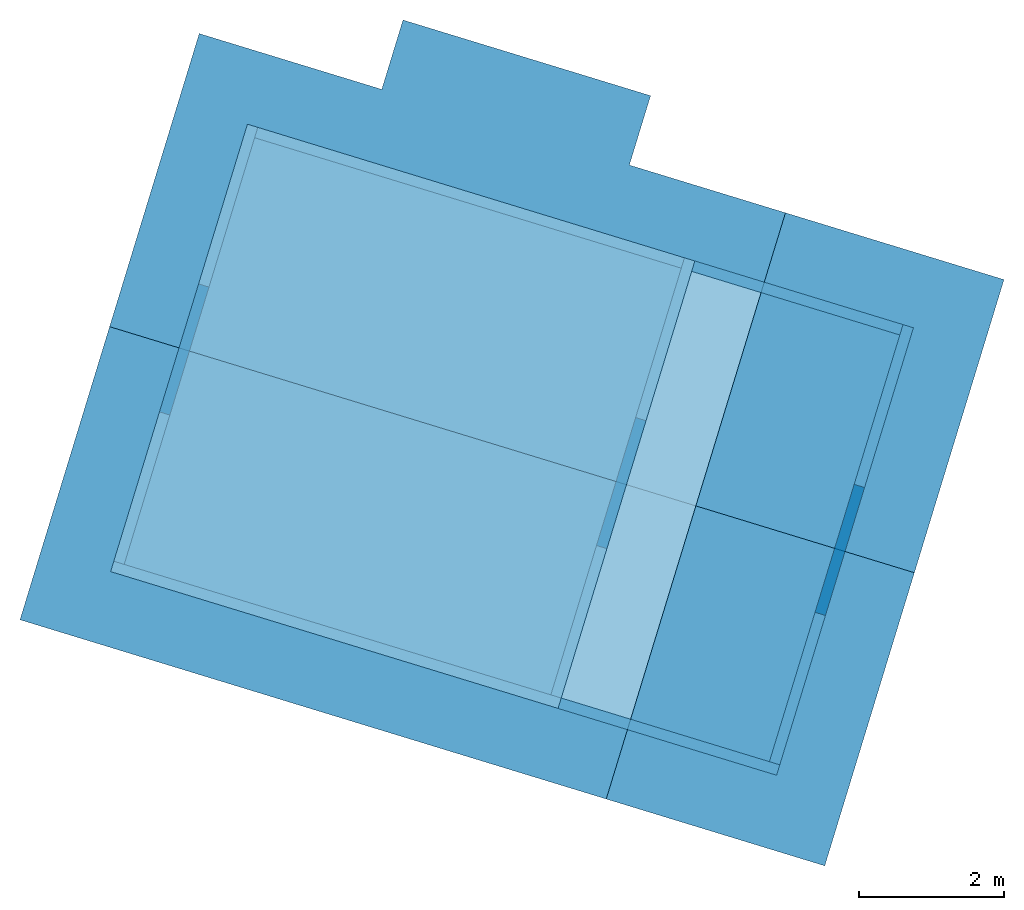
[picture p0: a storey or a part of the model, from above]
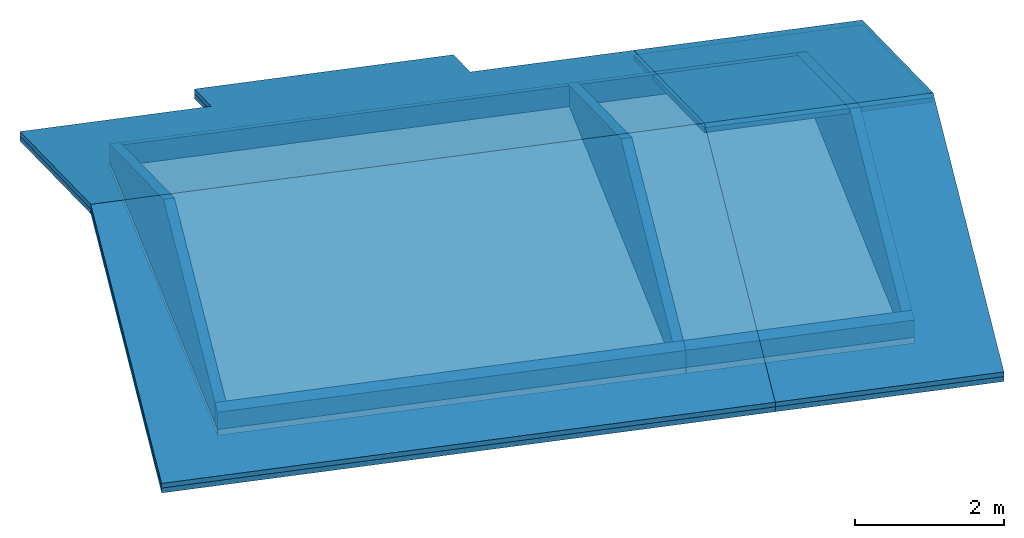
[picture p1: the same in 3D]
Properties of the parts of a building model (IFC2X3), part 1 of 7

# File
Description: ViewDefinition [, SurfaceGeometryAddOnView, QuantityTakeOffAddOnView, SpaceBoundary2ndLevelAddOnView], Option [Elements to export: Visible elements (on all stories)], Option [Partial Structure Display: Entire Model], Option [IFC Domain: All], Option [Structural Function: All Elements], Option [Convert Grid elements: On], Option [Convert IFC Annotations and Archicad 2D elements: On], Option [Convert 2D symbols of Doors and Windows: On], Option [Export geometries that Participates in Collision Detection only: Off], Option [Split complex elements: Off], Option [Material Preservation: Explode where necessary], Option [IFC Model position: Survey Point and Project Origin], Option [Curtain Wall export mode: Single Element], Option [Railing export mode: Single Element], Option [Stair export mode: Single Element], Option [Properties To Export: Current Scheme properties only], Option [Space containment: On], Option [IFC Domain For Space Containment: All], Option [Geometry to type objects: Off], Option [Element Properties: All], Option [Building Material Properties: On], Option [Element Parameters: All], Option [Component Parameters: All], Option [IFC Base Quantities: On], Option [Door Window Parameters: On], Option [IFC Space boundaries: On], Option [Archicad Zone Categories as IFC Space classification data: On], Option [Element Classifications: On]
File name: /Users/gustavo/Desktop/Academico/PHD/PAP - AUT0518/2024/Casa térrea CDHU - TI13A-V2_v01.ifc
Time: 2024-06-12T14:25:20
Author: Oliveira Gustavo
Organization: Faculdade de Arquitetura e Urbanismo da Universidade de Sao Paulo
Written by: DDS_IFC v3.0
Made in: IFC file generated by Graphisoft Archicad 27.0.0 INT FULL Macintosh version (IFC add-on version: 5001 INT FULL).
Authorization: Oliveira Gustavo

# IfcSite, Site
RefLatitude: -23, -36, -48, -600000; RefLongitude: -46, -41, -38, -500000; RefElevation: 728220 mm
BaseQuantities - GrossPerimeter: 0 mm; GrossArea: 0 m2

# IfcBuilding, Casa Térrea Isolada
Description: Jardim-Edite-Pavimento-Tipo
BaseQuantities - GrossFloorArea: 62.094 m2

# IfcBuildingStorey (2)
In: Casa Térrea Isolada
BaseQuantities - NetHeight: 2500 mm; GrossHeight: 2500 mm; Height: 2500 mm
Name | Elevation (mm) | GrossFloorArea (m2)
Cobertura | 2500 | 0
Terreo | 0 | 62.094

# IfcSpace: Area Privativa (8)
In: Terreo
InteriorOrExteriorSpace: INTERNAL
ArchiCADProperties - Surface: Vidro - Azul; Uniform Surface: yes; Zone Category: 0; Zone Category Code: APT; Library Part Name: Selo de Zona BRA 26; Locked: no; Home Story Name: Terreo; Home Story Number: 0; Element Type: Zone; Absolute Top Link Story: Cobertura; Relative Top Link Story: Home + 1; Top Link Story: Home + 1 (Cobertura); Surfaces (All): Vidro - Azul; Cover Fill: 25 %; Show On Renovation Filter: All Relevant Filters
INFORMAÇÕES DO PRODUTO - Data de Aquisição: DD/MM/YYYY
AC_Pset_Selo_de_Zona_BRA_26 - Tamanho Texto Marcador 1(Padrão): 1.5; Fonte do Texto: Arial; Estilo Texto Marcador 1(Padrão): 0; Alinhamento Texto Marcador 1 (padrão): 2; Espaço entre Linhas Texto Marcador 1 (padrão): 1; Fator de Largura do Caractere Texto Marcador 1 (padrão): 1; Espaçamento do Caractere Texto Marcador 1 (padrão): 1; Caneta Texto Marcador 1(Padrão): Texto - Cotas; Área da Superfície das Paredes do Perímetro: 8.118; Área da Superfície das Portas: 0; Área da Superfície das Janelas: 0; Área da Parede Extraída: 0; Área de Parede Cortina Extraída: 0; Área da Coluna Extraída: 0; Área Trama Extraída: 0; Áreas Baixas Extraídas: 0; Área Total Extraída: 0; Factor Área Zona: 1; Área de Superfície do Topo do Telhado: 0; Área de Superfície da Base do Telhado: 0; Área de Superfície no Topo da Laje: 0; Área de Superfície no Fundo da Laje: 0; Área da Superfície da Viga no Topo: 0; Superfície da Viga na Base: 0; Área da Superfície do Topo das Inserções da Parede: 0; Superfície de Trás das Inserções da Parede: 0; Área de Superfície do Lado das Inserções da Parede: 0; Nome de Zona (bShowZoneName): yes; Usar Categoria como Nome: no; ID do Element: no; Mostrar ID como...: 2; Área: yes; Tipo de Área: 1; Nível: no; Tipo de Nível: 1; Nível Pavimento Acabado Automático: no; Nível Pavimento Acabado Personal.: ±0.00; Prefixo Acabamento Nível Pavimento: 1; Título Acabamento Nível Pavimento: ANP; Nível Zona Automático: no; Nível Zona Personal.: -0.10; Prefixo Nível Zona: 1; Título Nível Zona: NZ; Acabamento do Piso: no; Código de Acabamento Piso: 0; Acabamento Parede: no; Código de Acabamento Parede: 0; Acabamento do Teto: no; Código de Acabamento do Teto: 0; Acabamento Rodapé: no; Código de Acabamento Rodapé: 0; Acabamento Peitoril / Soleira: no; Código de Acabamento Peitoril / Soleira: 0; Sobrepor Formato do Texto Nome da Zona: no; Nome da Zona Tipo de Fonte: Arial; Nome da Zona Tamanho da Fonte: 2.5; Estilo de Texto Nome da Zona: 1; Caneta Nome de Zona (penZoneName): Aberturas - Geral; Caneta Nome de Zona (penZoneName_int): 3; Sobrepor Formato do Texto Códigos de Acabamento: no; Fonte do Acabamento: Arial; Tamanho do Texto do Acabamento: 2; Estilo de Texto Códigos de Acabamento: 0; Caneta Códigos de Acabamento (penFinish): Zonas - Geral; Caneta Códigos de Acabamento (penFinish_int): 14; Tamanho da forma automático: yes; Diâmetro da cota de nível: 3; Altura da forma: 4.5; Preço por m2: 0; Preço por m3: 0; Preço Calculado a partir de Área Medida: 0; Preço Calculado a partir de Área Útil Medida: 0; Preço Calculado a partir de Área Reduzida: 0; Preço Calculado a partir de Área Calculada: 0; Preço Calculado a partir de Volume Útil: 0; Preço Calculado a partir de Volume Bruto: 0; Ângulo de Rotação: 0 deg
Pset_SpaceCommon - Category: Area Privativa
ZONAS - Iluminação Mínima: 0; Ventilação Mínima: 0
GARANTIA - Ínicio da Garantia: DD/MM/YYYY; Fim da Garantia: DD/MM/YYYY
FABRICAÇÃO - Data de Fabricação: DD/MM/YYYY; Site do Produto: www.graphisoft.com
ILUMINAÇÃO E VENTILAÇÃO (Expressão) - Atende: Atende; Não Atende: Não Atende
RODAPÉ (Expressão) - Comprimento da Barra (m): 2.4; Custo da Barra: 0; Estimativa de Custo: 0
PISOS (Expressão) - Índice de Perda (%): 10
REVESTIMENTO DE PAREDE POR ZONA (Expressão) - Número de Linhas: 10; DImensão 1: 0 mm; Dimensão 2: 0 mm; Largura do Rejunte: 10 mm; Altura do Revestimento: 100 mm
COBERTURA (Expressão) - Rendimento de Telha Genérica (m2): 0; Índice de Perda Telhas (%): 0; Rendimento Cumeeira (ml): 0
ESTRUTURA (Expressão) - Custo por Volume (m3): 0
DESCRIÇÃO DA ESCADA (Expressão) - Abreviação da Largura da Escada: L; Abreviação da Altura do Espelho: E; Abreviação da Profundidade do Piso: P
BaseQuantities - Height: 2500 mm; FinishCeilingHeight: 2500 mm; FinishFloorHeight: 0 mm; ClearHeight: 2500 mm
ArchiCADQuantities - Number of Beams: 0; Number of Columns: 0; Number of Lamps: 0; Walls Perimeter: 3690 mm; Floor Thickness: 0 mm; Area Reducement: 1 m2; Extracted Column Area: 0 m2; Extracted Fill Area: 0 m2; Extracted Low Area: 0 m2; Extracted Wall Area: 0 m2; Total Extracted Area: 0 m2; Wall Inset Back Side Surface Area: 0 m2; Wall Inset Side Surface Area: 0 m2; Wall Inset Top Surface Area: 0 m2; Extracted Curtain Wall Area: 0 m2; Height: 2500 mm; Elevation to Project Zero: 0 mm; Elevation to 1º Nível de Referência: 0 mm; Elevation to 2º Nível de Referência: 0 mm; Elevation to Sea Level: 728220 mm; Elevation to Linked/Home Story: 0 mm; Home Offset: 0 mm; Top Offset: 0 mm; Floor Plan Holes Perimeter: 0 mm; Top Elevation To First Reference Level: 2500 mm; Top Elevation To Home Story: 2500 mm; Top Elevation To Project Zero: 2500 mm; Top Elevation To Sea Level: 730720 mm; Top Elevation To Second Reference Level: 2500 mm; Bottom Elevation To First Reference Level: 0 mm; Bottom Elevation To Home Story: 0 mm; Bottom Elevation To Project Zero: 0 mm; Bottom Elevation To Sea Level: 728220 mm; Bottom Elevation To Second Reference Level: 0 mm
ALVENARIAS (Expressão) - Espessura da Argamassa: 10 mm
AC_Equantity_Selo_de_Zona_BRA_26 - Perímetro dos Vãos: 0 mm; Comprimento das Paredes Perímetro: 3690 mm; Largura Combinada das Portas: 0 mm; Largura Combinada das Janelas: 0 mm; Nível do Piso: 0 mm; Espessura do Subpiso: 0 mm; Altura: 2500 mm; Afastamento X: -1142.57 mm; Afastamento Y: -1593.03 mm
Name | LongName = Zone Name = Related Zone Name = Nome de Zona (ROOM_NAME) | Classification | Zone Number = Related Zone Number = Número da Zona | Element ID = Hotlink and Element ID = Parent ID | Layer | Design Option Name | Design Option Set Name = Design Option Set | Renovation Status | Design Option Status | Área Medida = Área Útil Medida = Área Reduzida = Área Calculada = Área da Superfície do Topo = Área da Superfície do Fundo = GrossFloorArea (m2) = NetFloorArea (m2) = SpaceNetFloorAreaBOMA (m2) = SpaceUsableFloorAreaBOMA (m2) = GrossCeilingArea (m2) = NetCeilingArea (m2) = Calculated Area (m2) = Measured Area (m2) = Measured Net Area (m2) = Reduced Area (m2) = Area (m2) = Top Surface Area (Net) (m2) = Bottom Surface Area (Net) (m2) = Área da Superfície da Base (Geral) (m2) | Nº do Todos os Cantos = Number of the Corners | Nº dos Cantos Côncavos = Number of the Concave Corners | Volume | Área da Superfície das Bordas = Edge Surface Area (Net) (m2) | Área das Aberturas Projetada = Windows Surface Area (m2) | Quantidade de Barras | Zona - Número de Azulejos Necessários | Localização do Produto no Projeto | ID de Aberturas com Master ID | ID Dinâmico por Classificação | GrossWallArea (m2) | NetWallArea (m2) = Walls Surface Area (m2) | GrossPerimeter (mm) = NetPerimeter (mm) = Zone Net Perimeter (mm) = Zone Gross Perimeter (mm) = Perímetro (mm) = Perímetro Útil (mm) | GrossVolume (m3) = NetVolume (m3) = Volume (Net) (m3) | Number of Doors | Number of Objects | Number of Windows | Number of Wall Parts | Doors Surface Area (m2) | Doors Width (mm) | Windows Width (mm) | Estimativa de Rodapé (ml) (mm)
02 | Dormitorio 01 | Área Residencial (Classificação ARCHICAD); 4A 19 01 01 Dormitório (NBR 15965-6 4A); APT Area Privativa | 02 | Zona 02 | CDHU-Ambiente | Main Model | Main Model | Existing | Main Model | 9 | 4 | 0 | 24.3 | 32.4 | 1 | 1 | 11150 | Projeto: Casa Térrea IsoladaLocal: Piso: Terreo Cômodo: Dormitorio 01 | 02Zona 02 | Área Residencial -Zona 02 | 30 | 27.13 | 12000 | 22.5 | 1 | 2 | 1 | 4 | 1.87 | 850 | 1000 | 2840 | ArchiCADProperties - Related Element(s) 3D: MB08; MB11
05 | Hall | Área Residencial (Classificação ARCHICAD); APT Area Privativa; 4A 19 04 10 Circulação (NBR 15965-6 4A) | 05 | Zona 05 | CDHU-Ambiente | Main Model | Main Model | Existing | Main Model | 1.0625 | 4 | 0 | 2.86876 | 11.34 | 0 | 1 | 2500 | Projeto: Casa Térrea IsoladaLocal: Piso: Terreo Cômodo: Hall | 05Zona 05 | Área Residencial -Zona 05 | 8.375 | 4.635 | 4200 | 2.65626 | 2 | 0 | 0 | 3 | 3.74 | 1700 | 0 | 1990
04 | Banho | Área Residencial (Classificação ARCHICAD); APT Area Privativa; 4A 19 04 07 Banheiro residencial (NBR 15965-6 4A) | 04 | Zona 04 | CDHU-Ambiente | Main Model | Main Model | Existing | Main Model | 2.2 | 4 | 0 | 5.94001 | 16.74 | 0.672 | 1 | 5350 | Projeto: Casa Térrea IsoladaLocal: Piso: Terreo Cômodo: Banho | 04Zona 04 | Área Residencial -Zona 04 | 15.5 | 12.958 | 6200.01 | 5.50001 | 1 | 3 | 1 | 4 | 1.87 | 850 | 840 | 2840 | ArchiCADProperties - Related Element(s) 3D: FX02; FX03; FX04
03 | Dormitorio 02 | Área Residencial (Classificação ARCHICAD); 4A 19 01 01 Dormitório (NBR 15965-6 4A); APT Area Privativa | 03 | Zona 03 | CDHU-Ambiente | Main Model | Main Model | Existing | Main Model | 9 | 4 | 0 | 24.3 | 32.4 | 1 | 1 | 11150 | Projeto: Casa Térrea IsoladaLocal: Piso: Terreo Cômodo: Dormitorio 02 | 03Zona 03 | Área Residencial -Zona 03 | 30 | 27.13 | 12000 | 22.5 | 1 | 3 | 1 | 4 | 1.87 | 850 | 1000 | 2840 | ArchiCADProperties - Related Element(s) 3D: MB09; MB10; MB12
01 | Sala / Cozinha | Área Residencial (Classificação ARCHICAD); APT Area Privativa; 4A 19 01 07 Sala de Estar (NBR 15965-6 4A) | 01 | Zona 01 | CDHU-Ambiente | Main Model | Main Model | Existing | Main Model | 14.7 | 4 | 0 | 39.69 | 42.66 | 2.008 | 1 | 14100 | Projeto: Casa Térrea IsoladaLocal: Piso: Terreo Cômodo: Sala / Cozinha | 01Zona 01 | Área Residencial -Zona 01 | 37.375 | 31.627 | 15800 | 36.75 | 2 | 8 | 2 | 4 | 3.74 | 1700 | 1840 | 1990 | ArchiCADProperties - Related Element(s) 3D: FX01; MB01; MB02; MB03; MB04; MB05; MB06; MB07
06 | Futura Ampliacao | Área Residencial (Classificação ARCHICAD); 4A 19 01 01 Dormitório (NBR 15965-6 4A); APT Area Privativa | 06 | Zona 06 | CDHU-Ampliacao | Ampliacao | New Option Set | New | New Option Set - Ampliacao | 7.6 | 6 | 1 | 19 | 30 | 1 | 2 | 12000 | Projeto: Casa Térrea IsoladaLocal: Piso: Terreo Cômodo: Futura Ampliacao | 06Zona 06 | Área Residencial -Zona 06 | 27.8125 | 26.8125 | 12000 | 19 | 0 | 0 | 1 | 6 | 0 | 0 | 1000 | 3690
08 | Futura Ampliacao | Área Residencial (Classificação ARCHICAD); 4A 19 01 01 Dormitório (NBR 15965-6 4A); APT Area Privativa | 08 | Zona 08 | CDHU-Ampliacao | Ampliacao | New Option Set | New | New Option Set - Ampliacao | 9 | 4 | 0 | 24.3 | 32.4 | 1 | 2 | 12000 | Projeto: Casa Térrea IsoladaLocal: Piso: Terreo Cômodo: Futura Ampliacao | 08Zona 08 | Área Residencial -Zona 08 | 27.8125 | 26.8125 | 12000 | 22.5 | 0 | 0 | 1 | 4 | 0 | 0 | 1000 | 3690
07 | Futura Ampliacao | Área Residencial (Classificação ARCHICAD); APT Area Privativa; 4A 16 16 04 Hall (NBR 15965-6 4A) | 07 | Zona 07 | CDHU-Ampliacao | Ampliacao | New Option Set | New | New Option Set - Ampliacao | 1.0625 | 4 | 0 | 2.86876 | 11.34 | 0 | 2 | 4200 | Projeto: Casa Térrea IsoladaLocal: Piso: Terreo Cômodo: Futura Ampliacao | 07Zona 07 | Área Residencial -Zona 07 | 6.12502 | 6.12502 | 4200 | 2.65626 | 0 | 0 | 0 | 4 | 0 | 0 | 0 | 3690

# IfcBuildingElementPart (8)
In: Cobertura
Pset_ManufacturerTypeInformation - ProductionYear: DD/MM/YYYY
Name | Material | Embodied Carbon | Embodied Energy (MJ) | Component Type | Mass (kg) | Projected Component Area (Net) (m2) | Projected Component Area (Gross) (m2) | Component Thickness (mm) | Component Volume (Net) (m3) | Component Volume (Gross) (m3)
Madeiramento - Estrutural | Madeiramento - Estrutural | 742.306 (kgCO₂) | 23030.5 | Core | 1903.35 | 36.7223 | 38.7049 | 75 | 2.71907 | 2.88386 | Material Properties - Madeiramento - Estrutural, ThermalConductivity: 0.18; Madeiramento - Estrutural, SpecificHeatCapacity: 1600 J/kg/K; Madeiramento - Estrutural, MassDensity: 700 kg/m3; Madeiramento - Estrutural, Embodied Energy: 12.1 (MJ/kg); Madeiramento - Estrutural, Embodied Carbon: 0.39 (kgCO₂/kg); Madeiramento - Estrutural, Name: Madeiramento - Estrutural; Madeiramento - Estrutural, ID: MAD; Madeiramento - Estrutural, Participates in Collision Detection: yes; Madeiramento - Estrutural, Data de Aquisição: DD/MM/YYYY; Madeiramento - Estrutural, Data de Fabricação: DD/MM/YYYY; Madeiramento - Estrutural, Site do Produto: www.graphisoft.com; Madeiramento - Estrutural, Ínicio da Garantia: DD/MM/YYYY; Madeiramento - Estrutural, Fim da Garantia: DD/MM/YYYY; Madeiramento - Estrutural, Iluminação Mínima: 0; Madeiramento - Estrutural, Ventilação Mínima: 0; Madeiramento - Estrutural, Atende: Atende; Madeiramento - Estrutural, Não Atende: Não Atende; Madeiramento - Estrutural, Índice de Perda (%): 10; Madeiramento - Estrutural, DImensão 1: 0 mm; Madeiramento - Estrutural, Dimensão 2: 0 mm; Madeiramento - Estrutural, Largura do Rejunte: 10 mm; Madeiramento - Estrutural, Número de Linhas: 10; Madeiramento - Estrutural, Comprimento da Barra (m): 2.4; Madeiramento - Estrutural, Custo da Barra: 0; Madeiramento - Estrutural, Espessura da Argamassa: 10 mm; Madeiramento - Estrutural, Rendimento de Telha Genérica (m2): 0; Madeiramento - Estrutural, Índice de Perda Telhas (%): 0; Madeiramento - Estrutural, Rendimento Cumeeira (ml): 0; Madeiramento - Estrutural, Custo por Volume (m3): 0; Madeiramento - Estrutural, Abreviação da Largura da Escada: L; Madeiramento - Estrutural, Abreviação da Altura do Espelho: E; Madeiramento - Estrutural, Abreviação da Profundidade do Piso: P
Telha - Cobertura | Telha - Cobertura | 1291.97 (kgCO₂) | 16149.6 | Finish | 5383.2 | 38.688 | 38.688 | 70 | 2.6916 | 2.6916 | Component Quantities - Projected Component Area (Conditional): 38.688 m2; Component Volume (Conditional): 2.6916 m3; Material Properties - Telha - Cobertura, ThermalConductivity: 1; Telha - Cobertura, SpecificHeatCapacity: 800 J/kg/K; Telha - Cobertura, MassDensity: 2000 kg/m3; Telha - Cobertura, Embodied Energy: 3 (MJ/kg); Telha - Cobertura, Embodied Carbon: 0.24 (kgCO₂/kg); Telha - Cobertura, Name: Telha - Cobertura; Telha - Cobertura, ID: VED; Telha - Cobertura, Participates in Collision Detection: yes; Telha - Cobertura, Data de Aquisição: DD/MM/YYYY; Telha - Cobertura, Data de Fabricação: DD/MM/YYYY; Telha - Cobertura, Site do Produto: www.graphisoft.com; Telha - Cobertura, Ínicio da Garantia: DD/MM/YYYY; Telha - Cobertura, Fim da Garantia: DD/MM/YYYY; Telha - Cobertura, Iluminação Mínima: 0; Telha - Cobertura, Ventilação Mínima: 0; Telha - Cobertura, Atende: Atende; Telha - Cobertura, Não Atende: Não Atende; Telha - Cobertura, Índice de Perda (%): 10; Telha - Cobertura, DImensão 1: 0 mm; Telha - Cobertura, Dimensão 2: 0 mm; Telha - Cobertura, Largura do Rejunte: 10 mm; Telha - Cobertura, Número de Linhas: 10; Telha - Cobertura, Comprimento da Barra (m): 2.4; Telha - Cobertura, Custo da Barra: 0; Telha - Cobertura, Espessura da Argamassa: 10 mm; Telha - Cobertura, Rendimento de Telha Genérica (m2): 0; Telha - Cobertura, Índice de Perda Telhas (%): 0; Telha - Cobertura, Rendimento Cumeeira (ml): 0; Telha - Cobertura, Custo por Volume (m3): 0; Telha - Cobertura, Abreviação da Largura da Escada: L; Telha - Cobertura, Abreviação da Altura do Espelho: E; Telha - Cobertura, Abreviação da Profundidade do Piso: P
Telha - Cobertura | Telha - Cobertura | 1421.11 (kgCO₂) | 17763.9 | Finish | 5921.29 | 42.5315 | 42.5315 | 70 | 2.96064 | 2.96064 | Component Quantities - Projected Component Area (Conditional): 42.5315 m2; Component Volume (Conditional): 2.96064 m3; Material Properties - Telha - Cobertura, ThermalConductivity: 1; Telha - Cobertura, SpecificHeatCapacity: 800 J/kg/K; Telha - Cobertura, MassDensity: 2000 kg/m3; Telha - Cobertura, Embodied Energy: 3 (MJ/kg); Telha - Cobertura, Embodied Carbon: 0.24 (kgCO₂/kg); Telha - Cobertura, Name: Telha - Cobertura; Telha - Cobertura, ID: VED; Telha - Cobertura, Participates in Collision Detection: yes; Telha - Cobertura, Data de Aquisição: DD/MM/YYYY; Telha - Cobertura, Data de Fabricação: DD/MM/YYYY; Telha - Cobertura, Site do Produto: www.graphisoft.com; Telha - Cobertura, Ínicio da Garantia: DD/MM/YYYY; Telha - Cobertura, Fim da Garantia: DD/MM/YYYY; Telha - Cobertura, Iluminação Mínima: 0; Telha - Cobertura, Ventilação Mínima: 0; Telha - Cobertura, Atende: Atende; Telha - Cobertura, Não Atende: Não Atende; Telha - Cobertura, Índice de Perda (%): 10; Telha - Cobertura, DImensão 1: 0 mm; Telha - Cobertura, Dimensão 2: 0 mm; Telha - Cobertura, Largura do Rejunte: 10 mm; Telha - Cobertura, Número de Linhas: 10; Telha - Cobertura, Comprimento da Barra (m): 2.4; Telha - Cobertura, Custo da Barra: 0; Telha - Cobertura, Espessura da Argamassa: 10 mm; Telha - Cobertura, Rendimento de Telha Genérica (m2): 0; Telha - Cobertura, Índice de Perda Telhas (%): 0; Telha - Cobertura, Rendimento Cumeeira (ml): 0; Telha - Cobertura, Custo por Volume (m3): 0; Telha - Cobertura, Abreviação da Largura da Escada: L; Telha - Cobertura, Abreviação da Altura do Espelho: E; Telha - Cobertura, Abreviação da Profundidade do Piso: P
Madeiramento - Estrutural | Madeiramento - Estrutural | 821.002 (kgCO₂) | 25472.1 | Core | 2105.13 | 40.5658 | 42.5484 | 75 | 3.00733 | 3.17212 | Material Properties - Madeiramento - Estrutural, ThermalConductivity: 0.18; Madeiramento - Estrutural, SpecificHeatCapacity: 1600 J/kg/K; Madeiramento - Estrutural, MassDensity: 700 kg/m3; Madeiramento - Estrutural, Embodied Energy: 12.1 (MJ/kg); Madeiramento - Estrutural, Embodied Carbon: 0.39 (kgCO₂/kg); Madeiramento - Estrutural, Name: Madeiramento - Estrutural; Madeiramento - Estrutural, ID: MAD; Madeiramento - Estrutural, Participates in Collision Detection: yes; Madeiramento - Estrutural, Data de Aquisição: DD/MM/YYYY; Madeiramento - Estrutural, Data de Fabricação: DD/MM/YYYY; Madeiramento - Estrutural, Site do Produto: www.graphisoft.com; Madeiramento - Estrutural, Ínicio da Garantia: DD/MM/YYYY; Madeiramento - Estrutural, Fim da Garantia: DD/MM/YYYY; Madeiramento - Estrutural, Iluminação Mínima: 0; Madeiramento - Estrutural, Ventilação Mínima: 0; Madeiramento - Estrutural, Atende: Atende; Madeiramento - Estrutural, Não Atende: Não Atende; Madeiramento - Estrutural, Índice de Perda (%): 10; Madeiramento - Estrutural, DImensão 1: 0 mm; Madeiramento - Estrutural, Dimensão 2: 0 mm; Madeiramento - Estrutural, Largura do Rejunte: 10 mm; Madeiramento - Estrutural, Número de Linhas: 10; Madeiramento - Estrutural, Comprimento da Barra (m): 2.4; Madeiramento - Estrutural, Custo da Barra: 0; Madeiramento - Estrutural, Espessura da Argamassa: 10 mm; Madeiramento - Estrutural, Rendimento de Telha Genérica (m2): 0; Madeiramento - Estrutural, Índice de Perda Telhas (%): 0; Madeiramento - Estrutural, Rendimento Cumeeira (ml): 0; Madeiramento - Estrutural, Custo por Volume (m3): 0; Madeiramento - Estrutural, Abreviação da Largura da Escada: L; Madeiramento - Estrutural, Abreviação da Altura do Espelho: E; Madeiramento - Estrutural, Abreviação da Profundidade do Piso: P
2 x Madeiramento - Estrutural | Madeiramento - Estrutural | 276.204 (kgCO₂) | 8569.41 | Core | 708.216 | 13.6443 | 14.4284 | 75 | 1.01174 | 1.07505 | Material Properties - Madeiramento - Estrutural, ThermalConductivity: 0.18; Madeiramento - Estrutural, SpecificHeatCapacity: 1600 J/kg/K; Madeiramento - Estrutural, MassDensity: 700 kg/m3; Madeiramento - Estrutural, Embodied Energy: 12.1 (MJ/kg); Madeiramento - Estrutural, Embodied Carbon: 0.39 (kgCO₂/kg); Madeiramento - Estrutural, Name: Madeiramento - Estrutural; Madeiramento - Estrutural, ID: MAD; Madeiramento - Estrutural, Participates in Collision Detection: yes; Madeiramento - Estrutural, Data de Aquisição: DD/MM/YYYY; Madeiramento - Estrutural, Data de Fabricação: DD/MM/YYYY; Madeiramento - Estrutural, Site do Produto: www.graphisoft.com; Madeiramento - Estrutural, Ínicio da Garantia: DD/MM/YYYY; Madeiramento - Estrutural, Fim da Garantia: DD/MM/YYYY; Madeiramento - Estrutural, Iluminação Mínima: 0; Madeiramento - Estrutural, Ventilação Mínima: 0; Madeiramento - Estrutural, Atende: Atende; Madeiramento - Estrutural, Não Atende: Não Atende; Madeiramento - Estrutural, Índice de Perda (%): 10; Madeiramento - Estrutural, DImensão 1: 0 mm; Madeiramento - Estrutural, Dimensão 2: 0 mm; Madeiramento - Estrutural, Largura do Rejunte: 10 mm; Madeiramento - Estrutural, Número de Linhas: 10; Madeiramento - Estrutural, Comprimento da Barra (m): 2.4; Madeiramento - Estrutural, Custo da Barra: 0; Madeiramento - Estrutural, Espessura da Argamassa: 10 mm; Madeiramento - Estrutural, Rendimento de Telha Genérica (m2): 0; Madeiramento - Estrutural, Índice de Perda Telhas (%): 0; Madeiramento - Estrutural, Rendimento Cumeeira (ml): 0; Madeiramento - Estrutural, Custo por Volume (m3): 0; Madeiramento - Estrutural, Abreviação da Largura da Escada: L; Madeiramento - Estrutural, Abreviação da Altura do Espelho: E; Madeiramento - Estrutural, Abreviação da Profundidade do Piso: P
2 x Telha - Cobertura | Telha - Cobertura | 481.621 (kgCO₂) | 6020.26 | Finish | 2006.75 | 14.4221 | 14.4221 | 70 | 1.00338 | 1.00338 | Component Quantities - Projected Component Area (Conditional): 14.4221 m2; Component Volume (Conditional): 1.00338 m3; Material Properties - Telha - Cobertura, ThermalConductivity: 1; Telha - Cobertura, SpecificHeatCapacity: 800 J/kg/K; Telha - Cobertura, MassDensity: 2000 kg/m3; Telha - Cobertura, Embodied Energy: 3 (MJ/kg); Telha - Cobertura, Embodied Carbon: 0.24 (kgCO₂/kg); Telha - Cobertura, Name: Telha - Cobertura; Telha - Cobertura, ID: VED; Telha - Cobertura, Participates in Collision Detection: yes; Telha - Cobertura, Data de Aquisição: DD/MM/YYYY; Telha - Cobertura, Data de Fabricação: DD/MM/YYYY; Telha - Cobertura, Site do Produto: www.graphisoft.com; Telha - Cobertura, Ínicio da Garantia: DD/MM/YYYY; Telha - Cobertura, Fim da Garantia: DD/MM/YYYY; Telha - Cobertura, Iluminação Mínima: 0; Telha - Cobertura, Ventilação Mínima: 0; Telha - Cobertura, Atende: Atende; Telha - Cobertura, Não Atende: Não Atende; Telha - Cobertura, Índice de Perda (%): 10; Telha - Cobertura, DImensão 1: 0 mm; Telha - Cobertura, Dimensão 2: 0 mm; Telha - Cobertura, Largura do Rejunte: 10 mm; Telha - Cobertura, Número de Linhas: 10; Telha - Cobertura, Comprimento da Barra (m): 2.4; Telha - Cobertura, Custo da Barra: 0; Telha - Cobertura, Espessura da Argamassa: 10 mm; Telha - Cobertura, Rendimento de Telha Genérica (m2): 0; Telha - Cobertura, Índice de Perda Telhas (%): 0; Telha - Cobertura, Rendimento Cumeeira (ml): 0; Telha - Cobertura, Custo por Volume (m3): 0; Telha - Cobertura, Abreviação da Largura da Escada: L; Telha - Cobertura, Abreviação da Altura do Espelho: E; Telha - Cobertura, Abreviação da Profundidade do Piso: P

# IfcDoor: Porta 26 (2)
In: Terreo
Type - OperationType: SINGLE_SWING_LEFT; ParameterTakesPrecedence: no; Sizeable: no
Type - Door Lining Properties - LiningThickness: 50 mm; CasingThickness: 70 mm; CasingDepth: 19 mm
Type - Door Panel Properties - Panel 1 - PanelDepth: 30 mm; PanelOperation: SWINGING; PanelWidth: 1; PanelPosition: MIDDLE
Description: Porta 1 folha de abrir de madeira; OverallHeight: 2200 mm; OverallWidth: 850 mm; Classification: Porta (Classificação ARCHICAD); 3E 20 02 02 Portas (NBR 15965-5 3E)
ArchiCADProperties - Reveal Dimensions: 0,85×2,20; Wallhole Dimensions: 0,85×2,20; Unit Dimensions: 0,85×2,20; Egress Dimensions: 0,75×2,15; Leaf Dimensions: 0,77×2,16; Nominal W x H Size: 0,85×2,20; Nominal W x H x T Size: 0,85×2,20×0,15; Wall Structure: Bloco de Concreto - Estrutural; Marker Text: <Texto Personal.>; Orientation: D; Opening Library Part Name: Porta 26; Opening Side Fill Index: Trama Vazia; Layer: CDHU-Parede; Library Part Name: Porta 26; Building Material / Composite / Profile / Fill: Trama Vazia; Fill Type: Trama Vazia; Locked: no; Home Story Name: Terreo; Home Story Number: 0; Element Type: Door; Parent ID: Parede 03; Surfaces (All): Metal - Aço Inoxidável; Madeira - Pinho Granulado Horizontal; Metal - Ferro; Design Option Name: Main Model; Design Option Set Name: Main Model; Position: Interior; Show On Renovation Filter: All Relevant Filters; Structural Function: Non-Load-Bearing Element; Renovation Status: Existing; Design Option Status: Main Model; Design Option Set: Main Model
Pset_DoorCommon - ThermalTransmittance: 0; IsExternal: no
AC_Pset_Porta_26 - Contornos Parede (0-Nenhum,1-Completo,2-Lado,3-Comprimento): 0; Pontos-Quentes 0-Nenhum,1-2D,2-3D,3-Todos: 3; Mostrar Pontos-Quentes 2D em 3D: yes; Opção de Visualização em Planta: 3; Ângulo de Posição da Abertura: 0 deg; Furo tem Superfície Lateral Parede: yes; Furos em Divisão de Superfícies são Curvos em Paredes Curvas: no; Tipo de Parede: 1; Tipo de Direção de Parede: 2; Posição de Ancoragem da Abertura: 1; Direção da Abertura: 1; Corda: no; Inserir o Valor do Parapeito da Parede: 2; Demolição / Nova Construção: 1; Novo Tipo de Trama de Parede: Bloco; Nova Caneta de Trama de Parede: Geral - Geral; Nova Caneta de Fundo de Trama de Parede: Fundos - Cor 1; Mostrar nova construção na Parede: no; Tipo de linha de demolição: 1; Mostrar parâmetro Demolição / Novo: no; Visualizar como Travessa: no; Luz Lateral (gs_SidelightTransomRelation): Abaixo da Bandeira; Luz Lateral (gs_SidelightTransomRelation_m): 1; Luz Lateral 1: no; Luz Lateral 2: no; Bandeira: no; Tolerâncias Uniformes: yes; Tamanho Nominal: 1; Definir Tamanho de Vão como Tamanho Nominal: yes; Definir Tamanho de Reentrância como Tamanho Nominal: no; Definir Tamanho de Unidade como Tamanho Nominal: no; Definir Tamanho de Saída como Tamanho Nominal: no; Definir Tamanho de Folha como Tamanho Nominal: no; Transferir Tamanho Nominal Atual para Seleção: no; Mostrar Pontos-Quentes Editáveis: yes; 2D: 1; Mostrar Face de Vão em Símbolo: 2; Indicação Simbólica da Abertura: no; 3D: 8; Direção Abertura Luz Lateral (gs_opening_dir_sl): Oposta à Folha; Direção Abertura Luz Lateral (gs_opening_dir_sl_m): 2; Batente Porta (gs_pocket_door_frame): yes; Estilo Batente (gs_frame_style): Rebaixo Samblado; Estilo Batente (gs_frame_style_m): 3; Espessura Batente=Espessura Parede: yes; Espessura Uniforme do Batente: yes; Folha Centrada: yes; Largura Uniforme Batente: yes; Estilo Batente Alterado Automaticamente: no; Número de Folhas da Porta: 4; Número de Folhas da Porta - Lado 2: 3; Estilo Painel Portas: 1; Configuração Folhas (gs_LeavesConfig): Folhas Uniformes; Configuração Folhas (gs_iLeavesConfig): 1; Posição Grelha (gs_grill_pos): Por tudo; Posição Grelha (gs_grill_pos_m): 3; Número de Paineis Verticais: 4; Número de Paineis Horizontais: 3; Nº Paineis Verticais Lado 1: 4; Nº Paineis Horizontais Lado 1: 3; Mostrar como Painel de Vidro em Símbolo: no; Mostrar Símbolo Porta Primav. Chinesa: no; Mostrar Símbolo como Painel Hermético: no; Maçaneta Abertura (gs_handle_type): Maçaneta 5; Maçaneta Abertura (gs_handle_type_m): 15; Mostrar Maçaneta em Símbolo: no; Proteção Borda Externa (bKickBoardOut): no; Proteção Borda Interna (bKickBoardIn): no; Caixilhos Uniformes: no; Tipo Abertura (gs_optype_m_05): 3; Tipo Abertura (gs_optype_m_09): 3; Tipo Abertura (gs_optype_m_02): 1; Tipo Abertura (gs_optype_m_06): 1; Tipo Abertura (gs_optype_m_10): 1; Tipo Caixilho (MullionStyle_00): Sem Grelha; Tipo Caixilho (iMullionStyle_00): 1; Tipo Caixilho (iMullionStyle_05): 1; Tipo Caixilho (iMullionStyle_09): 1; Tipo Caixilho (iMullionStyle_02): 1; Tipo Caixilho (iMullionStyle_06): 1; Tipo Caixilho (iMullionStyle_10): 1; Editar Ponto-quente Grelha: yes; Posição Grelha (MullionPosition): Por tudo; Posição Grelha (iMullionPosition): 3; Nº Paineis Verticais Caixilho Principal Lado 1: 4; Nº Paineis Horizontais Caixilho Principal Lado 1: 2; Nº Paineis Verticais 2 Caixilho Principal Lado 1: 4; Nº Paineis Horizontais 2 Caixilho Principal Lado 1: 2; Nº Paineis Verticais Caixilho Principal Lado 2: 4; Nº Paineis Horizontais Caixilho Principal Lado 2: 2; Nº Paineis Verticais 2 Caixilho Principal Lado 2: 4; Nº Paineis Horizontais 2 Caixilho Principal Lado 2: 2; Nº Paineis Verticais Bandeira Meio: 2; Nº Paineis Horizontais Bandeira Meio: 2; Nº Paineis Verticais 2 Bandeira Meio: 2; Nº Paineis Horizontais 2 Bandeira Meio: 2; Nº Paineis Verticais Bandeira Lado 1: 2; Nº Paineis Horizontais Bandeira Lado 1: 2; Nº Paineis Verticais 2 Bandeira Lado 1: 2; Nº Paineis Horizontais 2 Bandeira Lado 1: 2; Nº Paineis Verticais Bandeira Lado 2: 2; Nº Paineis Horizontais Bandeira Lado 2: 2; Nº Paineis Verticais 2 Bandeira Lado 2: 2; Nº Paineis Horizontais 2 Bandeira Lado 2: 2; Guarnição Externa: yes; Tipo Guarnição Externa (gs_trimtype_out): Simples; Tipo Guarnição Externa (gs_trimtype_out_int): 1; Tipo de Travessa Guarnição Externa: 1; Arquitrave Principal: yes; Tipo Arquitrave Principal: 1; Guarnição/Alizar na Superfície Externa da Parede: yes; Larguras Uniformes da Guarnição (gs_trim_outside_uniform): yes; Guarnição Interna: yes; Tipo Guarnição Interna (gs_trimtype_in): Simples; Tipo Guarnição Interna (gs_trimtype_in_int): 1; Guarnição/Alizar na Superfície Interna da Parede: yes; Larguras Uniformes da Guarnição (gs_trim_inside_uniform): yes; Soleira (bThreshold): no; Tipo de Soleira: 4; Ângulo Soleira: 3.1996 deg; Soleira Alterou Automaticamente: no; Soleira Externa - Porta: no; Peitoril - Luz Lateral Lado 1: no; Peitoril - Luz Lateral Lado 2: no; Sobredim. Peitoril: no; Tipo de Parapeito Exterior: 3; Ângulo Peitoril: 10 deg; Parapeito Curvo em Paredes Curvas: yes; Isolamento abaixo do Peitoril: yes; Usar Camada Isolamento de Parede: no; Nível Detalhe 3D Peitoril Tijolo: 1; Estilo de Peitoril Alterou Automaticamente: no; Peitoril Interno - Luz Lateral Lado 1: no; Peitoril Interno - Luz Lateral Lado 2: no; Peitoril Interno - Porta: no; Ângulo Peitoril Int.: 0 deg; Peitoril Int. Curvado em Paredes Curvas: yes; Peitoril Int. em Paredes Poligonais: 1; Ventilação Natural: no; Tipo Ventilação Natural: 2; Quebra-Sol: no; Tipo Quebra-Sol: 1; Tipos de Quebra-Sol Ativados: 126; Número de Paineis: 2; Número de Paineis 2: 1; Posição Painel (gs_shutter_panelPos): Simétrico; Posição Painel (gs_shutter_iPanelPos): 1; Altura Automática Veneziana: yes; Batente Extra: no; Tipo Cobertura (gs_slidingShutter_cover): Perfil-Z; Tipo Cobertura (gs_slidingShutter_iCover): 1; Direção de Empilham. (gs_foldingShutter_stacking): Dentro; Direção de Empilham. (gs_foldingShutter_iStacking): 1; Abrir em 3D: yes; Ângulo de abertura 3D: 180 deg; Mostrar Símbolo 2D: yes; Mostrar Linhas de Abertura no Símbolo: no; Tipo Painel (gs_shutPanel_type): Estilo 1; Tipo Painel (gs_shutPanel_iType): 1; Largura Base Batente Diferente: no; Largura Automática Veneziana: yes; Ângulo Grelha Ventilação: 30 deg; Nº Vãos Horiz.: 5; Nº Vãos Vert.: 8; Posição Rolamento Veneziana (gs_shutRoll_placement): Na Fachada; Posição Rolamento Veneziana (gs_shutRoll_iPlacement): 1; Tipo Caixa (gs_shutRoll_boxType): Rectangular; Tipo Caixa (gs_shutRoll_iBoxType): 1; Posição Grade (gs_shutRoll_railPos): Em Guarnição; Posição Grade (gs_shutRoll_iRailPos): 1; Mostrar Guarnição Atrás do Quebra-Sol (gs_shutRoll_showCasingBehind): no; Isolamento Atrás da Caixa (gs_shutRoll_cutWallBehind): no; Incluir Altura na Altura do Vão da Parede: no; Ângulo de Topo da Caixa: 10 deg; Largura Caixa Original (gs_shutRoll_boxDefaultSize): Largura Face de Vão; Largura Caixa Original (gs_shutRoll_iBoxDefaultSize): 1; Colocação Persianas (gs_shutLam_placement): Fixada na Fachada; Colocação Persianas (gs_shutLam_iPlacement): 1; Isolamento Atrás da Caixa (gs_shutLam_cutWallBehind): no; Caixa Aberta: yes; Trilho (gs_shutLam_bRail): yes; Posição Grade (gs_shutLam_railPos): Em Guarnição; Posição Grade (gs_shutLam_iRailPos): 1; Mostrar Guarnição Atrás do Quebra-Sol (gs_shutLam_showCasingBehind): no; Ângulo Rotação das Lamelas (gs_shutLam_rotation): 45 deg; Ângulo Rotação das Lamelas (gs_shutLam2_rotation): 45 deg; Arco de Alvenaria (bMasonryArch): no; Arco de Alvenaria (gs_masonry_arch_int): 2; Tipo de Arco de Alvenaria (gs_masonry_arch_structure): Arco de Reboco; Tipo de Arco de Alvenaria (gs_masonry_arch_structure_int): 1; Arco no Topo: yes; Nicho abaixo do Arco: yes; Ângulo de Plano do Arco: 75 deg; Superfícies dos Nichos Personalizados: no; Tipo de Requadro (gs_reveal_type_new): Requadro Reto - Borda; Tipo de Requadro (gs_reveal_type_int): 1; Tipo de Requadro Base (gs_reveal_type_bottom): Requadro Reto; Tipo de Requadro Base (gs_reveal_type_bottom_int): 2; Definir Profund. Montante no Lado: 1; Profundidade Uniforme: yes; Tipo de Requadro Exterior: Requadro Reto; Tipo de Requadro (gs_reveal_doubleOuterTypeInt): 0; Tipo de Requadro Interior: Requadro Reto; Tipo de Requadro (gs_reveal_doubleInnerTypeInt): 0; Ângulo Lado 2: 20 deg; Ângulo Lado: 20 deg; Ângulo do Topo: 20 deg; Ângulo da Base: 20 deg; Ângulo Exterior Lado 2: 20 deg; Ângulo Exterior Lado: 20 deg; Ângulo Ext. Lado Superior: 20 deg; Ângulo Ext. Lado Inferior: 20 deg; Grade abaixo Folhas: no; Trilho (gs_door_rail_ext): Off; Trilho (gs_door_rail_ext_m): 1; Usar Componente de Acabamento: no; Auto Ligagem da Face Interna da Argamassa: yes; Ligar Face Interna da Argamassa: 0; Auto Ligagem da face Externa da Argamassa: yes; Ligar Face Externa da Argamassa: 0; Dimensionável em 2D: no; Mostrar em 3D: no; Tipo de Fechamento (gs_closure_type): Sem Fechamento; Tipo de Fechamento (gs_closure_type_int): 1; Dobrar Camada no Lado (gs_cavity_side): Ambas; Dobrar Camada no Lado (iCavityClosureSide): 1; No. de Camadas: 1; Numerar a partir de (gs_nTurnDir): Face externa; Numerar a partir de (iCavityClosureTurnDir): 1; Colocar Fechamento no Lado 1: yes; Colocar Fechamento no Lado 2: yes; Colocar Fechamento no Topo: no; Colocar Fechamento na Base: no; Colocar Fechamento para Camada: 1; Colocar Fechamento do Lado (gs_cc_dutch_ClosureToSide): 1; Fenda na Camada Externa: yes; Dobrar Camada para Encerram.: no; Inserir Camada de Isolamento: yes; Mostrar Camada de Isolamento: yes; Caneta de Contorno (gs_penJoint): Aberturas - Corte Não Estrutural; Tipo Linha Contorno (gs_ltJoint): 1; Tipo de Trama (gs_fillJoint): Isolamento 2; Caneta da Trama (gs_penJointFg): Geral - Geral; Caneta do Fundo da Trama (gs_penJointBg): Elementos 2D - Desenhos; Superfície Personalizada: no; Superfície: Madeira - Pinho Granulado Horizontal; Caneta de Contorno (gs_penPlug): Aberturas - Corte Não Estrutural; Tipo Linha Contorno (gs_ltPlug): 1; Tipo de Trama (gs_fillPlug): Isolamento 2; Caneta da Trama (gs_penPlugFg): Geral - Geral; Caneta do Fundo da Trama (gs_penPlugBg): Elementos 2D - Desenhos; Lado Ombreira Editado: 1; Lado Parede Editado: 1; Número de Camada Editado: 1; Camada que Dobra: no; Considerar Camada como Reboco: no; Espessura da Camada que Dobra: 1; Orientação Trama: 1; Linha Separa Camada que Dobra: no; Caneta Linha Separação: Geral - Geral; Último Lado Selecionado: no; Método de Fechamento Alterado Automaticamente: no; Conexão no Lado 1: no; Conexão no Lado 2: no; Conexão em Cima: no; Tipo Abertura (gs_leaf_optype): Preso Lateral; Tipo Abertura (gs_leaf_optype_m): 1; Abertura Painel Final Lado 1: no; Abertura Painel Final Lado 2: no; Ângulo Abertura 2D: 90 deg; Ângulo Abertura em 2D no Lado 2: 90 deg; Ângulo Abertura em 3D: 0 deg; Ângulo Abertura Terminação Painel em 3D Lado 2: 0 deg; Ângulo de Abertura Caixilho Principal Lado 1 (openingAngle_05): 0 deg; Ângulo de Abertura Caixilho Principal Lado 1 (openingAngle2_05): 0 deg; Ângulo de Abertura Caixilho Principal Lado 2 (openingAngle_09): 0 deg; Ângulo de Abertura Caixilho Principal Lado 2 (openingAngle2_09): 0 deg; Ângulo de Abertura Bandeira Meio (openingAngle_02): 0 deg; Ângulo de Abertura Bandeira Meio (openingAngle2_02): 0 deg; Ângulo de Abertura Bandeira Lado 1 (openingAngle_06): 0 deg; Ângulo de Abertura Bandeira Lado 1 (openingAngle2_06): 0 deg; Ângulo Abertura Bandeira Lado 2 (openingAngle_10): 0 deg; Ângulo Abertura Bandeira Lado 2 (openingAngle2_10): 0 deg; Tipo de Linha Duplo Sentido: 4; Substituir OVM para Visual. Simbólica 2D: no; Tipo Linha Abertura: 1; Forma da Linha de Abertura (or_SwingType): Curva; Forma da Linha de Abertura (or_iSwingType): 1; Forma da Linha de Abertura (or_SlidingType): Nenhum; Forma da Linha de Abertura (or_iSlidingType): 0; Mostrar Linha da Vidraça em 2D: yes; Caneta da Linha da Vidraça em 2D (or_iGlazingLinePen): 3; Caneta da Linha da Vidraça em 2D (or_glazingLinePen): Aberturas - Geral; Substituir OVM para Projeções 3D da Porta: no; Mostrar Linha de Abertura (or_bOplines3d): yes; Tipo Linha Lado da Abertura (or_opLineType3dIn): Linha Sólida; Tipo Linha Lado da Abertura (or_iOpLineType3dIn): 0; Tipo Linha Lado Oposto (or_opLineType3dOut): Linha Sólida; Tipo Linha Lado Oposto (or_iOpLineType3dOut): 0; Orientação da Linha (or_oplineStyle): Maçaneta; Orientação da Linha (or_iOplineStyle): 1; Caneta de Linha de Abertura em 2D/3D (or_opLinePen): Aberturas - Geral; Caneta de Linha de Abertura em 2D/3D (or_iOpLinePen): 3; Substituir OVM para Projeções 3D Luz Lateral/Bandeira: no; Mostrar Linha de Abertura (or_bWinOplines3d): yes; Tipo Linha Lado da Abertura (or_winOpLineType3dIn): Linha Sólida; Tipo Linha Lado da Abertura (or_iWinOpLineType3dIn): 0; Tipo Linha Lado Oposto (or_winOpLineType3dOut): Linha Sólida; Tipo Linha Lado Oposto (or_iWinOpLineType3dOut): 0; Orientação da Linha (or_winOplineStyle): Maçaneta; Orientação da Linha (or_iWinOplineStyle): 1; Caneta de Linha de Abertura em 2D/3D (or_winOpLinePen): Aberturas - Geral; Caneta de Linha de Abertura em 2D/3D (or_iWinOpLinePen): 3; Caneta Símbolo: Aberturas - Geral; Caneta Contorno Batente: Aberturas - Moldura; Caneta de Linha em Corte em Ambos os Lados da Guarnição: Aberturas - Geral; Caneta de Contorno Folha: Aberturas - Geral; Linha Contorno Parede (gs_wcont_line): Desligado; Linha Contorno Parede (iWallContourLine): 1; Tipo de Linha Interior Contorno Parede: 4; Tipo de Linha Exterior Contorno Parede: 4; Linha Interna Tracejada de Projeção Parede: 4; Linha Externa Tracejada de Projeção Parede: 4; Linha Contorno Luz Lateral Parede (gs_wcont_line_sl): Ambos Lados; Linha Contorno Luz Lateral Parede (iWallContourLineSl): 4; Tipo Linha Interior Contorno Luz Lateral Parede: 1; Tipo Linha Exterior Contorno Luz Lateral Parede: 1; Linha Interna Tracejada Projeção Parede Sobre Luz Lateral: 4; Linha Externa Tracejada Projeção Parede Sobre Luz Lateral: 4; Caneta Linha Contorno Parede: Aberturas - Geral; Tramas Usadas: yes; Tipo Trama Batente: Trama Vazia; Caneta Trama Batente: Aberturas - Fundo de Trama; Caneta Fundo Trama Batente: Fundos - Cor 1; Tipo Trama Folha: Ar (Vazio); Caneta Trama Folha: Aberturas - Fundo de Trama; Caneta Trama Fundo Folha: Fundos - Cor 1; Tipo de Trama do Símbolo Hermético: Trama Sólida; Caneta da Trama do Símbolo Hermético: Geral - Geral; Caneta de Fundo da Trama do Símbolo Hermético: Geral - Geral; Tipo Trama do Símbolo da Porta em Planta: Trama Vazia; Caneta da Trama do Símbolo da Porta em Planta: Fundos - Cor 1; Caneta de Fundo da Trama do Símbolo da Porta em Planta: Transparent; Tipo Trama Símbolo em Planta da Luz Lateral: Trama Vazia; Caneta Trama Símbolo em Planta da Luz Lateral: Fundos - Cor 1; Caneta Fundo Trama Símbolo em Planta da Luz Lateral: Fundos - Cor 1; Tipo de Linha de Degrau e Peitoril: 1; Pena de Contorno da Seção da Soleira: Aberturas - Geral; Tipo de Trama da Soleira em Corte: Trama Vazia; Caneta da Trama da Soleira em Corte: Fundos - Cor 1; Caneta da Trama de Fundo Seção Soleira: Fundos - Cor 1; Caneta de Vista e 3D da Peitoril: Geral - Geral; Caneta de Contorno de Corte Peitoril: Geral - Geral; Tipo de Trama Corte Peitoril: Trama Vazia; Caneta Trama do Parapeito em Corte: Fundos - Cor 1; Caneta de Fundo de Trama de Seção do Peitoril: Fundos - Cor 1; Caneta de Contorno Isolamento Seção: Geral - Geral; Tipo de Trama do Isolamento da Seção: Isolamento 2; Caneta Trama Isolamento Seção: Geral - Geral; Caneta da Trama de Fundo Isolamento Seção: Fundos - Cor 1; Caneta de Vista e 3D do Peitoril Interno: Geral - Geral; Caneta de Contorno Seção Peitoril Interno: Geral - Geral; Tipo de Trama do Peitoril Interno em Corte: Trama Vazia; Caneta Trama do Peitoril Interno em Corte: Fundos - Cor 1; Caneta Trama de Fundo do Peitoril Interno em Corte: Fundos - Cor 1; Tipo de Trama de Guarnição Int.: Trama Vazia; Caneta de Trama de Guarnição Int: Aberturas - Fundo de Trama; Caneta de Fundo de Trama de Guarnição Int: Fundos - Cor 1; Tipo de Trama de Guarnição Ext: Trama Vazia; Caneta de Trama de Guarnição Ext: Aberturas - Fundo de Trama; Caneta de Fundo de Trama de Guarnição Ext: Fundos - Cor 1; Tipo de Trama de Seção do Arco: Trama Vazia; Caneta da Trama da Seção do Arco: Fundos - Cor 1; Caneta de Fundo de Trama de Seção do Arco: Fundos - Cor 1; Tipo de Trama do Corte do Perfil da Ventilação: Ar (Vazio); Caneta da Trama do Corte do Perfil da Ventilação: Fundos - Cor 1; Caneta do Fundo da Trama do Corte do Perfil da Ventilação: Fundos - Cor 1; Tipo de Linha de Símbolo Quebra-Sol: 1; Caneta da Linha em Corte do Quebra-Sol: Geral - Geral; 3D/Caneta das Linhas não Cortadas no Corte: Aberturas - Geral; Tipo da Trama de Corte Quebra-Sol (gs_sunShade_cutFillType): Trama Vazia; Tipo da Trama de Corte Quebra-Sol (gs_sunShade_cutFillPen): Geral - Geral; Caneta da Trama do Fundo Corte Quebra-Sol: Window Background; Tipo Trama Isolamento Quebra-Sol: Trama Vazia; Caneta da Trama Isolamento Quebra-Sol: Geral - Geral; Caneta do Fundo Isolamento Quebra-Sol: Window Background; Tipo de Trama de Não-Cortado: Trama Vazia; Caneta da Trama de Não-Cortado: Elementos 2D - Geral; Caneta de Fundo da Trama Não-Cortado: Fundos - Cor 1; Valores Lado de Abertura (gs_opside_list): Pessoal; Valores Lado de Abertura (gs_opside_list_m): 0; Junção Elementos Batente (gs_SashText_typ): Travessa Sobrepõe Montante; Junção Elementos Batente (gs_SashText_typ_num): 2; Caneta Moldura: Aberturas - Geral; Caneta Folha: Aberturas - Geral; Caneta Caixilho de Vidro: Aberturas - Corte Não Estrutural; Caneta Vidro da Folha: Aberturas - Corte Não Estrutural; Caneta de Arco de Alvenaria: Paredes - Geral; Resolução Curva: 32; Sombra: yes; Superfície da Porta Uniforme: no; Batente Externo: Madeira - Pinho Granulado Horizontal; Batente Interno: Madeira - Pinho Granulado Horizontal; Folha Externa: Madeira - Pinho Granulado Horizontal; Folha Interna: Madeira - Pinho Granulado Horizontal; Folha 2: Madeira - Pinho Granulado Horizontal; Folha 3: Madeira - Pinho Granulado Horizontal; Trava: Pintura - Anthracite; Grelha Externa (gs_grill_mat): Madeira - Pinho Granulado Horizontal; Grelha Interna (gs_grill_mat2): Madeira - Pinho Granulado Horizontal; Grelha Externa (gs_leaf_grill_mat): Madeira - Pinho Granulado Horizontal; Grelha Interna (gs_leaf_grill_mat2): Madeira - Pinho Granulado Horizontal; Painel Sólido Exterior: Madeira - Pinho Granulado Horizontal; Painel Sólido Interior: Madeira - Pinho Granulado Horizontal; Caixilho de Vidro: Vidro - Simples; Folha de Vidro: Vidro - Simples; Trilho (gs_rail_mat): Metal - Ferro; Grelha Ventilação Externa: Madeira - Pinho Granulado Horizontal; Grelha Ventilação Interna: Madeira - Pinho Granulado Horizontal; Placa de Proteção: Metal - Alumínio; Superfícies Guarnição Uniformes: no; Interior Guarnição: Madeira - Pinho Granulado Horizontal; Exterior Guarnição: Madeira - Pinho Granulado Horizontal; Perfil de Ventilação: Metal - Alumínio; Painel Veneziana: Madeira - Pinho Granulado Horizontal; Moldura Painel Veneziana: Madeira - Pinho Granulado Horizontal; Caixa do Rolamento Veneziana: Metal - Aço Inoxidável; Lâminas Rolamento Veneziana: Pintura - Branco Titânio; Barras Rolamento Veneziana: Pintura - Branco Titânio; Caixa Persianas: Metal - Aço Inoxidável; Segmento Persianas: Pintura - Branco Titânio; Trilho Deslizante Veneziana: Metal - Aço Inoxidável; Soleira (gs_treshold_mat): Pedra - Granito Cinza; Soleira Metálica: Metal - Alumínio; Soleira/Peitoril (gs_sill_mat): Tijolo - Aparelho ao Comprido; Argamassa do Peitoril em Tijolo: Estuque - Branco Áspera; Peitoril Interno (gs_board_mat): Madeira - Pinho Granulado Horizontal; Maçaneta: Metal - Aço Inoxidável; Acessórios Maçaneta: Metal - Ferro; Proteção Borda Externa (matKickBoardOut): Metal - Aço Inoxidável; Proteção Borda Interna (matKickBoardIn): Metal - Aço Inoxidável; Arco de Alvenaria em Tijolo: Tijolo - Aparelho ao Comprido; Argamassa do Arco de Alvenaria: Estuque - Branco Áspera; Fecho Arco de Alvenaria: Pedra - Arenito 01; Nincho: Pintura - Óxido de Chumbo Amarelo; Etiquetas e Rótulos: 1; Mostrar Dimensões da Largura da Folha: yes; Mostrar ID Porta: no; Mostrar Texto Personalizado: yes; Texto Personalizado: <Texto Personalizado>; Sempre Legível: yes; Tipo Fonte: Arial; Tamanho Fonte: 2; Estilo Fonte: 0; Caneta Texto (iPenText): 1; Caneta Texto (penText): Geral - Geral; Porta pertence à Zona dentro da qual abre: yes; Custo: 0; Localização como: Nome do Compartimento; Área Total Envidraçada (gs_list_glassarea_tmp): 0; Substituir Área Envidraçada: yes; Área Total Envidraçada (gs_list_glassarea): 0; Perimetro Total Vidro: 0; Desempenho Ar Livre (mm2/l/m): 0; Tipo de Grupo (FM_Type): Outros; Tipo de Grupo (iFMType): 25; Peso Objeto: 0; Unidade Peso Objeto: kg; Definição Orientação Porta: 0; Orientação Porta: D; Fechamento de Porta: no; Tipo Painel Visor: Sem Painel Vision; Dispositivo Pega Abrir: no; Larguras de Folha da Porta: 0,77; Operação IFC (ifc_optypestr): Porta Simples Abertura Simples; Operação IFC (ifc_optype): 1
INFORMAÇÕES DO PRODUTO - Data de Aquisição: DD/MM/YYYY
CLASSIFICAÇÕES GERAIS - Transmissão Sonora: 0
ABERTURAS - Tipo de Abertura: Abrir Simples; Material: Madeira
ZONAS - Iluminação Mínima: 0; Ventilação Mínima: 0
GARANTIA - Ínicio da Garantia: DD/MM/YYYY; Fim da Garantia: DD/MM/YYYY
FABRICAÇÃO - Data de Fabricação: DD/MM/YYYY; Site do Produto: www.graphisoft.com
PISOS (Expressão) - Índice de Perda (%): 10
COBERTURA (Expressão) - Rendimento de Telha Genérica (m2): 0; Índice de Perda Telhas (%): 0; Rendimento Cumeeira (ml): 0
RODAPÉ (Expressão) - Comprimento da Barra (m): 2.4; Custo da Barra: 0
ILUMINAÇÃO E VENTILAÇÃO (Expressão) - Atende: Atende; Não Atende: Não Atende
REVESTIMENTO DE PAREDE POR ZONA (Expressão) - Número de Linhas: 10; DImensão 1: 0 mm; Dimensão 2: 0 mm; Largura do Rejunte: 10 mm; Altura do Revestimento: 100 mm
DESCRIÇÃO DA ESCADA (Expressão) - Abreviação da Largura da Escada: L; Abreviação da Altura do Espelho: E; Abreviação da Profundidade do Piso: P
ArchiCADQuantities - W/D Opening Opening Volume: 0.2805 m3; W/D Opening Nominal Volume: 0.2805 m3; W/D Opening Surface Area: 7.57474 m2; W/D Opening Nominal Surface Area: 1.87 m2; W/D Opening Width on the Reveal Side: 850 mm; W/D Opening Height on the Reveal Side: 2200 mm; W/D Opening Width on the Side Opposite to the Reveal Side: 850 mm; W/D Opening Height on the Side Opposite to the Reveal Side: 2200 mm; W/D Opening Surface Area on the Reveal Side: 1.87 m2; W/D Opening Surface Area on the Side Opposite to the Reveal Side: 1.87 m2; Nominal W/D Opening Width on the Reveal Side: 850 mm; Nominal W/D Opening Height on the Reveal Side: 2200 mm; Nominal W/D Opening Width on the Side Opposite to the Reveal Side: 850 mm; Nominal W/D Opening Height on the Side Opposite to the Reveal Side: 2200 mm; Nominal W/D Opening Surface Area on the Reveal Side: 1.87 m2; Nominal W/D Opening Surface Area on the Side Opposite to the Reveal Side: 1.87 m2; Sill/Header Value: 0 mm; W/D Nominal Sill Height: 0 mm; W/D Sill Height on the Reveal Side: 0 mm; W/D Sill Height on the Side Opposite to the Reveal Side: 0 mm; W/D Nominal Head Height: 2200 mm; W/D Head Height on the Reveal Side: 2200 mm; W/D Head Height on the Side Opposite to the Reveal Side: 2200 mm; Wall Thickness: 150 mm; Frame Thickness: 150 mm; Height: 2200 mm; Volume (Net): 0.10109 m3; Width: 850 mm; Elevation to Project Zero: 0 mm; Elevation to 1º Nível de Referência: 0 mm; Elevation to 2º Nível de Referência: 0 mm; Elevation to Sea Level: 728220 mm; Elevation to Linked/Home Story: 0 mm; Home Offset: 0 mm; Surface Area: 7.57474 m2; Top Elevation To First Reference Level: 2235 mm; Top Elevation To Home Story: 2235 mm; Top Elevation To Project Zero: 2235 mm; Top Elevation To Sea Level: 730455 mm; Top Elevation To Second Reference Level: 2235 mm; Bottom Elevation To First Reference Level: -1.95331e-14 mm; Bottom Elevation To Home Story: -1.95331e-14 mm; Bottom Elevation To Project Zero: -1.95331e-14 mm; Bottom Elevation To Sea Level: 728220 mm; Bottom Elevation To Second Reference Level: -1.95331e-14 mm; Bottom Surface Area (Net): 7.57474 m2
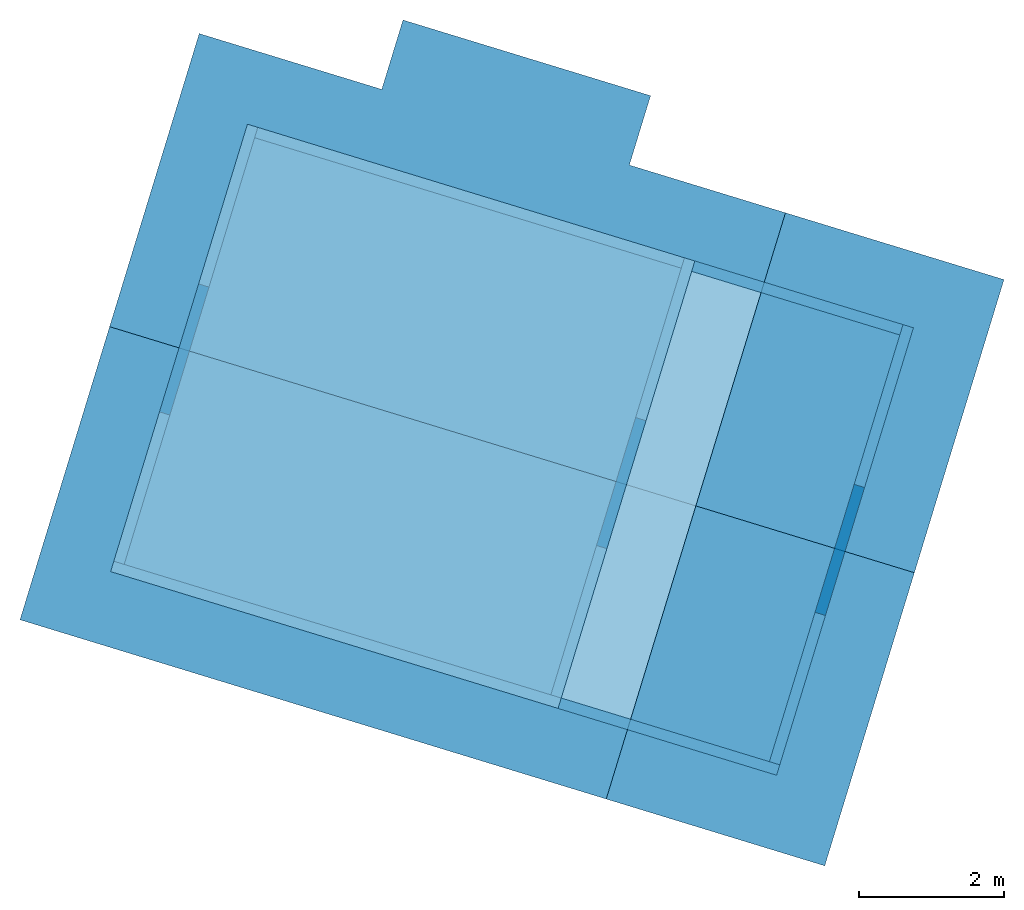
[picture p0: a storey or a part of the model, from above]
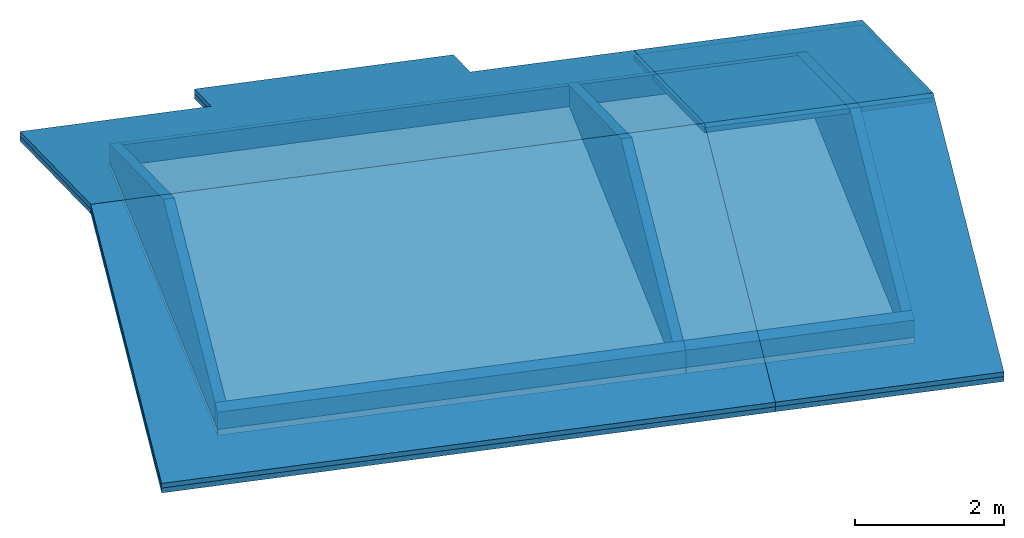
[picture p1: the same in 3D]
Properties of the parts of a building model (IFC2X3), part 3 of 7

# IfcDoor: Porta 26, Porta 04
AC_Pset_Porta_26 - Contornos Parede (0-Nenhum,1-Completo,2-Lado,3-Comprimento): 0; Pontos-Quentes 0-Nenhum,1-2D,2-3D,3-Todos: 3; Mostrar Pontos-Quentes 2D em 3D: yes; Opção de Visualização em Planta: 3; Ângulo de Posição da Abertura: 0 deg; Furo tem Superfície Lateral Parede: yes; Furos em Divisão de Superfícies são Curvos em Paredes Curvas: no; Tipo de Parede: 1; Tipo de Direção de Parede: 2; Posição de Ancoragem da Abertura: 1; Direção da Abertura: 1; Corda: no; Inserir o Valor do Parapeito da Parede: 2; Demolição / Nova Construção: 1; Novo Tipo de Trama de Parede: Bloco; Nova Caneta de Trama de Parede: Geral - Geral; Nova Caneta de Fundo de Trama de Parede: Fundos - Cor 1; Mostrar nova construção na Parede: no; Tipo de linha de demolição: 1; Mostrar parâmetro Demolição / Novo: no; Visualizar como Travessa: no; Luz Lateral (gs_SidelightTransomRelation): Abaixo da Bandeira; Luz Lateral (gs_SidelightTransomRelation_m): 1; Luz Lateral 1: no; Luz Lateral 2: no; Bandeira: no; Tolerâncias Uniformes: yes; Tamanho Nominal: 1; Definir Tamanho de Vão como Tamanho Nominal: yes; Definir Tamanho de Reentrância como Tamanho Nominal: no; Definir Tamanho de Unidade como Tamanho Nominal: no; Definir Tamanho de Saída como Tamanho Nominal: no; Definir Tamanho de Folha como Tamanho Nominal: no; Transferir Tamanho Nominal Atual para Seleção: no; Mostrar Pontos-Quentes Editáveis: yes; 2D: 1; Mostrar Face de Vão em Símbolo: 2; Indicação Simbólica da Abertura: no; 3D: 8; Direção Abertura Luz Lateral (gs_opening_dir_sl): Oposta à Folha; Direção Abertura Luz Lateral (gs_opening_dir_sl_m): 2; Batente Porta (gs_pocket_door_frame): yes; Estilo Batente (gs_frame_style): Rebaixo Samblado; Estilo Batente (gs_frame_style_m): 3; Espessura Batente=Espessura Parede: yes; Espessura Uniforme do Batente: yes; Folha Centrada: yes; Largura Uniforme Batente: yes; Estilo Batente Alterado Automaticamente: no; Número de Folhas da Porta: 4; Número de Folhas da Porta - Lado 2: 3; Estilo Painel Portas: 1; Configuração Folhas (gs_LeavesConfig): Folhas Uniformes; Configuração Folhas (gs_iLeavesConfig): 1; Posição Grelha (gs_grill_pos): Por tudo; Posição Grelha (gs_grill_pos_m): 3; Número de Paineis Verticais: 4; Número de Paineis Horizontais: 3; Nº Paineis Verticais Lado 1: 4; Nº Paineis Horizontais Lado 1: 3; Mostrar como Painel de Vidro em Símbolo: no; Mostrar Símbolo Porta Primav. Chinesa: no; Mostrar Símbolo como Painel Hermético: no; Maçaneta Abertura (gs_handle_type): Maçaneta 5; Maçaneta Abertura (gs_handle_type_m): 15; Mostrar Maçaneta em Símbolo: no; Proteção Borda Externa (bKickBoardOut): no; Proteção Borda Interna (bKickBoardIn): no; Caixilhos Uniformes: no; Tipo Abertura (gs_optype_m_05): 3; Tipo Abertura (gs_optype_m_09): 3; Tipo Abertura (gs_optype_m_02): 1; Tipo Abertura (gs_optype_m_06): 1; Tipo Abertura (gs_optype_m_10): 1; Tipo Caixilho (MullionStyle_00): Sem Grelha; Tipo Caixilho (iMullionStyle_00): 1; Tipo Caixilho (iMullionStyle_05): 1; Tipo Caixilho (iMullionStyle_09): 1; Tipo Caixilho (iMullionStyle_02): 1; Tipo Caixilho (iMullionStyle_06): 1; Tipo Caixilho (iMullionStyle_10): 1; Editar Ponto-quente Grelha: yes; Posição Grelha (MullionPosition): Por tudo; Posição Grelha (iMullionPosition): 3; Nº Paineis Verticais Caixilho Principal Lado 1: 4; Nº Paineis Horizontais Caixilho Principal Lado 1: 2; Nº Paineis Verticais 2 Caixilho Principal Lado 1: 4; Nº Paineis Horizontais 2 Caixilho Principal Lado 1: 2; Nº Paineis Verticais Caixilho Principal Lado 2: 4; Nº Paineis Horizontais Caixilho Principal Lado 2: 2; Nº Paineis Verticais 2 Caixilho Principal Lado 2: 4; Nº Paineis Horizontais 2 Caixilho Principal Lado 2: 2; Nº Paineis Verticais Bandeira Meio: 2; Nº Paineis Horizontais Bandeira Meio: 2; Nº Paineis Verticais 2 Bandeira Meio: 2; Nº Paineis Horizontais 2 Bandeira Meio: 2; Nº Paineis Verticais Bandeira Lado 1: 2; Nº Paineis Horizontais Bandeira Lado 1: 2; Nº Paineis Verticais 2 Bandeira Lado 1: 2; Nº Paineis Horizontais 2 Bandeira Lado 1: 2; Nº Paineis Verticais Bandeira Lado 2: 2; Nº Paineis Horizontais Bandeira Lado 2: 2; Nº Paineis Verticais 2 Bandeira Lado 2: 2; Nº Paineis Horizontais 2 Bandeira Lado 2: 2; Guarnição Externa: yes; Tipo Guarnição Externa (gs_trimtype_out): Simples; Tipo Guarnição Externa (gs_trimtype_out_int): 1; Tipo de Travessa Guarnição Externa: 1; Arquitrave Principal: yes; Tipo Arquitrave Principal: 1; Guarnição/Alizar na Superfície Externa da Parede: yes; Larguras Uniformes da Guarnição (gs_trim_outside_uniform): yes; Guarnição Interna: yes; Tipo Guarnição Interna (gs_trimtype_in): Simples; Tipo Guarnição Interna (gs_trimtype_in_int): 1; Guarnição/Alizar na Superfície Interna da Parede: yes; Larguras Uniformes da Guarnição (gs_trim_inside_uniform): yes; Soleira (bThreshold): no; Tipo de Soleira: 4; Ângulo Soleira: 3.1996 deg; Soleira Alterou Automaticamente: no; Soleira Externa - Porta: no; Peitoril - Luz Lateral Lado 1: no; Peitoril - Luz Lateral Lado 2: no; Sobredim. Peitoril: no; Tipo de Parapeito Exterior: 3; Ângulo Peitoril: 10 deg; Parapeito Curvo em Paredes Curvas: yes; Isolamento abaixo do Peitoril: yes; Usar Camada Isolamento de Parede: no; Nível Detalhe 3D Peitoril Tijolo: 1; Estilo de Peitoril Alterou Automaticamente: no; Peitoril Interno - Luz Lateral Lado 1: no; Peitoril Interno - Luz Lateral Lado 2: no; Peitoril Interno - Porta: no; Ângulo Peitoril Int.: 0 deg; Peitoril Int. Curvado em Paredes Curvas: yes; Peitoril Int. em Paredes Poligonais: 1; Ventilação Natural: no; Tipo Ventilação Natural: 2; Quebra-Sol: no; Tipo Quebra-Sol: 1; Tipos de Quebra-Sol Ativados: 126; Número de Paineis: 2; Número de Paineis 2: 1; Posição Painel (gs_shutter_panelPos): Simétrico; Posição Painel (gs_shutter_iPanelPos): 1; Altura Automática Veneziana: yes; Batente Extra: no; Tipo Cobertura (gs_slidingShutter_cover): Perfil-Z; Tipo Cobertura (gs_slidingShutter_iCover): 1; Direção de Empilham. (gs_foldingShutter_stacking): Dentro; Direção de Empilham. (gs_foldingShutter_iStacking): 1; Abrir em 3D: yes; Ângulo de abertura 3D: 180 deg; Mostrar Símbolo 2D: yes; Mostrar Linhas de Abertura no Símbolo: no; Tipo Painel (gs_shutPanel_type): Estilo 1; Tipo Painel (gs_shutPanel_iType): 1; Largura Base Batente Diferente: no; Largura Automática Veneziana: yes; Ângulo Grelha Ventilação: 30 deg; Nº Vãos Horiz.: 5; Nº Vãos Vert.: 8; Posição Rolamento Veneziana (gs_shutRoll_placement): Na Fachada; Posição Rolamento Veneziana (gs_shutRoll_iPlacement): 1; Tipo Caixa (gs_shutRoll_boxType): Rectangular; Tipo Caixa (gs_shutRoll_iBoxType): 1; Posição Grade (gs_shutRoll_railPos): Em Guarnição; Posição Grade (gs_shutRoll_iRailPos): 1; Mostrar Guarnição Atrás do Quebra-Sol (gs_shutRoll_showCasingBehind): no; Isolamento Atrás da Caixa (gs_shutRoll_cutWallBehind): no; Incluir Altura na Altura do Vão da Parede: no; Ângulo de Topo da Caixa: 10 deg; Largura Caixa Original (gs_shutRoll_boxDefaultSize): Largura Face de Vão; Largura Caixa Original (gs_shutRoll_iBoxDefaultSize): 1; Colocação Persianas (gs_shutLam_placement): Fixada na Fachada; Colocação Persianas (gs_shutLam_iPlacement): 1; Isolamento Atrás da Caixa (gs_shutLam_cutWallBehind): no; Caixa Aberta: yes; Trilho (gs_shutLam_bRail): yes; Posição Grade (gs_shutLam_railPos): Em Guarnição; Posição Grade (gs_shutLam_iRailPos): 1; Mostrar Guarnição Atrás do Quebra-Sol (gs_shutLam_showCasingBehind): no; Ângulo Rotação das Lamelas (gs_shutLam_rotation): 45 deg; Ângulo Rotação das Lamelas (gs_shutLam2_rotation): 45 deg; Arco de Alvenaria (bMasonryArch): no; Arco de Alvenaria (gs_masonry_arch_int): 2; Tipo de Arco de Alvenaria (gs_masonry_arch_structure): Arco de Reboco; Tipo de Arco de Alvenaria (gs_masonry_arch_structure_int): 1; Arco no Topo: yes; Nicho abaixo do Arco: yes; Ângulo de Plano do Arco: 75 deg; Superfícies dos Nichos Personalizados: no; Tipo de Requadro (gs_reveal_type_new): Requadro Reto - Borda; Tipo de Requadro (gs_reveal_type_int): 1; Tipo de Requadro Base (gs_reveal_type_bottom): Requadro Reto; Tipo de Requadro Base (gs_reveal_type_bottom_int): 2; Definir Profund. Montante no Lado: 1; Profundidade Uniforme: yes; Tipo de Requadro Exterior: Requadro Reto; Tipo de Requadro (gs_reveal_doubleOuterTypeInt): 0; Tipo de Requadro Interior: Requadro Reto; Tipo de Requadro (gs_reveal_doubleInnerTypeInt): 0; Ângulo Lado 2: 20 deg; Ângulo Lado: 20 deg; Ângulo do Topo: 20 deg; Ângulo da Base: 20 deg; Ângulo Exterior Lado 2: 20 deg; Ângulo Exterior Lado: 20 deg; Ângulo Ext. Lado Superior: 20 deg; Ângulo Ext. Lado Inferior: 20 deg; Grade abaixo Folhas: no; Trilho (gs_door_rail_ext): Off; Trilho (gs_door_rail_ext_m): 1; Usar Componente de Acabamento: no; Auto Ligagem da Face Interna da Argamassa: yes; Ligar Face Interna da Argamassa: 0; Auto Ligagem da face Externa da Argamassa: yes; Ligar Face Externa da Argamassa: 0; Dimensionável em 2D: no; Mostrar em 3D: no; Tipo de Fechamento (gs_closure_type): Sem Fechamento; Tipo de Fechamento (gs_closure_type_int): 1; Dobrar Camada no Lado (gs_cavity_side): Ambas; Dobrar Camada no Lado (iCavityClosureSide): 1; No. de Camadas: 1; Numerar a partir de (gs_nTurnDir): Face externa; Numerar a partir de (iCavityClosureTurnDir): 1; Colocar Fechamento no Lado 1: yes; Colocar Fechamento no Lado 2: yes; Colocar Fechamento no Topo: no; Colocar Fechamento na Base: no; Colocar Fechamento para Camada: 1; Colocar Fechamento do Lado (gs_cc_dutch_ClosureToSide): 1; Fenda na Camada Externa: yes; Dobrar Camada para Encerram.: no; Inserir Camada de Isolamento: yes; Mostrar Camada de Isolamento: yes; Caneta de Contorno (gs_penJoint): Aberturas - Corte Não Estrutural; Tipo Linha Contorno (gs_ltJoint): 1; Tipo de Trama (gs_fillJoint): Isolamento 2; Caneta da Trama (gs_penJointFg): Geral - Geral; Caneta do Fundo da Trama (gs_penJointBg): Elementos 2D - Desenhos; Superfície Personalizada: no; Superfície: Madeira - Pinho Granulado Horizontal; Caneta de Contorno (gs_penPlug): Aberturas - Corte Não Estrutural; Tipo Linha Contorno (gs_ltPlug): 1; Tipo de Trama (gs_fillPlug): Isolamento 2; Caneta da Trama (gs_penPlugFg): Geral - Geral; Caneta do Fundo da Trama (gs_penPlugBg): Elementos 2D - Desenhos; Lado Ombreira Editado: 1; Lado Parede Editado: 1; Número de Camada Editado: 1; Camada que Dobra: no; Considerar Camada como Reboco: no; Espessura da Camada que Dobra: 1; Orientação Trama: 1; Linha Separa Camada que Dobra: no; Caneta Linha Separação: Geral - Geral; Último Lado Selecionado: no; Método de Fechamento Alterado Automaticamente: no; Conexão no Lado 1: no; Conexão no Lado 2: no; Conexão em Cima: no; Tipo Abertura (gs_leaf_optype): Preso Lateral; Tipo Abertura (gs_leaf_optype_m): 1; Abertura Painel Final Lado 1: no; Abertura Painel Final Lado 2: no; Ângulo Abertura 2D: 90 deg; Ângulo Abertura em 2D no Lado 2: 90 deg; Ângulo Abertura em 3D: 0 deg; Ângulo Abertura Terminação Painel em 3D Lado 2: 0 deg; Ângulo de Abertura Caixilho Principal Lado 1 (openingAngle_05): 0 deg; Ângulo de Abertura Caixilho Principal Lado 1 (openingAngle2_05): 0 deg; Ângulo de Abertura Caixilho Principal Lado 2 (openingAngle_09): 0 deg; Ângulo de Abertura Caixilho Principal Lado 2 (openingAngle2_09): 0 deg; Ângulo de Abertura Bandeira Meio (openingAngle_02): 0 deg; Ângulo de Abertura Bandeira Meio (openingAngle2_02): 0 deg; Ângulo de Abertura Bandeira Lado 1 (openingAngle_06): 0 deg; Ângulo de Abertura Bandeira Lado 1 (openingAngle2_06): 0 deg; Ângulo Abertura Bandeira Lado 2 (openingAngle_10): 0 deg; Ângulo Abertura Bandeira Lado 2 (openingAngle2_10): 0 deg; Tipo de Linha Duplo Sentido: 4; Substituir OVM para Visual. Simbólica 2D: no; Tipo Linha Abertura: 1; Forma da Linha de Abertura (or_SwingType): Curva; Forma da Linha de Abertura (or_iSwingType): 1; Forma da Linha de Abertura (or_SlidingType): Nenhum; Forma da Linha de Abertura (or_iSlidingType): 0; Mostrar Linha da Vidraça em 2D: yes; Caneta da Linha da Vidraça em 2D (or_iGlazingLinePen): 3; Caneta da Linha da Vidraça em 2D (or_glazingLinePen): Aberturas - Geral; Substituir OVM para Projeções 3D da Porta: no; Mostrar Linha de Abertura (or_bOplines3d): yes; Tipo Linha Lado da Abertura (or_opLineType3dIn): Linha Sólida; Tipo Linha Lado da Abertura (or_iOpLineType3dIn): 0; Tipo Linha Lado Oposto (or_opLineType3dOut): Linha Sólida; Tipo Linha Lado Oposto (or_iOpLineType3dOut): 0; Orientação da Linha (or_oplineStyle): Maçaneta; Orientação da Linha (or_iOplineStyle): 1; Caneta de Linha de Abertura em 2D/3D (or_opLinePen): Aberturas - Geral; Caneta de Linha de Abertura em 2D/3D (or_iOpLinePen): 3; Substituir OVM para Projeções 3D Luz Lateral/Bandeira: no; Mostrar Linha de Abertura (or_bWinOplines3d): yes; Tipo Linha Lado da Abertura (or_winOpLineType3dIn): Linha Sólida; Tipo Linha Lado da Abertura (or_iWinOpLineType3dIn): 0; Tipo Linha Lado Oposto (or_winOpLineType3dOut): Linha Sólida; Tipo Linha Lado Oposto (or_iWinOpLineType3dOut): 0; Orientação da Linha (or_winOplineStyle): Maçaneta; Orientação da Linha (or_iWinOplineStyle): 1; Caneta de Linha de Abertura em 2D/3D (or_winOpLinePen): Aberturas - Geral; Caneta de Linha de Abertura em 2D/3D (or_iWinOpLinePen): 3; Caneta Símbolo: Aberturas - Geral; Caneta Contorno Batente: Aberturas - Moldura; Caneta de Linha em Corte em Ambos os Lados da Guarnição: Aberturas - Geral; Caneta de Contorno Folha: Aberturas - Geral; Linha Contorno Parede (gs_wcont_line): Desligado; Linha Contorno Parede (iWallContourLine): 1; Tipo de Linha Interior Contorno Parede: 4; Tipo de Linha Exterior Contorno Parede: 4; Linha Interna Tracejada de Projeção Parede: 4; Linha Externa Tracejada de Projeção Parede: 4; Linha Contorno Luz Lateral Parede (gs_wcont_line_sl): Ambos Lados; Linha Contorno Luz Lateral Parede (iWallContourLineSl): 4; Tipo Linha Interior Contorno Luz Lateral Parede: 1; Tipo Linha Exterior Contorno Luz Lateral Parede: 1; Linha Interna Tracejada Projeção Parede Sobre Luz Lateral: 4; Linha Externa Tracejada Projeção Parede Sobre Luz Lateral: 4; Caneta Linha Contorno Parede: Aberturas - Geral; Tramas Usadas: yes; Tipo Trama Batente: Trama Vazia; Caneta Trama Batente: Aberturas - Fundo de Trama; Caneta Fundo Trama Batente: Fundos - Cor 1; Tipo Trama Folha: Ar (Vazio); Caneta Trama Folha: Aberturas - Fundo de Trama; Caneta Trama Fundo Folha: Fundos - Cor 1; Tipo de Trama do Símbolo Hermético: Trama Sólida; Caneta da Trama do Símbolo Hermético: Geral - Geral; Caneta de Fundo da Trama do Símbolo Hermético: Geral - Geral; Tipo Trama do Símbolo da Porta em Planta: Trama Vazia; Caneta da Trama do Símbolo da Porta em Planta: Fundos - Cor 1; Caneta de Fundo da Trama do Símbolo da Porta em Planta: Transparent; Tipo Trama Símbolo em Planta da Luz Lateral: Trama Vazia; Caneta Trama Símbolo em Planta da Luz Lateral: Fundos - Cor 1; Caneta Fundo Trama Símbolo em Planta da Luz Lateral: Fundos - Cor 1; Tipo de Linha de Degrau e Peitoril: 1; Pena de Contorno da Seção da Soleira: Aberturas - Geral; Tipo de Trama da Soleira em Corte: Trama Vazia; Caneta da Trama da Soleira em Corte: Fundos - Cor 1; Caneta da Trama de Fundo Seção Soleira: Fundos - Cor 1; Caneta de Vista e 3D da Peitoril: Geral - Geral; Caneta de Contorno de Corte Peitoril: Geral - Geral; Tipo de Trama Corte Peitoril: Trama Vazia; Caneta Trama do Parapeito em Corte: Fundos - Cor 1; Caneta de Fundo de Trama de Seção do Peitoril: Fundos - Cor 1; Caneta de Contorno Isolamento Seção: Geral - Geral; Tipo de Trama do Isolamento da Seção: Isolamento 2; Caneta Trama Isolamento Seção: Geral - Geral; Caneta da Trama de Fundo Isolamento Seção: Fundos - Cor 1; Caneta de Vista e 3D do Peitoril Interno: Geral - Geral; Caneta de Contorno Seção Peitoril Interno: Geral - Geral; Tipo de Trama do Peitoril Interno em Corte: Trama Vazia; Caneta Trama do Peitoril Interno em Corte: Fundos - Cor 1; Caneta Trama de Fundo do Peitoril Interno em Corte: Fundos - Cor 1; Tipo de Trama de Guarnição Int.: Trama Vazia; Caneta de Trama de Guarnição Int: Aberturas - Fundo de Trama; Caneta de Fundo de Trama de Guarnição Int: Fundos - Cor 1; Tipo de Trama de Guarnição Ext: Trama Vazia; Caneta de Trama de Guarnição Ext: Aberturas - Fundo de Trama; Caneta de Fundo de Trama de Guarnição Ext: Fundos - Cor 1; Tipo de Trama de Seção do Arco: Trama Vazia; Caneta da Trama da Seção do Arco: Fundos - Cor 1; Caneta de Fundo de Trama de Seção do Arco: Fundos - Cor 1; Tipo de Trama do Corte do Perfil da Ventilação: Ar (Vazio); Caneta da Trama do Corte do Perfil da Ventilação: Fundos - Cor 1; Caneta do Fundo da Trama do Corte do Perfil da Ventilação: Fundos - Cor 1; Tipo de Linha de Símbolo Quebra-Sol: 1; Caneta da Linha em Corte do Quebra-Sol: Geral - Geral; 3D/Caneta das Linhas não Cortadas no Corte: Aberturas - Geral; Tipo da Trama de Corte Quebra-Sol (gs_sunShade_cutFillType): Trama Vazia; Tipo da Trama de Corte Quebra-Sol (gs_sunShade_cutFillPen): Geral - Geral; Caneta da Trama do Fundo Corte Quebra-Sol: Window Background; Tipo Trama Isolamento Quebra-Sol: Trama Vazia; Caneta da Trama Isolamento Quebra-Sol: Geral - Geral; Caneta do Fundo Isolamento Quebra-Sol: Window Background; Tipo de Trama de Não-Cortado: Trama Vazia; Caneta da Trama de Não-Cortado: Elementos 2D - Geral; Caneta de Fundo da Trama Não-Cortado: Fundos - Cor 1; Valores Lado de Abertura (gs_opside_list): Pessoal; Valores Lado de Abertura (gs_opside_list_m): 0; Junção Elementos Batente (gs_SashText_typ): Travessa Sobrepõe Montante; Junção Elementos Batente (gs_SashText_typ_num): 2; Caneta Moldura: Aberturas - Geral; Caneta Folha: Aberturas - Geral; Caneta Caixilho de Vidro: Aberturas - Corte Não Estrutural; Caneta Vidro da Folha: Aberturas - Corte Não Estrutural; Caneta de Arco de Alvenaria: Paredes - Geral; Resolução Curva: 32; Sombra: yes; Superfície da Porta Uniforme: no; Batente Externo: Madeira - Pinho Granulado Horizontal; Batente Interno: Madeira - Pinho Granulado Horizontal; Folha Externa: Madeira - Pinho Granulado Horizontal; Folha Interna: Madeira - Pinho Granulado Horizontal; Folha 2: Madeira - Pinho Granulado Horizontal; Folha 3: Madeira - Pinho Granulado Horizontal; Trava: Pintura - Anthracite; Grelha Externa (gs_grill_mat): Madeira - Pinho Granulado Horizontal; Grelha Interna (gs_grill_mat2): Madeira - Pinho Granulado Horizontal; Grelha Externa (gs_leaf_grill_mat): Madeira - Pinho Granulado Horizontal; Grelha Interna (gs_leaf_grill_mat2): Madeira - Pinho Granulado Horizontal; Painel Sólido Exterior: Madeira - Pinho Granulado Horizontal; Painel Sólido Interior: Madeira - Pinho Granulado Horizontal; Caixilho de Vidro: Vidro - Simples; Folha de Vidro: Vidro - Simples; Trilho (gs_rail_mat): Metal - Ferro; Grelha Ventilação Externa: Madeira - Pinho Granulado Horizontal; Grelha Ventilação Interna: Madeira - Pinho Granulado Horizontal; Placa de Proteção: Metal - Alumínio; Superfícies Guarnição Uniformes: no; Interior Guarnição: Madeira - Pinho Granulado Horizontal; Exterior Guarnição: Madeira - Pinho Granulado Horizontal; Perfil de Ventilação: Metal - Alumínio; Painel Veneziana: Madeira - Pinho Granulado Horizontal; Moldura Painel Veneziana: Madeira - Pinho Granulado Horizontal; Caixa do Rolamento Veneziana: Metal - Aço Inoxidável; Lâminas Rolamento Veneziana: Pintura - Branco Titânio; Barras Rolamento Veneziana: Pintura - Branco Titânio; Caixa Persianas: Metal - Aço Inoxidável; Segmento Persianas: Pintura - Branco Titânio; Trilho Deslizante Veneziana: Metal - Aço Inoxidável; Soleira (gs_treshold_mat): Pedra - Granito Cinza; Soleira Metálica: Metal - Alumínio; Soleira/Peitoril (gs_sill_mat): Tijolo - Aparelho ao Comprido; Argamassa do Peitoril em Tijolo: Estuque - Branco Áspera; Peitoril Interno (gs_board_mat): Madeira - Pinho Granulado Horizontal; Maçaneta: Metal - Aço Inoxidável; Acessórios Maçaneta: Metal - Ferro; Proteção Borda Externa (matKickBoardOut): Metal - Aço Inoxidável; Proteção Borda Interna (matKickBoardIn): Metal - Aço Inoxidável; Arco de Alvenaria em Tijolo: Tijolo - Aparelho ao Comprido; Argamassa do Arco de Alvenaria: Estuque - Branco Áspera; Fecho Arco de Alvenaria: Pedra - Arenito 01; Nincho: Pintura - Óxido de Chumbo Amarelo; Etiquetas e Rótulos: 1; Mostrar Dimensões da Largura da Folha: yes; Mostrar ID Porta: no; Mostrar Texto Personalizado: yes; Texto Personalizado: <Texto Personalizado>; Sempre Legível: yes; Tipo Fonte: Arial; Tamanho Fonte: 2; Estilo Fonte: 0; Caneta Texto (iPenText): 1; Caneta Texto (penText): Geral - Geral; Porta pertence à Zona dentro da qual abre: yes; Custo: 0; Localização como: Nome do Compartimento; Localização: Banho; Área Total Envidraçada (gs_list_glassarea_tmp): 0; Substituir Área Envidraçada: yes; Área Total Envidraçada (gs_list_glassarea): 0; Perimetro Total Vidro: 0; Desempenho Ar Livre (mm2/l/m): 0; Tipo de Grupo (FM_Type): Outros; Tipo de Grupo (iFMType): 25; Peso Objeto: 0; Unidade Peso Objeto: kg; Definição Orientação Porta: 0; Orientação Porta: E; Fechamento de Porta: no; Tipo Painel Visor: Sem Painel Vision; Dispositivo Pega Abrir: no; Larguras de Folha da Porta: 0,77; Operação IFC (ifc_optypestr): Porta Simples Abertura Simples; Operação IFC (ifc_optype): 1
ArchiCADProperties - Reveal Dimensions: 0,85×2,20; Wallhole Dimensions: 0,85×2,20; Unit Dimensions: 0,85×2,20; Egress Dimensions: 0,75×2,15; Leaf Dimensions: 0,77×2,16; Nominal W x H Size: 0,85×2,20; Nominal W x H x T Size: 0,85×2,20×0,15; Wall Structure: Bloco de Concreto - Estrutural; Marker Text: <Texto Personal.>; Orientation: E; Opening Library Part Name: Porta 26; Opening Side Fill Index: Trama Vazia; Element ID: Porta 04; Hotlink and Element ID: Porta 04; Layer: CDHU-Parede; Library Part Name: Porta 26; Building Material / Composite / Profile / Fill: Trama Vazia; Fill Type: Trama Vazia; Related Zone Name: Banho; Related Zone Number: 04; Locked: no; Home Story Name: Terreo; Home Story Number: 0; Element Type: Door; Parent ID: Parede 02; Surfaces (All): Metal - Aço Inoxidável; Madeira - Pinho Granulado Horizontal; Metal - Ferro; From Zone: Hall; From Zone Number: 05; To Zone: Banho; To Zone Number: 04; Design Option Name: Main Model; Design Option Set Name: Main Model; Position: Interior; Show On Renovation Filter: All Relevant Filters; Structural Function: Non-Load-Bearing Element; Renovation Status: Existing; Design Option Status: Main Model; Design Option Set: Main Model
ZONAS - Iluminação Mínima: 0; Ventilação Mínima: 0
ABERTURAS - Tipo de Abertura: Abrir Simples; Material: Madeira
INFORMAÇÕES DO PRODUTO - Data de Aquisição: DD/MM/YYYY
ILUMINAÇÃO E VENTILAÇÃO (Expressão) - Atende: Atende; Não Atende: Não Atende
PISOS (Expressão) - Índice de Perda (%): 10
RODAPÉ (Expressão) - Comprimento da Barra (m): 2.4; Custo da Barra: 0
COBERTURA (Expressão) - Rendimento de Telha Genérica (m2): 0; Índice de Perda Telhas (%): 0; Rendimento Cumeeira (ml): 0
REVESTIMENTO DE PAREDE POR ZONA (Expressão) - Número de Linhas: 10; DImensão 1: 0 mm; Dimensão 2: 0 mm; Largura do Rejunte: 10 mm; Altura do Revestimento: 100 mm
ESTRUTURA (Expressão) - Custo por Volume (m3): 0
EXPRESSÕES DE TEXTO (Expressão) - Localização do Produto no Projeto: Projeto: Casa Térrea IsoladaLocal: Piso: Terreo Cômodo: Banho; ID de Aberturas com Master ID: 04Porta 04; ID Dinâmico por Classificação: Porta -Porta 04
DESCRIÇÃO DA ESCADA (Expressão) - Abreviação da Largura da Escada: L; Abreviação da Altura do Espelho: E; Abreviação da Profundidade do Piso: P
AC_Equantity_Porta_26 - Largura: 850 mm; Altura: 2200 mm; Dimensão Z: 1000 mm; Nível da Base: 1000 mm; Nível do Topo: 0 mm; Altura Peitoril ao Piso Atual: 0 mm; Abertura para o Núcleo da Parede: 0 mm; Nova Largura Direita da Trama de Parede: 150 mm; Nova Largura Esquerda da Trama de Parede: 150 mm; Altura Ombro: 1840 mm; Luz Lateral com 1 Largura (gs_sidelight_width_right): 0 mm; Luz Lateral com 1 Largura (gs_sidelight_width_right_half): 150 mm; Luz Lateral com 1 Largura (gs_sidelight_width_right_orig): 300 mm; Luz Lateral com 1 Altura de Soleira: 0 mm; Luz Lateral com 2 Larguras (gs_sidelight_width_left): 0 mm; Luz Lateral com 2 Larguras (gs_sidelight_width_left_half): 300 mm; Luz Lateral com 2 Larguras (gs_sidelight_width_left_orig): 600 mm; Luz Lateral com 2 Alturas de Soleira: 0 mm; Altura Bandeira: 300 mm; Distância Eixo Pivot: 275 mm; Tolerância Lateral 1: 0 mm; Tolerância Lateral 1 Inferior: 0 mm; Tolerância Base Luz Lateral Base1: 0 mm; Tolerância Lateral 2: 0 mm; Tolerância Lateral 2 Inferior: 0 mm; Tolerância Base 2 Luz Lateral: 0 mm; Tolerância Superior: 0 mm; Tolerância Inferior: 0 mm; Largura de Vão: 850 mm; Altura de Vão: 2200 mm; Largura Face de Vão: 850 mm; Altura Face de Vão: 2200 mm; Largura Unidade: 850 mm; Altura Unidade: 2200 mm; Largura Saída: 750 mm; Altura Saída: 2150 mm; Largura Nominal da Folha: 770 mm; Altura Nominal da Folha: 2160 mm; Espessura Batente: 115 mm; Espessura Interior Moldura: 115 mm; Afastam. Folha: 0 mm; Largura Batente: 50 mm; Batente Sobredimensionado: 10 mm; Espessura do Batente Externo: 10 mm; Largura Moldura Lado 1: 40 mm; Largura Moldura Meio Lado 1: 40 mm; Largura Moldura Inferior Lado 1: 40 mm; Largura Batente Lado 2: 40 mm; Largura Moldura Meio Lado 2: 40 mm; Largura Moldura Inferior Lado 2: 40 mm; Largura Moldura Bandeira (gs_frame_width_transom): 40 mm; Largura Batente Cimo: 40 mm; Espessura Porta de Paragem: 32 mm; Largura Porta de Paragem: 16 mm; Largura Rebaixo: 10 mm; Profundidade do Rebaixo da folha em 3D: 30 mm; Largura do Rebaixo da Luz Lateral e Bandeira: 10 mm; Profund. de Rebaixo da Luz Lateral e Bandeira: 18 mm; Largura Nominal da Folha no Lado 1: 360 mm; Espessura Folha: 30 mm; Largura Batente Folha Lateral: 100 mm; Largura Moldura Folha Direita: 100 mm; Largura Moldura Folha Esquerda: 100 mm; Largura Batente Folha Inferior: 200 mm; Largura Batente Folha Superior: 100 mm; Largura Folha Interna: 25 mm; Recorte inferior da folha: 0 mm; Largura Grelha (gs_grid_w): 12 mm; Espessura Grelha (gs_grid_thk): 25 mm; Espessura Vidro: 12 mm; Altura Maçaneta: 1000 mm; Posição Maçaneta: 50 mm; Altura Proteção Borda: 100 mm; Altura Divisão Horizontal Luz Lateral Lado 1: 900 mm; Altura Divisão Horizontal Luz Lateral Lado 2: 900 mm; Altura Divisão Horizontal Bandeira Meio: 900 mm; Altura Divisão Horizontal Bandeira Lado 1: 900 mm; Altura Divisão Horizontal Bandeira Lado 2: 900 mm; Espessura Batente Luz Lateral e Bandeira: 44 mm; Largura Moldura Bandeira (gs_sash_width): 67 mm; Largura batente Painel Lateral: 67 mm; Largura Grelha (gw): 20 mm; Espessura Grelha (gth): 25 mm; Largura Divisão Luz Lateral: 40 mm; Espessura Divisão Luz Lateral: 100 mm; Largura Arquitrave Principal: 20 mm; Largura Lado 1 (gs_tw_right_out): 70 mm; Largura Lado 2 (gs_tw_left_out): 50 mm; Largura Topo (gs_tw_top_out): 50 mm; Espessura de Parede (gs_trim_thk_out): 19 mm; Espessura na Abertura da Parede (gs_trim_width_out): 25 mm; Paralelas (gs_trim_offs_out): 15 mm; Bordo (gs_trim_jambext_nosing_out): 50 mm; Saliência Superior (gs_trimov_top_left_out): 0 mm; Saliência Superior (gs_trimov_top_right_out): 0 mm; Largura Lado 1 (gs_tw_right_in): 70 mm; Largura Lado 2 (gs_tw_left_in): 50 mm; Largura Topo (gs_tw_top_in): 50 mm; Espessura de Parede (gs_trim_thk_in): 19 mm; Espessura na Abertura da Parede (gs_trim_width_in): 25 mm; Paralelas (gs_trim_offs_in): 15 mm; Bordo (gs_trim_jambext_nosing_in): 50 mm; Saliência Superior (gs_trimov_top_left_in): 0 mm; Saliência Superior (gs_trimov_top_right_in): 0 mm; Espessura Soleira: 12 mm; Largura Soleira: 10 mm; Espessura Externa Soleira: 5.80738 mm; Testeira Externa Soleira: 10 mm; Avanço Soleira Interna: 10 mm; Saliência Lateral Externo: 0 mm; Saliência Lateral Interno: 0 mm; Espessura Peitoril: 100 mm; Espessura Lateral da Frente Peitoril: 15 mm; Elevação Peitoril: 5 mm; Recobrimento Goteira Peitoril: 20 mm; Largura Goteira Peitoril: 30 mm; Testeira Peitoril: 45 mm; Avanço Lateral Peitoril 1: 0 mm; Avanço Lateral Peitoril 2: 0 mm; Inclinação do Parapeito: 35 mm; Largura Topo Parapeito: 10 mm; Altura Topo Peitoril: 10 mm; Inclin. Peitoril da Parede: 0 mm; Profund. Vão Posterior (gs_sill_holeDepthBehind): 0 mm; Largura Peitoril: 80 mm; Espessura do Tijolo (gs_brick_sill_br_thk): 65 mm; Espessura de Argamassa (gs_brick_sill_mort_thk): 15 mm; Largura Peitoril Int.: 100 mm; Espessura Peitoril Int.: 25 mm; Peitoril Int. Arredondado: 30 mm; Avanço Lateral Peitoril Interno 1: 0 mm; Avanço Lateral Peitoril Interno 2: 0 mm; Inclinação do Parapeito Int.: 0 mm; Altura Perfil: 65 mm; Espessura Perfil: 110 mm; Altura Painel: 2088 mm; Afast. Interior: 20 mm; Profund. Fechamento: 0 mm; Largura Batente Extra: 40 mm; Espess. Batente Extra: 30 mm; Largura Barra:: 30 mm; Comprim. Vara Suspensa: 20 mm; Raio Vara Suspensa: 5 mm; Distância Painel: 6 mm; Saliência Exterior: 0 mm; Largura Painel Interior: 120 mm; Comprim. Abertura 3D: 1500 mm; Comprim. Fechado 3D: 0 mm; Comprimento 1 Abertura 3D: 560 mm; Comprimento 2 Abertura 3D: 140 mm; Altura Abertura 3D: 1500 mm; Altura Fechado 3D: 0 mm; Espessura Painel: 50 mm; Largura Estrutura Painel: 50 mm; Largura Moldura Inferior: 50 mm; Largura Painel: 388 mm; Espess. de Enchimento de Painel: 10 mm; Espessura da Veneziana: 10 mm; Largura Grelha Ventilação: 40 mm; Largura Divisor Moldura Horiz.: 50 mm; Largura de Divisor Moldura Vert.: 50 mm; Raio do Vão: 10 mm; Largura Bordo Vertical: 100 mm; Largura Estrutura Z: 50 mm; Espessura Estrutura Z: 25 mm; Espess. Placas Verticais: 25 mm; Espess. Placas Horizontais: 25 mm; Largura Aprox. Placas Verticais: 80 mm; Largura Aprox. Placas Horizontais: 115 mm; Altura Caixa (gs_shutRoll_boxHeight): 200 mm; Profund. Caixa (gs_shutRoll_boxWidth): 150 mm; Afast. Caixa Esq.: 0 mm; Afast. Caixa Dir.: 0 mm; Profund. Anteparos: 72.5 mm; Distância da Parede (gs_shutRoll_distFromWall): 0 mm; Distância da Padieira (gs_shutRoll_distFromHead): 0 mm; Largura da Ripa: 50 mm; Altura Caixa (gs_shutLam_boxHeight): 200 mm; Profund. Caixa (gs_shutLam_boxWidth): 150 mm; Largura Capa: 0 mm; Distância da Parede (gs_shutLam_distFromWall): 0 mm; Distância da Padieira (gs_shutLam_distFromHead): 0 mm; Largura Segmento (gs_shutLam_segmentWidth): 60 mm; Altura Caixa (gs_shutLam2_boxHeight): 60 mm; Largura Caixa: 60 mm; Distância da Janela: 60 mm; Distância da Padieira (gs_shutLam2_distFromHead): 60 mm; Altura do Eixo da Caixa da Padieira: 0 mm; Largura Segmento (gs_shutLam2_segmentWidth): 60 mm; Distância entre Arco e Porta: 0 mm; Arco Alvenaria Avanço Lado 1: 0 mm; Arco Alvenaria Avanço Lado 2: 0 mm; Espelho do Arco de Alvenaria: 30 mm; Projeção do Arco de Alvenaria: 0 mm; Altura do Arco de Alvenaria: 250 mm; Profundidade do Arco de Alvenaria: 120 mm; Profund. Vão Posterior (gs_masonry_arch_rearHoleDepth): 0 mm; Espessura do Tijolo (gs_masonry_arch_brick_thk): 65 mm; Espessura de Argamassa (gs_masonry_arch_mort_thk): 10 mm; Largura Fecho: 100 mm; Sobredimensão Fecho: 0 mm; Projeção Fecho: 10 mm; Profund. Face de Vão (gs_wido_sill): 0 mm; Profund. Face de Vão (AC_wido_sill): 0 mm; Profund. Ombreira: 60 mm; Profund. Ombreira Lado 2: 60 mm; Profund. Ombreira Inferior Lado 1: 60 mm; Profund. Ombreira Inferior Lado 2: 60 mm; Profund. Ombreira Interior Lado 2 (gs_reveal_splayed_innerLeft): 60 mm; Profund. Ombreira Interior (gs_reveal_splayed_innerRight): 60 mm; Profund. Ombreira Interior (gs_reveal_double_innerRight): 60 mm; Profund. Ombreira Interior Lado 2 (gs_reveal_double_innerLeft): 60 mm; Profund. Ombreira Interior Inferior Lado 1: 60 mm; Profund. Ombreira Interior Inferior Lado 2: 60 mm; Profund. do Topo: 60 mm; Profundidade Peitoril: 60 mm; Profund. Peitoril Lado 1: 60 mm; Profund. Peitoril Lado 2: 60 mm; Profundidade Padieira Interior (gs_reveal_splayed_innerTop): 60 mm; Profundidade Peitoril Interior (gs_reveal_splayed_innerBottom): 0 mm; Profundidade Padieira Interior (gs_reveal_double_innerTop): 60 mm; Profundidade Peitoril Interior (gs_reveal_double_innerBottom): 0 mm; Profund. Peitoril Interior Lado 1: 0 mm; Profund. Peitoril Interior Lado 2: 0 mm; Profund. Batente Exterior: 80 mm; Limite Espess. Reboco: 40 mm; Distância de Camada do Encerram.: 0 mm; Largura do Fecho: 38 mm; Espessura do Fecho: 100 mm; Espessura da Camada: 25 mm; Espessura do Perfil: 150 mm; Espessura Personal.: 15 mm; Saliência Camada para Espess. Batente: 0 mm; Sobred. Abertura Esquerda: 0 mm; Sobred. Direita Abertura: 0 mm; Sobred. Topo Abertura: 0 mm; Sobred. Base Abertura: 0 mm; Largura Abertura 3D: 0 mm; Largura Abertura em 3D no Lado 2: 0 mm; Largura Abertura 2D: 0 mm; Largura Abertura em 2D no Lado 2: 0 mm; Distância Abertura 1 Caixilho Principal Lado 1: 0 mm; Distância Abertura 2 Caixilho Principal Lado 1: 0 mm; Distância Abertura 1 Caixilho Principal Lado 2: 0 mm; Distância Abertura 2 Caixilho Principal Lado 2: 0 mm; Distância Abertura 1 Bandeira Meio: 0 mm; Distância Abertura 2 Bandeira Meio: 0 mm; Distância Abertura 1 Bandeira Lado 1: 0 mm; Distância Abertura 2 Bandeira Lado 1: 0 mm; Distância Abertura 1 Bandeira Lado 2: 0 mm; Distância Abertura 2 Bandeira Lado 2: 0 mm; Largura 2 de Lado de Abertura: 200 mm; Largura 1 de Lado de Abertura: 100 mm; Profund. Lado de Abertura: 1000 mm; Largura 2 de Lado Oposto: 100 mm; Largura 1 de Lado Oposto: 100 mm; Profund. Lado Oposto: 1000 mm; Sobred. Abertura Esq. AC: 0 mm; Sobred. Abertura Dir. AC: 0 mm; Sobred. Padieira AC: 0 mm; Sobred. Abertura Base AC: 0 mm; Espessura Moldura Real: 150 mm; ID Afastamento X: 0 mm; ID Afastamento Y: 0 mm; Afastamento X Texto Personalizado: 0 mm; Afastasmento Y Texto Personalizado: 0 mm; Afastamento X Largura da Folha: 0 mm; Afastamento Y Largura da Folha: 0 mm
BaseQuantities - Height: 2200 mm; Width: 850 mm; Perimeter: 6100 mm; Area: 1.87 m2; Volume: 0.10109 m3; Depth: 150 mm; NetVolume: 0.10109 m3
ArchiCADQuantities - W/D Opening Opening Volume: 0.2805 m3; W/D Opening Nominal Volume: 0.2805 m3; W/D Opening Surface Area: 7.57474 m2; W/D Opening Nominal Surface Area: 1.87 m2; W/D Opening Width on the Reveal Side: 850 mm; W/D Opening Height on the Reveal Side: 2200 mm; W/D Opening Width on the Side Opposite to the Reveal Side: 850 mm; W/D Opening Height on the Side Opposite to the Reveal Side: 2200 mm; W/D Opening Surface Area on the Reveal Side: 1.87 m2; W/D Opening Surface Area on the Side Opposite to the Reveal Side: 1.87 m2; Nominal W/D Opening Width on the Reveal Side: 850 mm; Nominal W/D Opening Height on the Reveal Side: 2200 mm; Nominal W/D Opening Width on the Side Opposite to the Reveal Side: 850 mm; Nominal W/D Opening Height on the Side Opposite to the Reveal Side: 2200 mm; Nominal W/D Opening Surface Area on the Reveal Side: 1.87 m2; Nominal W/D Opening Surface Area on the Side Opposite to the Reveal Side: 1.87 m2; Sill/Header Value: 0 mm; W/D Nominal Sill Height: 0 mm; W/D Sill Height on the Reveal Side: 0 mm; W/D Sill Height on the Side Opposite to the Reveal Side: 0 mm; W/D Nominal Head Height: 2200 mm; W/D Head Height on the Reveal Side: 2200 mm; W/D Head Height on the Side Opposite to the Reveal Side: 2200 mm; Wall Thickness: 150 mm; Frame Thickness: 150 mm; Height: 2200 mm; Volume (Net): 0.10109 m3; Width: 850 mm; Elevation to Project Zero: 0 mm; Elevation to 1º Nível de Referência: 0 mm; Elevation to 2º Nível de Referência: 0 mm; Elevation to Sea Level: 728220 mm; Elevation to Linked/Home Story: 0 mm; Home Offset: 0 mm; Surface Area: 7.57474 m2; Top Elevation To First Reference Level: 2235 mm; Top Elevation To Home Story: 2235 mm; Top Elevation To Project Zero: 2235 mm; Top Elevation To Sea Level: 730455 mm; Top Elevation To Second Reference Level: 2235 mm; Bottom Elevation To First Reference Level: -3.10448e-14 mm; Bottom Elevation To Home Story: -3.10448e-14 mm; Bottom Elevation To Project Zero: -3.10448e-14 mm; Bottom Elevation To Sea Level: 728220 mm; Bottom Elevation To Second Reference Level: -3.10448e-14 mm; Bottom Surface Area (Net): 7.57474 m2
ALVENARIAS (Expressão) - Espessura da Argamassa: 10 mm
Component Quantities - Component, Component Volume (Net): 0.10109 m3; Component, Component Volume (Gross): 0.10109 m3

# IfcFurnishingElement: Bancada 26, FX01
In: 01
Description: Bancada da cozinha; Classification: Mobília (Classificação ARCHICAD); 3E 56 08 Equipamentos móveis conectados às instalações hidráulicas (NBR 15965-5 3E); 2C 78 06 Pias (NBR 15965-4 2C)
AC_Pset_Bancada_26 - Mostrar Pontos-Quentes 2D em 3D: no; Definir Programa: no; Altura Armário: 4; Profundidade do Armário: 7; Canto Direito: 1; Ângulo Borda Direita: 45 deg; Canto Esquerdo: 1; Ângulo Borda Esquerda: 45 deg; Testeira Frente: yes; Testeira Posterior: no; Testeira Esquerda: yes; Testeira Direita: yes; Junções Testeira: 1; Rodabanca Esquerda: no; Rodabanca Direita: no; Frontão (bBackSplash): yes; Número de Cubas: 1; Tipo de Cuba: 2; Assentamento Cuba: 2; Símbolo Cuba: 1; Posicionamento Cuba: 1; Tipo de Torneira (tapGroup): Misturador Nível Simples; Tipo de Torneira (iTapGroup): 1; Estilo de Torneira (gs_tap_type): Estilo 3; Estilo de Torneira (gs_tap_type_m): 7; Tipo de Símbolo de Torneira (TapSymbol): Detalhado; Tipo de Símbolo de Torneira (TapSymbol_m): 2; Nível de Detalhe em 2D: 1; Linhas de contorno nas Bordas Laterais: 4; Trama Desenho da Bancada: yes; Caneta Cuba: Objetos - Geral; Caneta de Contorno: Objetos - Geral; Tipo de Trama: Trama Vazia; Caneta da Trama: Window Background; Caneta do Fundo da Trama: Transparent; Nível de Detalhe em 3D: 1; Resolução: 12; Sombra: yes; Caneta Contorno 3D: Objetos - Geral; Bancada: Pedra - Mármore Carrara Branco; Frontão (splashSurface): Pedra - Mármore Carrara Branco; Saia (skirtSurface): Pedra - Mármore Carrara Branco; Cuba: Cerâmica - Porcelana; Torneira: Metal - Aço Inoxidável; Conexão: Metal - Aço Inoxidável; Usar Superfície de Sistema: no; Sistemas de Superfície: 0; Conexão Água Quente 1: yes; Tipo de Ferramenta (ConToolType_1): 2; Sistema MEP (ConSystem_1): Não-Definido; Tipo de Forma (ConType_1): Círculo; Tipo de Conexão (ConConnectorType_1): Welded; Conexão Água Fria 1: yes; Tipo de Ferramenta (ConToolType_2): 2; Sistema MEP (ConSystem_2): Não-Definido; Tipo de Forma (ConType_2): Círculo; Tipo de Conexão (ConConnectorType_2): Welded; Conexão Esgoto 1: yes; Tipo de Ferramenta (ConToolType_3): 2; Sistema MEP (ConSystem_3): Não-Definido; Tipo de Forma (ConType_3): Círculo; Tipo de Conexão (ConConnectorType_3): Welded; Conexão Água Quente 2: yes; Tipo de Ferramenta (ConToolType_4): 2; Sistema MEP (ConSystem_4): Não-Definido; Tipo de Forma (ConType_4): Círculo; Tipo de Conexão (ConConnectorType_4): Welded; Conexão Água Fria 2: yes; Tipo de Ferramenta (ConToolType_5): 2; Sistema MEP (ConSystem_5): Não-Definido; Tipo de Forma (ConType_5): Círculo; Tipo de Conexão (ConConnectorType_5): Welded; Conexão Esgoto 2: yes; Tipo de Ferramenta (ConToolType_6): 2; Sistema MEP (ConSystem_6): Não-Definido; Tipo de Forma (ConType_6): Círculo; Tipo de Conexão (ConConnectorType_6): Welded; Número de Bancadas: 1; Número de Testeiras: 3; Número de Rodabancas: 1; Subtipo IFC: 0; Tipo Pré-definido IFC: 0; Área: 0; Volume: 0; Custo: 0; Tipo de Grupo (FM_Type): Equipamento AVAC; Tipo de Grupo (iFMType): 12; Peso Objeto: 0; Unidade Peso Objeto: kg; Número de Conexões: 6
GARANTIA - Ínicio da Garantia: DD/MM/YYYY; Fim da Garantia: DD/MM/YYYY
ZONAS - Iluminação Mínima: 0; Ventilação Mínima: 0
FABRICAÇÃO - Data de Fabricação: DD/MM/YYYY; Site do Produto: www.graphisoft.com
ArchiCADProperties - Rotation Angle: 270 deg; Surface: GENERAL; Element ID: FX01; Hotlink and Element ID: FX01; Layer: CDHU-Mobiliario Fixo; Library Part Name: Bancada 26; Building Material / Composite / Profile / Fill: Trama Vazia; Fill Type: Trama Vazia; Colliding Zones: Sala / Cozinha; Related Zone Name: Sala / Cozinha; Related Zone Number: 01; Locked: no; Home Story Name: Terreo; Home Story Number: 0; Element Type: Object; Parent ID: FX01; Surfaces (All): Pedra - Mármore Carrara Branco; Metal - Aço Inoxidável; Cerâmica - Porcelana; Design Option Name: Main Model; Design Option Set Name: Main Model; Position: Interior; Show On Renovation Filter: All Relevant Filters; Structural Function: Non-Load-Bearing Element; Renovation Status: Existing; Design Option Status: Main Model; Design Option Set: Main Model
INFORMAÇÕES DO PRODUTO - Data de Aquisição: DD/MM/YYYY
PISOS (Expressão) - Índice de Perda (%): 10
REVESTIMENTO DE PAREDE POR ZONA (Expressão) - Número de Linhas: 10; DImensão 1: 0 mm; Dimensão 2: 0 mm; Largura do Rejunte: 10 mm; Altura do Revestimento: 100 mm
ILUMINAÇÃO E VENTILAÇÃO (Expressão) - Atende: Atende; Não Atende: Não Atende
COBERTURA (Expressão) - Rendimento de Telha Genérica (m2): 0; Índice de Perda Telhas (%): 0; Rendimento Cumeeira (ml): 0
ESTRUTURA (Expressão) - Custo por Volume (m3): 0
EXPRESSÕES DE TEXTO (Expressão) - Localização do Produto no Projeto: Projeto: Casa Térrea IsoladaLocal: Piso: Terreo Cômodo: Sala / Cozinha; ID de Aberturas com Master ID: 01FX01; ID Dinâmico por Classificação: Mobília -FX01
RODAPÉ (Expressão) - Comprimento da Barra (m): 2.4; Custo da Barra: 0
DESCRIÇÃO DA ESCADA (Expressão) - Abreviação da Largura da Escada: L; Abreviação da Altura do Espelho: E; Abreviação da Profundidade do Piso: P
AC_Equantity_Bancada_26 - Dimensão 1: 1200 mm; Dimensão 2: 600 mm; Altura: 230 mm; Nível da Base: 670 mm; Nível do Topo: 900 mm; Altura Armário: 870 mm; Profund. Tampo: 600 mm; Largura Tampo: 1200 mm; Espessura Tampo: 30 mm; Afastamento no Canto Direito: 0 mm; Afastamento no Canto Esquerdo: 0 mm; Altura Testeira: 200 mm; Espessura Testeira: 20 mm; Afastamento Testeira: 10 mm; Altura Rodabanca: 100 mm; Espessura Rodabanca: 20 mm; Largura da Cuba: 550 mm; Profundidade da Cuba: 500 mm; Distância da Banca a partir do Centro: 0 mm; Distância Cuba do Canto Direito (sinkDistX_Right): 600 mm; Distância Cuba do Canto Esquerdo (sinkDistX_Left): 600 mm; Distância Cuba da Frente: 19.05 mm; Distância Cuba do Canto Direito (rightSink_XDist): 508 mm; Distância Cuba do Canto Esquerdo (leftSink_XDist): 508 mm; Altura Torneira: 508 mm; Profundidade Nominal (ConNominalDepth_1): 25 mm; Diâmetro Exterior (ConWidth_1): 27 mm; Profundidade Exterior (ConDepth_1): 27 mm; Espessura Parede (ConWallThickness_1): 1 mm; Comprimento da Conexão (ConLength_1): 20 mm; Diãmetro Conector (ConConnectorWidth_1): 40 mm; Profundidade Conector (ConConnectorDepth_1): 0 mm; Largura Conector (ConConnectorWidth2_1): 5 mm; Posição X da Conexão (ConPosX_1): 500 mm; Posição Y da Conexão (ConPosY_1): -43.5 mm; Posição Z da Conexão (ConPosZ_1): 870 mm; Profundidade Nominal (ConNominalDepth_2): 25 mm; Diâmetro Exterior (ConWidth_2): 27 mm; Profundidade Exterior (ConDepth_2): 27 mm; Espessura Parede (ConWallThickness_2): 1 mm; Comprimento da Conexão (ConLength_2): 20 mm; Diãmetro Conector (ConConnectorWidth_2): 40 mm; Profundidade Conector (ConConnectorDepth_2): 0 mm; Largura Conector (ConConnectorWidth2_2): 5 mm; Posição X da Conexão (ConPosX_2): 700 mm; Posição Y da Conexão (ConPosY_2): -43.5 mm; Posição Z da Conexão (ConPosZ_2): 870 mm; Profundidade Nominal (ConNominalDepth_3): 40 mm; Diâmetro Exterior (ConWidth_3): 42 mm; Profundidade Exterior (ConDepth_3): 42 mm; Espessura Parede (ConWallThickness_3): 1 mm; Comprimento da Conexão (ConLength_3): 20 mm; Diãmetro Conector (ConConnectorWidth_3): 42 mm; Profundidade Conector (ConConnectorDepth_3): 0 mm; Largura Conector (ConConnectorWidth2_3): 5 mm; Posição X da Conexão (ConPosX_3): 600 mm; Posição Y da Conexão (ConPosY_3): -280.95 mm; Posição Z da Conexão (ConPosZ_3): 670 mm; Profundidade Nominal (ConNominalDepth_4): 25 mm; Diâmetro Exterior (ConWidth_4): 27 mm; Profundidade Exterior (ConDepth_4): 27 mm; Espessura Parede (ConWallThickness_4): 1 mm; Comprimento da Conexão (ConLength_4): 20 mm; Diãmetro Conector (ConConnectorWidth_4): 40 mm; Profundidade Conector (ConConnectorDepth_4): 0 mm; Largura Conector (ConConnectorWidth2_4): 5 mm; Posição X da Conexão (ConPosX_4): -100 mm; Posição Y da Conexão (ConPosY_4): -13.5 mm; Posição Z da Conexão (ConPosZ_4): -25 mm; Profundidade Nominal (ConNominalDepth_5): 25 mm; Diâmetro Exterior (ConWidth_5): 27 mm; Profundidade Exterior (ConDepth_5): 27 mm; Espessura Parede (ConWallThickness_5): 1 mm; Comprimento da Conexão (ConLength_5): 20 mm; Diãmetro Conector (ConConnectorWidth_5): 40 mm; Profundidade Conector (ConConnectorDepth_5): 0 mm; Largura Conector (ConConnectorWidth2_5): 5 mm; Posição X da Conexão (ConPosX_5): 100 mm; Posição Y da Conexão (ConPosY_5): -13.5 mm; Posição Z da Conexão (ConPosZ_5): -25 mm; Profundidade Nominal (ConNominalDepth_6): 40 mm; Diâmetro Exterior (ConWidth_6): 42 mm; Profundidade Exterior (ConDepth_6): 42 mm; Espessura Parede (ConWallThickness_6): 1 mm; Comprimento da Conexão (ConLength_6): 20 mm; Diãmetro Conector (ConConnectorWidth_6): 42 mm; Profundidade Conector (ConConnectorDepth_6): 0 mm; Largura Conector (ConConnectorWidth2_6): 5 mm; Posição X da Conexão (ConPosX_6): 0 mm; Posição Y da Conexão (ConPosY_6): -158.908 mm; Posição Z da Conexão (ConPosZ_6): -167 mm
ALVENARIAS (Expressão) - Espessura da Argamassa: 10 mm
ArchiCADQuantities - Length (A): 1200 mm; Area: 0.72 m2; Height: 230 mm; Volume (Net): 0.0278549 m3; Width: 600 mm; Elevation to Project Zero: 0 mm; Elevation to 1º Nível de Referência: 0 mm; Elevation to 2º Nível de Referência: 0 mm; Elevation to Sea Level: 728220 mm; Elevation to Linked/Home Story: 0 mm; Home Offset: 0 mm; Surface Area: 3.33037 m2; Top Elevation To First Reference Level: 1135 mm; Top Elevation To Home Story: 1135 mm; Top Elevation To Project Zero: 1135 mm; Top Elevation To Sea Level: 729355 mm; Top Elevation To Second Reference Level: 1135 mm; Bottom Elevation To First Reference Level: 650 mm; Bottom Elevation To Home Story: 650 mm; Bottom Elevation To Project Zero: 650 mm; Bottom Elevation To Sea Level: 728870 mm; Bottom Elevation To Second Reference Level: 650 mm; Survey Coordinate X: 6393.53 mm; Survey Coordinate Y: 3639.75 mm; Survey Coordinate Z: 0 mm; Top Surface Area (Net): 0.72 m2; Bottom Surface Area (Net): 3.33037 m2
SUPERFÍCIES (Mapas) - Área da Superfície da Base (Geral): 0.72 m2
Component Quantities - Component, Component Volume (Net): 0.0278549 m3; Component, Component Volume (Gross): 0.0278549 m3

# IfcFurnishingElement: Basin 27, FX02
In: 04
Description: Lavatorio banheiro; Classification: Mobília (Classificação ARCHICAD); 3E 56 08 Equipamentos móveis conectados às instalações hidráulicas (NBR 15965-5 3E); 2C 78 06 Pias (NBR 15965-4 2C)
INFORMAÇÕES DO PRODUTO - Data de Aquisição: DD/MM/YYYY
ArchiCADProperties - Rotation Angle: 90 deg; Surface: GENERAL; Element ID: FX02; Hotlink and Element ID: FX02; Layer: CDHU-Mobiliario Fixo; Library Part Name: Basin 27; Building Material / Composite / Profile / Fill: Trama Vazia; Fill Type: Trama Vazia; Colliding Zones: Banho; Related Zone Name: Banho; Related Zone Number: 04; Locked: no; Home Story Name: Terreo; Home Story Number: 0; Element Type: Object; Parent ID: FX02; Surfaces (All): Metal - Aço Inoxidável; Metal - Cromado 01; Cerâmica - Porcelana; Design Option Name: Main Model; Design Option Set Name: Main Model; Position: Interior; Show On Renovation Filter: All Relevant Filters; Structural Function: Non-Load-Bearing Element; Renovation Status: Existing; Design Option Status: Main Model; Design Option Set: Main Model
AC_Pset_Basin_27 - Basin Type (stStyle): On Pedestal; Basin Type (iStyle): 3; Show 2D Hotspots in 3D: no; Set Program: no; 3D Detail Level: 1; Support Type (suptyp): Pedestal; Support Type (iSuptyp): 1; Tap Type (tapGroup): Single Level Mixer; Tap Type (iTapGroup): 1; Tap Style (gs_tap_type): Style 1; Tap Style (gs_tap_type_m): 1; Hot Water Connection: yes; Tool Type (ConToolType_1): 2; MEP System (ConSystem_1): Undefined; Shape Type (ConType_1): Circle; Connection Type (ConConnectorType_1): Welded; Cold Water Connection: yes; Tool Type (ConToolType_2): 2; MEP System (ConSystem_2): Undefined; Shape Type (ConType_2): Circle; Connection Type (ConConnectorType_2): Welded; Waste Water Connection: yes; Tool Type (ConToolType_3): 2; MEP System (ConSystem_3): Undefined; Shape Type (ConType_3): Circle; Connection Type (ConConnectorType_3): Welded; Resolution: 12; Connection Resolution: 8; Shadow: yes; Symbol Type (gs_symbol_type): Model Based; Symbol Type (iSymbolType): 1; Enable Symbol Types: no; 2D Detail Level: 1; Tap Symbol Type (TapSymbol): Detailed; Tap Symbol Type (TapSymbol_m): 2; Contour Pen: Equipamentos - Hidrosanitário; Fill Type: Trama Vazia; Fill Pen: Fundos - Cor 1; Fill Background Pen: Fundos - Cor 1; Basin: Cerâmica - Porcelana; Tap: Metal - Cromado 01; Drain: Metal - Aço Inoxidável; Connection: Metal - Aço Inoxidável; Use System Surface: no; System Surface: Pintura - Amarelo Cádmio; Number of Connections: 3; Cost: 0; Group Type (FM_Type): Sanitation; Group Type (iFMType): 13; Area: 0; Volume: 0; Object Weight: 0; Object Weight Unit: kg
REVESTIMENTO DE PAREDE POR ZONA (Expressão) - Número de Linhas: 10; DImensão 1: 0 mm; Dimensão 2: 0 mm; Largura do Rejunte: 10 mm; Altura do Revestimento: 100 mm
ZONAS - Iluminação Mínima: 0; Ventilação Mínima: 0
GARANTIA - Ínicio da Garantia: DD/MM/YYYY; Fim da Garantia: DD/MM/YYYY
FABRICAÇÃO - Data de Fabricação: DD/MM/YYYY; Site do Produto: www.graphisoft.com
ILUMINAÇÃO E VENTILAÇÃO (Expressão) - Atende: Atende; Não Atende: Não Atende
RODAPÉ (Expressão) - Comprimento da Barra (m): 2.4; Custo da Barra: 0
ESTRUTURA (Expressão) - Custo por Volume (m3): 0
PISOS (Expressão) - Índice de Perda (%): 10
DESCRIÇÃO DA ESCADA (Expressão) - Abreviação da Largura da Escada: L; Abreviação da Altura do Espelho: E; Abreviação da Profundidade do Piso: P
COBERTURA (Expressão) - Rendimento de Telha Genérica (m2): 0; Índice de Perda Telhas (%): 0; Rendimento Cumeeira (ml): 0
EXPRESSÕES DE TEXTO (Expressão) - Localização do Produto no Projeto: Projeto: Casa Térrea IsoladaLocal: Piso: Terreo Cômodo: Banho; ID de Aberturas com Master ID: 04FX02; ID Dinâmico por Classificação: Mobília -FX02
ArchiCADQuantities - Length (A): 400 mm; Area: 0.12 m2; Height: 850 mm; Volume (Net): 0.0106837 m3; Width: 300 mm; Elevation to Project Zero: 0 mm; Elevation to 1º Nível de Referência: 0 mm; Elevation to 2º Nível de Referência: 0 mm; Elevation to Sea Level: 728220 mm; Elevation to Linked/Home Story: 0 mm; Home Offset: 0 mm; Surface Area: 0.897804 m2; Top Elevation To First Reference Level: 945.546 mm; Top Elevation To Home Story: 945.546 mm; Top Elevation To Project Zero: 945.546 mm; Top Elevation To Sea Level: 729166 mm; Top Elevation To Second Reference Level: 945.546 mm; Bottom Elevation To First Reference Level: -20 mm; Bottom Elevation To Home Story: -20 mm; Bottom Elevation To Project Zero: -20 mm; Bottom Elevation To Sea Level: 728200 mm; Bottom Elevation To Second Reference Level: -20 mm; Survey Coordinate X: 6317.7 mm; Survey Coordinate Y: 2878.67 mm; Survey Coordinate Z: 0 mm; Top Surface Area (Net): 0.12 m2; Bottom Surface Area (Net): 0.897804 m2
Component Quantities - Component, Component Volume (Net): 0.0106837 m3; Component, Component Volume (Gross): 0.0106837 m3
SUPERFÍCIES (Mapas) - Área da Superfície da Base (Geral): 0.12 m2
AC_Equantity_Basin_27 - Basin Width: 400 mm; Basin Depth: 300 mm; Height: 850 mm; Top Height: 850 mm; Bottom Level: 0 mm; Top Level: 850 mm; Tap Height: 950 mm; Tap X Position: 0 mm; Tap Y Position: 0 mm; Tap Z Position: 0 mm; Nominal Depth (ConNominalDepth_1): 25 mm; Outer Diameter (ConWidth_1): 27 mm; Outer Depth (ConDepth_1): 27 mm; Wall Thickness (ConWallThickness_1): 1 mm; Connection Length (ConLength_1): 20 mm; Connector Diameter (ConConnectorWidth_1): 40 mm; Connector Depth (ConConnectorDepth_1): 0 mm; Connector Width (ConConnectorWidth2_1): 5 mm; Connection Position X (ConPosX_1): -50 mm; Connection Position Y (ConPosY_1): 0 mm; Connection Position Z (ConPosZ_1): 805 mm; Nominal Depth (ConNominalDepth_2): 25 mm; Outer Diameter (ConWidth_2): 27 mm; Outer Depth (ConDepth_2): 27 mm; Wall Thickness (ConWallThickness_2): 1 mm; Connection Length (ConLength_2): 20 mm; Connector Diameter (ConConnectorWidth_2): 40 mm; Connector Depth (ConConnectorDepth_2): 0 mm; Connector Width (ConConnectorWidth2_2): 5 mm; Connection Position X (ConPosX_2): 50 mm; Connection Position Y (ConPosY_2): 0 mm; Connection Position Z (ConPosZ_2): 805 mm; Nominal Depth (ConNominalDepth_3): 40 mm; Outer Diameter (ConWidth_3): 42 mm; Outer Depth (ConDepth_3): 42 mm; Wall Thickness (ConWallThickness_3): 1 mm; Connection Length (ConLength_3): 20 mm; Connector Diameter (ConConnectorWidth_3): 42 mm; Connector Depth (ConConnectorDepth_3): 0 mm; Connector Width (ConConnectorWidth2_3): 5 mm; Connection Position X (ConPosX_3): 0 mm; Connection Position Y (ConPosY_3): -167.5 mm; Connection Position Z (ConPosZ_3): 0 mm; Minimal Space in Front: 1100 mm; Minimal Space on Side 1: 170 mm; Minimal Space on Side 2: 220 mm
ALVENARIAS (Expressão) - Espessura da Argamassa: 10 mm

# IfcFurnishingElement: Bed 01 27 (2)
In: 03
Description: Cama de Solteiro; Classification: Mobília (Classificação ARCHICAD); 3E 56 04 Elementos de mobiliário (NBR 15965-5 3E); 2C 68 26 Equipamentos e mobiliário residencial (NBR 15965-4 2C)
ArchiCADProperties - Rotation Angle: 180 deg; Surface: GENERAL; Layer: CDHU-Mobiliario; Library Part Name: Bed 01 27; Building Material / Composite / Profile / Fill: Trama Vazia; Fill Type: Trama Vazia; Colliding Zones: Dormitorio 02; Related Zone Name: Dormitorio 02; Related Zone Number: 03; Locked: no; Home Story Name: Terreo; Home Story Number: 0; Element Type: Object; Surfaces (All): Madeira - Pinho Granulado Horizontal; Pintura - Branco Polido; Design Option Name: Main Model; Design Option Set Name: Main Model; Position: Interior; Show On Renovation Filter: All Relevant Filters; Structural Function: Non-Load-Bearing Element; Renovation Status: Existing; Design Option Status: Main Model; Design Option Set: Main Model
FABRICAÇÃO - Data de Fabricação: DD/MM/YYYY; Site do Produto: www.graphisoft.com
AC_Pset_Bed_01_27 - Support Type (stBedType): Frame; Support Type (iBedType): 1; 3D Detail Level: 1; Frame Type: 1; Headboard (bHeadboard): yes; Headboard (hb): On Rear Side; Headboard (iHeadboard): 3; Headboard Style (hboard_type): Style 2; Headboard Style (hboard_type_m): 2; Headboard Edge: no; Leg Style (stBedLegType): Style 1; Leg Style (iBedLegType): 1; Pillow (pw): no; 2D Symbol Type (styp): Type 2; 2D Detail Level: 6; 2D Symbol Type (iSymbolType): 2; Contour Pen: Objetos - Geral; Uniform Fill Settings: no; Fill Type Uniform: Trama Vazia; Fill Pen Uniform: Fundos - Cor 1; Fill Background Pen Uniform: Fundos - Cor 1; Fill for (fillFor): Bed; Fill for (iFillFor): 1; Fill Type Bed: Trama Vazia; Fill Pen Bed: Fundos - Cor 1; Fill Background Pen Bed: Fundos - Cor 1; Fill Type Pillow: Trama Vazia; Fill Pen Pillow: Fundos - Cor 1; Fill Background Pen Pillow: Fundos - Cor 1; Fill Type Blanket: Trama Vazia; Fill Pen Blanket: Fundos - Cor 1; Fill Background Pen Blanket: Fundos - Cor 1; Resolution: 8; Shadow: yes; Show 2D Hotspots in 3D: no; Bed Frame (frmat): Madeira - Pinho Granulado Horizontal; Leg: Madeira - Pinho Granulado Horizontal; Headboard (hbmat): Madeira - Pinho Granulado Horizontal; Mattress (mmat): Pintura - Branco Polido; Pillow (pillow_mat): Pintura - Branco Polido; Bed Frame (gs_frame_mat): Madeira - Pinho Granulado Horizontal; Mattress (gs_matrace_mat): Pintura - Bege Areia; Cost: 0; Group Type (FM_Type): Furniture; Group Type (iFMType): 16; Object Weight: 0; Object Weight Unit: kg
INFORMAÇÕES DO PRODUTO - Data de Aquisição: DD/MM/YYYY
ZONAS - Iluminação Mínima: 0; Ventilação Mínima: 0
ILUMINAÇÃO E VENTILAÇÃO (Expressão) - Atende: Atende; Não Atende: Não Atende
PISOS (Expressão) - Índice de Perda (%): 10
GARANTIA - Ínicio da Garantia: DD/MM/YYYY; Fim da Garantia: DD/MM/YYYY
REVESTIMENTO DE PAREDE POR ZONA (Expressão) - Número de Linhas: 10; DImensão 1: 0 mm; Dimensão 2: 0 mm; Largura do Rejunte: 10 mm; Altura do Revestimento: 100 mm
RODAPÉ (Expressão) - Comprimento da Barra (m): 2.4; Custo da Barra: 0
ESTRUTURA (Expressão) - Custo por Volume (m3): 0
EXPRESSÕES DE TEXTO (Expressão) - Localização do Produto no Projeto: Projeto: Casa Térrea IsoladaLocal: Piso: Terreo Cômodo: Dormitorio 02
COBERTURA (Expressão) - Rendimento de Telha Genérica (m2): 0; Índice de Perda Telhas (%): 0; Rendimento Cumeeira (ml): 0
DESCRIÇÃO DA ESCADA (Expressão) - Abreviação da Largura da Escada: L; Abreviação da Altura do Espelho: E; Abreviação da Profundidade do Piso: P
ArchiCADQuantities - Length (A): 800 mm; Area: 1.52 m2; Height: 660 mm; Volume (Net): 0.662691 m3; Width: 1900 mm; Elevation to Project Zero: 0 mm; Elevation to 1º Nível de Referência: 0 mm; Elevation to 2º Nível de Referência: 0 mm; Elevation to Sea Level: 728220 mm; Elevation to Linked/Home Story: 0 mm; Home Offset: 0 mm; Surface Area: 12.0417 m2; Top Elevation To First Reference Level: 660 mm; Top Elevation To Home Story: 660 mm; Top Elevation To Project Zero: 660 mm; Top Elevation To Sea Level: 728880 mm; Top Elevation To Second Reference Level: 660 mm; Bottom Elevation To First Reference Level: 0 mm; Bottom Elevation To Home Story: 0 mm; Bottom Elevation To Project Zero: 0 mm; Bottom Elevation To Sea Level: 728220 mm; Bottom Elevation To Second Reference Level: 0 mm; Survey Coordinate Z: 0 mm; Top Surface Area (Net): 1.52 m2; Bottom Surface Area (Net): 12.0417 m2
AC_Equantity_Bed_01_27 - Dimension 1: 800 mm; Dimension 2: 1900 mm; Height: 660 mm; Bed Height: 400 mm; Bed Frame Height (frh): 320 mm; Bed Frame Height (frhLeg): 160 mm; Frontal Headboard Height: 340 mm; Rear Headboard Height: 340 mm; Mattress Height: 120 mm; Mattress Distance from Edge: 20 mm; Fillet Radius of Mattress: 20 mm; Edge Radius of Mattress: 20 mm; Leg Height: 160 mm; Leg Width/Diameter: 50 mm; Minimal Space in Front: 500 mm; Minimal Space Width 1 on Side 1: 500 mm; Minimal Space Width 2 on Side 1: 500 mm; Minimal Space on Side 2: 500 mm; Minimal Space Length 1: 1200 mm; Minimal Space Length 2: 0 mm; Bottom Level: 1000 mm; Top Level: 0 mm
ALVENARIAS (Expressão) - Espessura da Argamassa: 10 mm
SUPERFÍCIES (Mapas) - Área da Superfície da Base (Geral): 1.52 m2
Component Quantities - Component, Component Volume (Net): 0.662691 m3; Component, Component Volume (Gross): 0.662691 m3
Name | Element ID = Hotlink and Element ID = Parent ID | ID de Aberturas com Master ID | ID Dinâmico por Classificação | Survey Coordinate X (mm) | Survey Coordinate Y (mm)
MB10 | MB10 | 03MB10 | Mobília -MB10 | 6624.08 | 118.481
MB09 | MB09 | 03MB09 | Mobília -MB09 | 4520.21 | 761.699

# IfcFurnishingElement: Bed Double 01 27, MB08
In: 02
Description: Cama de Casal; Classification: Mobília (Classificação ARCHICAD); 3E 56 04 Elementos de mobiliário (NBR 15965-5 3E); 2C 68 26 Equipamentos e mobiliário residencial (NBR 15965-4 2C)
AC_Pset_Bed_Double_01_27 - Support Type (stBedType): Frame; Support Type (iBedType): 1; 3D Detail Level: 1; Frame Type: 1; Headboard (bHeadboard): yes; Headboard (hb): On Rear Side; Headboard (iHeadboard): 3; Headboard Style (hboard_type): Style 2; Headboard Style (hboard_type_m): 2; Headboard Edge: no; Leg Style (stBedLegType): Style 1; Leg Style (iBedLegType): 1; Pillow (pw): no; 2D Detail Level: 6; 2D Symbol Type (styp): Type 2; 2D Symbol Type (iSymbolType): 2; Contour Pen: Objetos - Geral; Uniform Fill Settings: no; Fill Type Uniform: Trama Vazia; Fill Pen Uniform: Fundos - Cor 1; Fill Background Pen Uniform: Fundos - Cor 1; Fill for: Bed; Fill Type Bed: Trama Vazia; Fill Pen Bed: Fundos - Cor 1; Fill Background Pen Bed: Fundos - Cor 1; Fill Type Pillow: Trama Vazia; Fill Pen Pillow: Fundos - Cor 1; Fill Background Pen Pillow: Fundos - Cor 1; Fill Type Blanket: Trama Vazia; Fill Pen Blanket: Fundos - Cor 1; Fill Background Pen Blanket: Fundos - Cor 1; Resolution: 8; Shadow: yes; Show 2D Hotspots in 3D: no; Bed Frame (frmat): Madeira - Pinho Granulado Horizontal; Leg: Madeira - Pinho Granulado Horizontal; Headboard (hbmat): Madeira - Pinho Granulado Horizontal; Mattress (mmat): Pintura - Branco Polido; Pillow (pillow_mat): Pintura - Branco Polido; Bed Frame (gs_frame_mat): Madeira - Pinho Granulado Horizontal; Mattress (gs_matrace_mat): Pintura - Bege Areia; Cost: 0; Group Type (FM_Type): Furniture; Group Type (iFMType): 16; Object Weight: 0; Object Weight Unit: kg
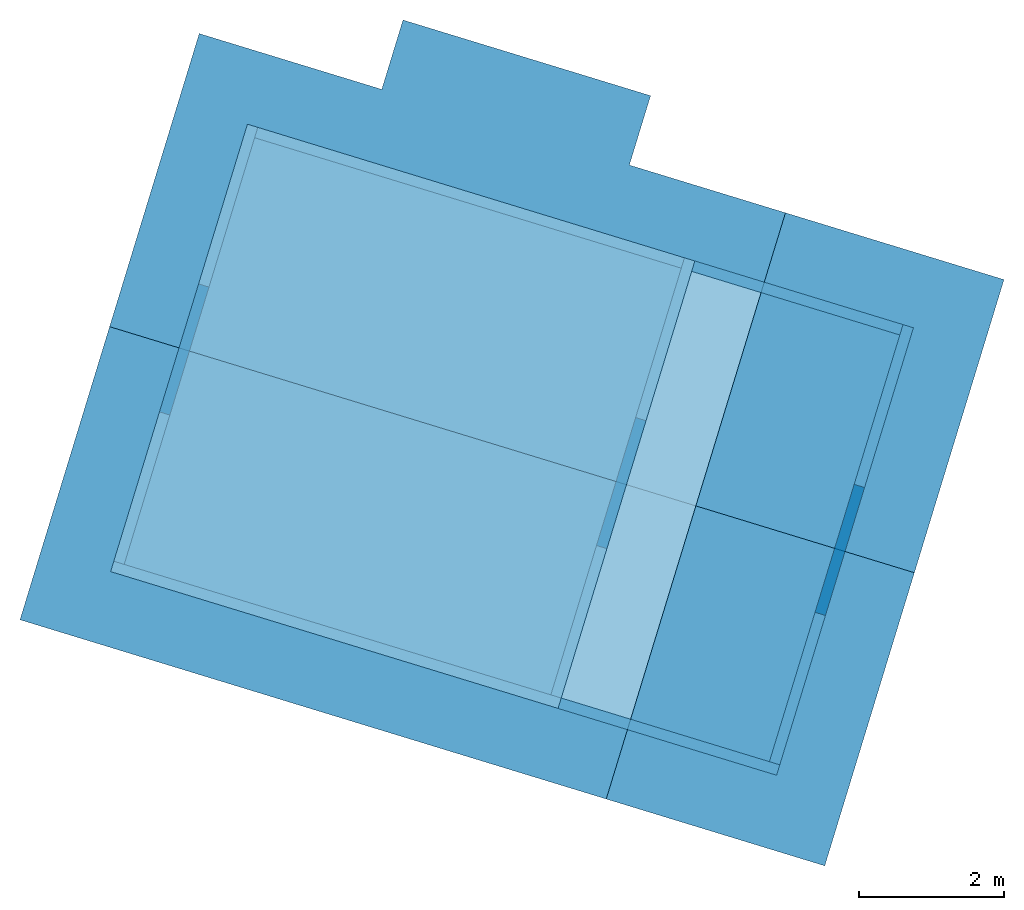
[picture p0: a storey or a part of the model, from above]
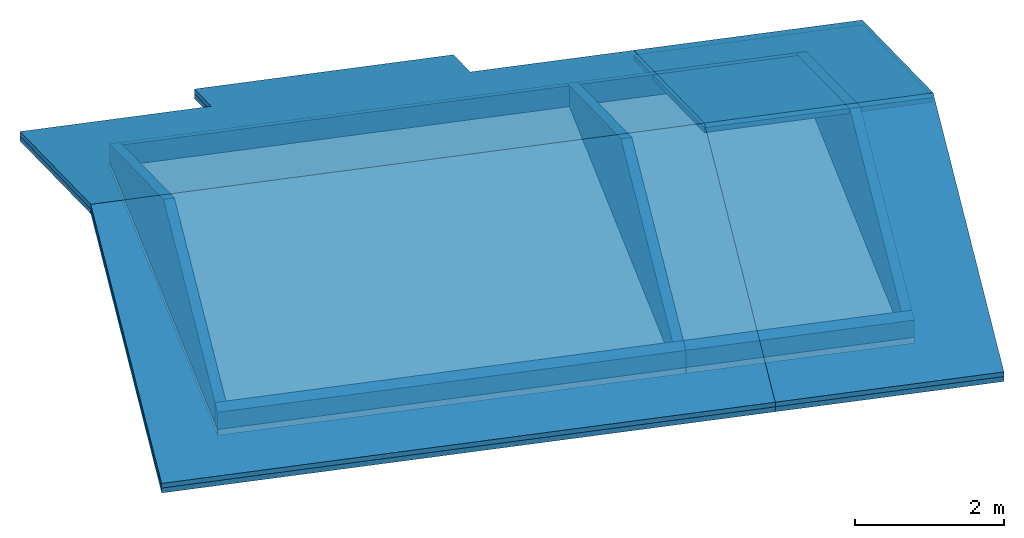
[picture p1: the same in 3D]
Properties of the parts of a building model (IFC2X3), part 4 of 7

# IfcFurnishingElement: Bed Double 01 27, MB08
ArchiCADProperties - Rotation Angle: 180 deg; Surface: GENERAL; Element ID: MB08; Hotlink and Element ID: MB08; Layer: CDHU-Mobiliario; Library Part Name: Bed Double 01 27; Building Material / Composite / Profile / Fill: Trama Vazia; Fill Type: Trama Vazia; Colliding Zones: Dormitorio 01; Related Zone Name: Dormitorio 01; Related Zone Number: 02; Locked: no; Home Story Name: Terreo; Home Story Number: 0; Element Type: Object; Parent ID: MB08; Surfaces (All): Madeira - Pinho Granulado Horizontal; Pintura - Branco Polido; Design Option Name: Main Model; Design Option Set Name: Main Model; Position: Interior; Show On Renovation Filter: All Relevant Filters; Structural Function: Non-Load-Bearing Element; Renovation Status: Existing; Design Option Status: Main Model; Design Option Set: Main Model
FABRICAÇÃO - Data de Fabricação: DD/MM/YYYY; Site do Produto: www.graphisoft.com
GARANTIA - Ínicio da Garantia: DD/MM/YYYY; Fim da Garantia: DD/MM/YYYY
INFORMAÇÕES DO PRODUTO - Data de Aquisição: DD/MM/YYYY
ZONAS - Iluminação Mínima: 0; Ventilação Mínima: 0
RODAPÉ (Expressão) - Comprimento da Barra (m): 2.4; Custo da Barra: 0
REVESTIMENTO DE PAREDE POR ZONA (Expressão) - Número de Linhas: 10; DImensão 1: 0 mm; Dimensão 2: 0 mm; Largura do Rejunte: 10 mm; Altura do Revestimento: 100 mm
PISOS (Expressão) - Índice de Perda (%): 10
ArchiCADQuantities - Length (A): 1400 mm; Area: 2.66 m2; Height: 660 mm; Volume (Net): 1.16668 m3; Width: 1900 mm; Elevation to Project Zero: 0 mm; Elevation to 1º Nível de Referência: 0 mm; Elevation to 2º Nível de Referência: 0 mm; Elevation to Sea Level: 728220 mm; Elevation to Linked/Home Story: 0 mm; Home Offset: 0 mm; Surface Area: 20.0708 m2; Top Elevation To First Reference Level: 660 mm; Top Elevation To Home Story: 660 mm; Top Elevation To Project Zero: 660 mm; Top Elevation To Sea Level: 728880 mm; Top Elevation To Second Reference Level: 660 mm; Bottom Elevation To First Reference Level: 0 mm; Bottom Elevation To Home Story: 0 mm; Bottom Elevation To Project Zero: 0 mm; Bottom Elevation To Sea Level: 728220 mm; Bottom Elevation To Second Reference Level: 0 mm; Survey Coordinate X: 2846.68 mm; Survey Coordinate Y: 1273.35 mm; Survey Coordinate Z: 0 mm; Top Surface Area (Net): 2.66 m2; Bottom Surface Area (Net): 20.0708 m2
DESCRIÇÃO DA ESCADA (Expressão) - Abreviação da Largura da Escada: L; Abreviação da Altura do Espelho: E; Abreviação da Profundidade do Piso: P
EXPRESSÕES DE TEXTO (Expressão) - Localização do Produto no Projeto: Projeto: Casa Térrea IsoladaLocal: Piso: Terreo Cômodo: Dormitorio 01; ID de Aberturas com Master ID: 02MB08; ID Dinâmico por Classificação: Mobília -MB08
COBERTURA (Expressão) - Rendimento de Telha Genérica (m2): 0; Índice de Perda Telhas (%): 0; Rendimento Cumeeira (ml): 0
ESTRUTURA (Expressão) - Custo por Volume (m3): 0
ILUMINAÇÃO E VENTILAÇÃO (Expressão) - Atende: Atende; Não Atende: Não Atende
AC_Equantity_Bed_Double_01_27 - Dimension 1: 1400 mm; Dimension 2: 1900 mm; Height: 660 mm; Bed Height: 400 mm; Bed Frame Height (frh): 320 mm; Bed Frame Height (frhLeg): 160 mm; Frontal Headboard Height: 340 mm; Rear Headboard Height: 340 mm; Mattress Height: 120 mm; Mattress Distance from Edge: 20 mm; Fillet Radius of Mattress: 20 mm; Edge Radius of Mattress: 20 mm; Leg Height: 160 mm; Leg Width/Diameter: 50 mm; Minimal Space in Front: 500 mm; Minimal Space on Side 1: 500 mm; Minimal Space on Side 2: 500 mm; Minimal Space Length: 1500 mm; Bottom Level: 1000 mm; Top Level: 0 mm
ALVENARIAS (Expressão) - Espessura da Argamassa: 10 mm
SUPERFÍCIES (Mapas) - Área da Superfície da Base (Geral): 2.66 m2
Component Quantities - Component, Component Volume (Net): 1.16668 m3; Component, Component Volume (Gross): 1.16668 m3

# IfcFurnishingElement: Coffee Table 04 27, MB04
In: 01
Description: Mesa de centro quadrada; Classification: Mobília (Classificação ARCHICAD); 3E 56 04 Elementos de mobiliário (NBR 15965-5 3E); 2C 68 26 Equipamentos e mobiliário residencial (NBR 15965-4 2C)
ArchiCADProperties - Rotation Angle: 0 deg; Surface: GENERAL; Element ID: MB04; Hotlink and Element ID: MB04; Layer: CDHU-Mobiliario; Library Part Name: Coffee Table 04 27; Building Material / Composite / Profile / Fill: Trama Vazia; Fill Type: Trama Vazia; Colliding Zones: Sala / Cozinha; Related Zone Name: Sala / Cozinha; Related Zone Number: 01; Locked: no; Home Story Name: Terreo; Home Story Number: 0; Element Type: Object; Parent ID: MB04; Surfaces (All): Madeira - Nogueira Horizontal; Metal - Ferro; Design Option Name: Main Model; Design Option Set Name: Main Model; Position: Interior; Show On Renovation Filter: All Relevant Filters; Structural Function: Non-Load-Bearing Element; Renovation Status: Existing; Design Option Status: Main Model; Design Option Set: Main Model
FABRICAÇÃO - Data de Fabricação: DD/MM/YYYY; Site do Produto: www.graphisoft.com
AC_Pset_Coffee_Table_04_27 - Mostrar Pontos-Quentes 2D em 3D: no; Caneta de Contorno: Objetos - Geral; Tipo de Trama: Trama Vazia; Caneta da Trama: Fundos - Cor 1; Caneta do Fundo da Trama: Fundos - Cor 1; Nível de Detalhe em 3D: 1; Sombra: yes; Tampo Mesa: Madeira - Nogueira Horizontal; Perna: Metal - Ferro; Custo: 0; Tipo de Grupo (FM_Type): Furniture; Tipo de Grupo (iFMType): 16; Peso Objeto: 0; Unidade Peso Objeto: kg
ALVENARIAS (Expressão) - Espessura da Argamassa: 10 mm
REVESTIMENTO DE PAREDE POR ZONA (Expressão) - DImensão 1: 0 mm; Dimensão 2: 0 mm; Largura do Rejunte: 10 mm; Altura do Revestimento: 100 mm; Número de Linhas: 10
AC_Equantity_Coffee_Table_04_27 - Largura: 600 mm; Profundidade: 600 mm; Altura: 450 mm; Espessura Tampo: 50 mm; Espessura da Perna: 25 mm; Nível da Base: 1000 mm; Nível do Topo: 0 mm; Espaço Mínimo na Frente: 600 mm; Espaço Mínimo nos Lados: 600 mm; Espaço Mínimo Atrás: 600 mm
ESTRUTURA (Expressão) - Custo por Volume (m3): 0
DESCRIÇÃO DA ESCADA (Expressão) - Abreviação da Largura da Escada: L; Abreviação da Altura do Espelho: E; Abreviação da Profundidade do Piso: P
EXPRESSÕES DE TEXTO (Expressão) - Localização do Produto no Projeto: Projeto: Casa Térrea IsoladaLocal: Piso: Terreo Cômodo: Sala / Cozinha; ID de Aberturas com Master ID: 01MB04; ID Dinâmico por Classificação: Mobília -MB04
COBERTURA (Expressão) - Rendimento de Telha Genérica (m2): 0; Índice de Perda Telhas (%): 0; Rendimento Cumeeira (ml): 0
RODAPÉ (Expressão) - Comprimento da Barra (m): 2.4; Custo da Barra: 0
GARANTIA - Ínicio da Garantia: DD/MM/YYYY; Fim da Garantia: DD/MM/YYYY
PISOS (Expressão) - Índice de Perda (%): 10
ILUMINAÇÃO E VENTILAÇÃO (Expressão) - Atende: Atende; Não Atende: Não Atende
ZONAS - Iluminação Mínima: 0; Ventilação Mínima: 0
SUPERFÍCIES (Mapas) - Área da Superfície da Base (Geral): 0.36 m2
ArchiCADQuantities - Length (A): 600 mm; Area: 0.36 m2; Height: 450 mm; Volume (Net): 0.02175 m3; Width: 600 mm; Elevation to Project Zero: 0 mm; Elevation to 1º Nível de Referência: 0 mm; Elevation to 2º Nível de Referência: 0 mm; Elevation to Sea Level: 728220 mm; Elevation to Linked/Home Story: 0 mm; Home Offset: 0 mm; Surface Area: 1.445 m2; Top Elevation To First Reference Level: 450 mm; Top Elevation To Home Story: 450 mm; Top Elevation To Project Zero: 450 mm; Top Elevation To Sea Level: 728670 mm; Top Elevation To Second Reference Level: 450 mm; Bottom Elevation To First Reference Level: 0 mm; Bottom Elevation To Home Story: 0 mm; Bottom Elevation To Project Zero: 0 mm; Bottom Elevation To Sea Level: 728220 mm; Bottom Elevation To Second Reference Level: 0 mm; Survey Coordinate X: 2084.76 mm; Survey Coordinate Y: 3942.02 mm; Survey Coordinate Z: 0 mm; Top Surface Area (Net): 0.36 m2; Bottom Surface Area (Net): 1.445 m2
INFORMAÇÕES DO PRODUTO - Data de Aquisição: DD/MM/YYYY
Component Quantities - Component, Component Volume (Net): 0.02175 m3; Component, Component Volume (Gross): 0.02175 m3

# IfcFurnishingElement: Dining Table Rectangle 27, MB05
In: 01
Description: Mesa 4 lugares com cadeiras; Classification: Mobília (Classificação ARCHICAD); 3E 56 04 Elementos de mobiliário (NBR 15965-5 3E); 2C 68 26 Equipamentos e mobiliário residencial (NBR 15965-4 2C)
ArchiCADProperties - Rotation Angle: 0 deg; Surface: GENERAL; Element ID: MB05; Hotlink and Element ID: MB05; Layer: CDHU-Mobiliario; Library Part Name: Dining Table Rectangle 27; Building Material / Composite / Profile / Fill: Trama Vazia; Fill Type: Trama Vazia; Colliding Zones: Sala / Cozinha; Related Zone Name: Sala / Cozinha; Related Zone Number: 01; Locked: no; Home Story Name: Terreo; Home Story Number: 0; Element Type: Object; Parent ID: MB05; Surfaces (All): Madeira - Pinho Granulado Horizontal; Design Option Name: Main Model; Design Option Set Name: Main Model; Position: Interior; Show On Renovation Filter: All Relevant Filters; Structural Function: Non-Load-Bearing Element; Renovation Status: Existing; Design Option Status: Main Model; Design Option Set: Main Model
INFORMAÇÕES DO PRODUTO - Data de Aquisição: DD/MM/YYYY
AC_Pset_Dining_Table_Rectangle_27 - Show 2D Hotspots in 3D: no; Chair on the Top: yes; Chair on the Bottom (bChairBottom): yes; Chair Type on the Bottom: Chairs; Chair on the Bottom (iBottomSideType): 1; Chair on the Left (bChairLeft): yes; Chair Type on the Left: Chair; Chair on the Left (iLeftSideType): 1; Chair on the Right: yes; Sizing (SizingType): by Chair and Distance; Sizing (iSizingType): 1; Number of Chairs X Direction: 1; Number of Chairs Y Direction: 1; Chair Type: 1; 2D Detail Level: 1; Symbol Type: 6; Contour Pen: Objetos - Geral; Fill Type: Trama Vazia; Fill Pen: Fundos - Cor 1; Fill Background Pen: Fundos - Cor 1; 3D Detail Level: 1; Resolution: 16; Shadow: yes; Uniform Surfaces: no; Tabletop: Madeira - Pinho Granulado Horizontal; Table Leg: Madeira - Pinho Granulado Horizontal; Chair Frame: Madeira - Pinho Granulado Horizontal; Backrest: Madeira - Pinho Granulado Horizontal; Seat: Madeira - Pinho Granulado Horizontal; Wheelchair Seat: Tecido - 01; Wheelchair Frame: Metal - Aço Inoxidável; Wheel: Pintura - Preto Marfim; Cost: 0; Group Type (FM_Type): Furniture; Group Type (iFMType): 16; Object Weight: 0; Object Weight Unit: kg
GARANTIA - Ínicio da Garantia: DD/MM/YYYY; Fim da Garantia: DD/MM/YYYY
ZONAS - Iluminação Mínima: 0; Ventilação Mínima: 0
REVESTIMENTO DE PAREDE POR ZONA (Expressão) - Número de Linhas: 10; DImensão 1: 0 mm; Dimensão 2: 0 mm; Largura do Rejunte: 10 mm; Altura do Revestimento: 100 mm
ILUMINAÇÃO E VENTILAÇÃO (Expressão) - Atende: Atende; Não Atende: Não Atende
PISOS (Expressão) - Índice de Perda (%): 10
FABRICAÇÃO - Data de Fabricação: DD/MM/YYYY; Site do Produto: www.graphisoft.com
COBERTURA (Expressão) - Rendimento de Telha Genérica (m2): 0; Índice de Perda Telhas (%): 0; Rendimento Cumeeira (ml): 0
RODAPÉ (Expressão) - Comprimento da Barra (m): 2.4; Custo da Barra: 0
ESTRUTURA (Expressão) - Custo por Volume (m3): 0
DESCRIÇÃO DA ESCADA (Expressão) - Abreviação da Largura da Escada: L; Abreviação da Altura do Espelho: E; Abreviação da Profundidade do Piso: P
AC_Equantity_Dining_Table_Rectangle_27 - Dimension 1: 1540 mm; Dimension 2: 1540 mm; Height: 850 mm; Bottom Level: 1000 mm; Top Level: 0 mm; Chair-Table Distance: -100 mm; Min. Chair-Chair Distance: 400 mm; Width per Chair: 800 mm; Depth per Chair: 650 mm; Distance next to Wheelchair: 300 mm; Additional Side Space for Wheelchair: 300 mm; Width for Wheelchair: 1100 mm; Depth for Wheelchair: 1150 mm; Real Chair Distance Horizontal: 400 mm; Real Chair Distance Vertical: 400 mm; Table Length: 800 mm; Table Half Length: 400 mm; Table Width: 800 mm; Table Half Width: 400 mm; Table Height: 750 mm; Additional Table Width: 200 mm; Table Width for Chairs: 800 mm; Tabletop Thickness: 40 mm; Tabletop Overhang X: 100 mm; Tabletop Overhang Y: 100 mm; Leg Width: 40 mm; Chair Width: 400 mm; Chair Depth: 470 mm; Chair Height: 850 mm; Seat Height: 400 mm; Wheelchair Width: 500 mm; Wheelchair Depth: 850 mm; Distance behind Chair: 280 mm; Distance behind Wheelchair: 300 mm
EXPRESSÕES DE TEXTO (Expressão) - Localização do Produto no Projeto: Projeto: Casa Térrea IsoladaLocal: Piso: Terreo Cômodo: Sala / Cozinha; ID de Aberturas com Master ID: 01MB05; ID Dinâmico por Classificação: Mobília -MB05
ArchiCADQuantities - Length (A): 1540 mm; Area: 2.3716 m2; Height: 850 mm; Volume (Net): 0.0553602 m3; Width: 1540 mm; Elevation to Project Zero: 0 mm; Elevation to 1º Nível de Referência: 0 mm; Elevation to 2º Nível de Referência: 0 mm; Elevation to Sea Level: 728220 mm; Elevation to Linked/Home Story: 0 mm; Home Offset: 0 mm; Surface Area: 5.83512 m2; Top Elevation To First Reference Level: 850 mm; Top Elevation To Home Story: 850 mm; Top Elevation To Project Zero: 850 mm; Top Elevation To Sea Level: 729070 mm; Top Elevation To Second Reference Level: 850 mm; Bottom Elevation To First Reference Level: 0 mm; Bottom Elevation To Home Story: 0 mm; Bottom Elevation To Project Zero: 0 mm; Bottom Elevation To Sea Level: 728220 mm; Bottom Elevation To Second Reference Level: 0 mm; Survey Coordinate X: 4202.86 mm; Survey Coordinate Y: 3075.59 mm; Survey Coordinate Z: 0 mm; Top Surface Area (Net): 2.3716 m2; Bottom Surface Area (Net): 5.83512 m2
ALVENARIAS (Expressão) - Espessura da Argamassa: 10 mm
Component Quantities - Component, Component Volume (Net): 0.0553602 m3; Component, Component Volume (Gross): 0.0553602 m3
SUPERFÍCIES (Mapas) - Área da Superfície da Base (Geral): 2.3716 m2

# IfcFurnishingElement: Fogão a Gás 26, MB07
In: 01
Description: Fogao a gas 4 bocas; Classification: Mobília (Classificação ARCHICAD); 3E 56 04 Elementos de mobiliário (NBR 15965-5 3E); 2C 68 26 26 26 Forno e fogão (NBR 15965-4 2C)
ILUMINAÇÃO E VENTILAÇÃO (Expressão) - Atende: Atende; Não Atende: Não Atende
ZONAS - Iluminação Mínima: 0; Ventilação Mínima: 0
GARANTIA - Ínicio da Garantia: DD/MM/YYYY; Fim da Garantia: DD/MM/YYYY
FABRICAÇÃO - Data de Fabricação: DD/MM/YYYY; Site do Produto: www.graphisoft.com
ArchiCADProperties - Rotation Angle: 270 deg; Surface: GENERAL; Element ID: MB07; Hotlink and Element ID: MB07; Layer: CDHU-Mobiliario; Library Part Name: Fogão a Gás 26; Building Material / Composite / Profile / Fill: Trama Vazia; Fill Type: Trama Vazia; Colliding Zones: Sala / Cozinha; Related Zone Name: Sala / Cozinha; Related Zone Number: 01; Locked: no; Home Story Name: Terreo; Home Story Number: 0; Element Type: Object; Parent ID: MB07; Surfaces (All): Metal - Aço Inoxidável; Vidro - Simples; Metal - Ferro; Pintura - Branco Titânio; Design Option Name: Main Model; Design Option Set Name: Main Model; Position: Interior; Show On Renovation Filter: All Relevant Filters; Structural Function: Non-Load-Bearing Element; Renovation Status: Existing; Design Option Status: Main Model; Design Option Set: Main Model
AC_Pset_Fogão_a_Gás_26 - Nível de Detalhe em 3D: 1; Frontão: no; Prateleira Forno (f_3D): no; Tipo de Placa de Cozinha (CooktopType): Tipo 4; Tipo de Placa de Cozinha (CooktopType_m): 9; Nível de Detalhe em 2D: 1; Caneta de Contorno: Objetos - Geral; Tipo de Trama: Trama Vazia; Caneta da Trama: Fundos - Cor 1; Caneta do Fundo da Trama: Fundos - Cor 1; Visualização Texto: no; Texto: Fg; Caneta Texto: Texto - Rótulos; Tipo Fonte: Arial; Estilo de Fonte em Negrito: no; Estilo de Fonte em Itálico: no; Estilo de Fonte Sublinhado: no; Orientação de Texto no Símbolo (typeTextRotation): Legível; Orientação de Texto no Símbolo (typeTextRotation_m): 2; Resolução: 12; Sombra: yes; Armário: Pintura - Branco Titânio; Utensílio: Pintura - Branco Titânio; Queimador de Gás e Grelha: Metal - Ferro; Suporte do Queimador de Gás: Metal - Aço Inoxidável; Porta Forno: Pintura - Branco Titânio; Janela do Forno: Vidro - Simples; Prateleira Forno (f_mat): Pintura - Laranja Cádmio; Botões: Pintura - Branco Titânio; Topo: Metal - Ferro; Mostrar Pontos-Quentes 2D em 3D: yes; Custo: 0; Volts: 0; Tipo de Grupo (FM_Type): Outros; Tipo de Grupo (iFMType): 25; Peso Objeto: 0; Unidade Peso Objeto: kg; Consumo Watts: 0; Saída: 0
REVESTIMENTO DE PAREDE POR ZONA (Expressão) - Número de Linhas: 10; DImensão 1: 0 mm; Dimensão 2: 0 mm; Largura do Rejunte: 10 mm; Altura do Revestimento: 100 mm
RODAPÉ (Expressão) - Comprimento da Barra (m): 2.4; Custo da Barra: 0
COBERTURA (Expressão) - Rendimento de Telha Genérica (m2): 0; Índice de Perda Telhas (%): 0; Rendimento Cumeeira (ml): 0
INFORMAÇÕES DO PRODUTO - Data de Aquisição: DD/MM/YYYY
EXPRESSÕES DE TEXTO (Expressão) - Localização do Produto no Projeto: Projeto: Casa Térrea IsoladaLocal: Piso: Terreo Cômodo: Sala / Cozinha; ID de Aberturas com Master ID: 01MB07; ID Dinâmico por Classificação: Mobília -MB07
ESTRUTURA (Expressão) - Custo por Volume (m3): 0
PISOS (Expressão) - Índice de Perda (%): 10
DESCRIÇÃO DA ESCADA (Expressão) - Abreviação da Largura da Escada: L; Abreviação da Altura do Espelho: E; Abreviação da Profundidade do Piso: P
ArchiCADQuantities - Length (A): 550 mm; Area: 0.3355 m2; Height: 900 mm; Volume (Net): 0.173644 m3; Width: 610 mm; Elevation to Project Zero: 0 mm; Elevation to 1º Nível de Referência: 0 mm; Elevation to 2º Nível de Referência: 0 mm; Elevation to Sea Level: 728220 mm; Elevation to Linked/Home Story: 0 mm; Home Offset: 0 mm; Surface Area: 6.38365 m2; Top Elevation To First Reference Level: 932 mm; Top Elevation To Home Story: 932 mm; Top Elevation To Project Zero: 932 mm; Top Elevation To Sea Level: 729152 mm; Top Elevation To Second Reference Level: 932 mm; Bottom Elevation To First Reference Level: 0 mm; Bottom Elevation To Home Story: 0 mm; Bottom Elevation To Project Zero: 0 mm; Bottom Elevation To Sea Level: 728220 mm; Bottom Elevation To Second Reference Level: 0 mm; Survey Coordinate X: 6033.5 mm; Survey Coordinate Y: 4548.53 mm; Survey Coordinate Z: 0 mm; Top Surface Area (Net): 0.3355 m2; Bottom Surface Area (Net): 6.38365 m2
AC_Equantity_Fogão_a_Gás_26 - Dimensão 1: 550 mm; Dimensão 2: 610 mm; Altura: 900 mm; Largura da Placa: 500 mm; Profundidade da Placa: 500 mm; Tamanho Fonte: 120 mm; Posição do Texto X: 0 mm; Posição do Texto Y: 0 mm; Espaço Mínimo na Frente: 900 mm; Espaço Mínimo no Lado 1: 0 mm; Espaço Mínimo no Lado 2: 0 mm; Nível da Base: 1000 mm; Nível do Topo: 0 mm
ALVENARIAS (Expressão) - Espessura da Argamassa: 10 mm
Component Quantities - Component, Component Volume (Net): 0.173644 m3; Component, Component Volume (Gross): 0.173644 m3
SUPERFÍCIES (Mapas) - Área da Superfície da Base (Geral): 0.3355 m2

# IfcFurnishingElement: Refrigerator 27, MB06
In: 01
Description: Geladeira; Classification: Mobília (Classificação ARCHICAD); 3E 56 04 Elementos de mobiliário (NBR 15965-5 3E); 2C 68 26 46 Refrigeradores e congeladores residenciais (NBR 15965-4 2C)
AC_Pset_Refrigerator_27 - Show 2D Hotspots in 3D: no; 3D Detail Level: 1; Top Panel (topp): yes; Freezer: yes; Freezer Type: 1; Toe (bToe): yes; Handle (bHandle): yes; Handle Type (gs_handle_style): Square; Handle Type (gs_handle_style_m): 1; 2D Detail Level: 1; Symbol Type: Style 1; Door Symbol Type: 2; Symbol Line Type: 1; Symbol Pen: Objetos - Geral; Symbol Fill Type: Trama Sólida; Contour Pen: Objetos - Geral; Fill Type: Trama Vazia; Fill Pen: Fundos - Cor 1; Fill Background Pen: Fundos - Cor 1; Display Text: no; Text: Refrig.; Text Pen: Texto - Rótulos; Font Type: Arial; Font Style Bold: no; Font Style Italic: no; Font Style Underline: no; Text Orientation on Symbol (typeTextRotation): Readable; Text Orientation on Symbol (typeTextRotation_m): 2; Shadow: yes; Appliance: Pintura - Branco Polido; Fridge Door: Pintura - Branco Polido; Toe (toe_mat): Metal - Aço Inoxidável; Top Panel (toppmat): Pintura - Branco Polido; Handle (handle_mat): Metal - Aço Inoxidável; Cost: 0; Volts: 0; Group Type (FM_Type): Electric Facilities; Group Type (iFMType): 8; Object Weight: 0; Object Weight Unit: kg; Wattage: 0; Egress: 0
ArchiCADProperties - Rotation Angle: 0 deg; Surface: GENERAL; Element ID: MB06; Hotlink and Element ID: MB06; Layer: CDHU-Mobiliario; Library Part Name: Refrigerator 27; Building Material / Composite / Profile / Fill: Trama Vazia; Fill Type: Trama Vazia; Colliding Zones: Sala / Cozinha; Related Zone Name: Sala / Cozinha; Related Zone Number: 01; Locked: no; Home Story Name: Terreo; Home Story Number: 0; Element Type: Object; Parent ID: MB06; Surfaces (All): Metal - Aço Inoxidável; Pintura - Branco Polido; Design Option Name: Main Model; Design Option Set Name: Main Model; Position: Interior; Show On Renovation Filter: All Relevant Filters; Structural Function: Non-Load-Bearing Element; Renovation Status: Existing; Design Option Status: Main Model; Design Option Set: Main Model
GARANTIA - Ínicio da Garantia: DD/MM/YYYY; Fim da Garantia: DD/MM/YYYY
FABRICAÇÃO - Data de Fabricação: DD/MM/YYYY; Site do Produto: www.graphisoft.com
ZONAS - Iluminação Mínima: 0; Ventilação Mínima: 0
INFORMAÇÕES DO PRODUTO - Data de Aquisição: DD/MM/YYYY
PISOS (Expressão) - Índice de Perda (%): 10
ILUMINAÇÃO E VENTILAÇÃO (Expressão) - Atende: Atende; Não Atende: Não Atende
RODAPÉ (Expressão) - Comprimento da Barra (m): 2.4; Custo da Barra: 0
COBERTURA (Expressão) - Rendimento de Telha Genérica (m2): 0; Índice de Perda Telhas (%): 0; Rendimento Cumeeira (ml): 0
REVESTIMENTO DE PAREDE POR ZONA (Expressão) - Número de Linhas: 10; DImensão 1: 0 mm; Dimensão 2: 0 mm; Largura do Rejunte: 10 mm; Altura do Revestimento: 100 mm
ESTRUTURA (Expressão) - Custo por Volume (m3): 0
EXPRESSÕES DE TEXTO (Expressão) - Localização do Produto no Projeto: Projeto: Casa Térrea IsoladaLocal: Piso: Terreo Cômodo: Sala / Cozinha; ID de Aberturas com Master ID: 01MB06; ID Dinâmico por Classificação: Mobília -MB06
DESCRIÇÃO DA ESCADA (Expressão) - Abreviação da Largura da Escada: L; Abreviação da Altura do Espelho: E; Abreviação da Profundidade do Piso: P
ALVENARIAS (Expressão) - Espessura da Argamassa: 10 mm
ArchiCADQuantities - Length (A): 700 mm; Area: 0.49 m2; Height: 1500 mm; Volume (Net): 0.727717 m3; Width: 700 mm; Elevation to Project Zero: 0 mm; Elevation to 1º Nível de Referência: 0 mm; Elevation to 2º Nível de Referência: 0 mm; Elevation to Sea Level: 728220 mm; Elevation to Linked/Home Story: 0 mm; Home Offset: 0 mm; Surface Area: 8.33949 m2; Top Elevation To First Reference Level: 1500 mm; Top Elevation To Home Story: 1500 mm; Top Elevation To Project Zero: 1500 mm; Top Elevation To Sea Level: 729720 mm; Top Elevation To Second Reference Level: 1500 mm; Bottom Elevation To First Reference Level: 0 mm; Bottom Elevation To Home Story: 0 mm; Bottom Elevation To Project Zero: 0 mm; Bottom Elevation To Sea Level: 728220 mm; Bottom Elevation To Second Reference Level: 0 mm; Survey Coordinate X: 4248 mm; Survey Coordinate Y: 4557.13 mm; Survey Coordinate Z: 0 mm; Top Surface Area (Net): 0.49 m2; Bottom Surface Area (Net): 8.33949 m2
AC_Equantity_Refrigerator_27 - Dimension 1: 700 mm; Dimension 2: 700 mm; Total Height: 1500 mm; Bottom Level: 1000 mm; Top Level: 0 mm; Door Thickness: 60 mm; Freezer Height: 400 mm; Toe Height: 90 mm; Toe Setback: 30 mm; Handle Height: 200 mm; Handle Vertical Position: 1000 mm; Font Size: 120 mm; Text Position X: 0 mm; Text Position Y: 0 mm; Minimal Space in Front: 850 mm; Minimal Space on Side 1: 0 mm; Minimal Space on Side 2: 0 mm
SUPERFÍCIES (Mapas) - Área da Superfície da Base (Geral): 0.49 m2
Component Quantities - Component, Component Volume (Net): 0.727717 m3; Component, Component Volume (Gross): 0.727717 m3

# IfcFurnishingElement: Shower Kit 27, FX04
In: 04
Description: Chuveiro Eletrico; Classification: Mobília (Classificação ARCHICAD); 3E 56 08 Equipamentos móveis conectados às instalações hidráulicas (NBR 15965-5 3E); 2C 78 14 Box e chuveiros (NBR 15965-4 2C)
ArchiCADProperties - Rotation Angle: 90 deg; Surface: GENERAL; Element ID: FX04; Hotlink and Element ID: FX04; Layer: CDHU-Mobiliario Fixo; Library Part Name: Shower Kit 27; Building Material / Composite / Profile / Fill: Trama Sólida; Fill Type: Trama Sólida; Colliding Zones: Banho; Related Zone Name: Banho; Related Zone Number: 04; Locked: no; Home Story Name: Terreo; Home Story Number: 0; Element Type: Object; Parent ID: FX04; Surfaces (All): Metal - Aço Inoxidável; Design Option Name: Main Model; Design Option Set Name: Main Model; Position: Interior; Show On Renovation Filter: All Relevant Filters; Structural Function: Non-Load-Bearing Element; Renovation Status: Existing; Design Option Status: Main Model; Design Option Set: Main Model
AC_Pset_Shower_Kit_27 - Set Program: no; 3D Detail Level: 1; Tap Style (gs_tap_type): Style 2; Tap Style (gs_tap_type_m): 25; Hot Water Connection: yes; Tool Type (ConToolType_1): 2; MEP System (ConSystem_1): Undefined; Shape Type (ConType_1): Circle; Connection Type (ConConnectorType_1): Welded; Cold Water Connection: yes; Tool Type (ConToolType_2): 2; MEP System (ConSystem_2): Undefined; Shape Type (ConType_2): Circle; Connection Type (ConConnectorType_2): Welded; Resolution: 12; Shadow: yes; Show 2D Hotspots in 3D: no; 2D Symbol Type (TapSymbol): Detailed; 2D Symbol Type (TapSymbol_m): 2; Contour Pen: Equipamentos - Hidrosanitário; Fill Type: Trama Vazia; Fill Pen: Fundos - Cor 1; Fill Background Pen: Fundos - Cor 1; Tap: Metal - Aço Inoxidável; Connection: Metal - Aço Inoxidável; Use System Surface: no; System Surface: Pintura - Amarelo Cádmio; Number of Connections: 2; IFC Subtype: 33; IFC Predefined Type: 4; Cost: 0; Area: 0; Volume: 0; Group Type (FM_Type): Sanitation; Group Type (iFMType): 13; Object Weight: 0; Object Weight Unit: kg
FABRICAÇÃO - Data de Fabricação: DD/MM/YYYY; Site do Produto: www.graphisoft.com
INFORMAÇÕES DO PRODUTO - Data de Aquisição: DD/MM/YYYY
ZONAS - Iluminação Mínima: 0; Ventilação Mínima: 0
GARANTIA - Ínicio da Garantia: DD/MM/YYYY; Fim da Garantia: DD/MM/YYYY
REVESTIMENTO DE PAREDE POR ZONA (Expressão) - Número de Linhas: 10; DImensão 1: 0 mm; Dimensão 2: 0 mm; Largura do Rejunte: 10 mm; Altura do Revestimento: 100 mm
PISOS (Expressão) - Índice de Perda (%): 10
RODAPÉ (Expressão) - Comprimento da Barra (m): 2.4; Custo da Barra: 0
ILUMINAÇÃO E VENTILAÇÃO (Expressão) - Atende: Atende; Não Atende: Não Atende
COBERTURA (Expressão) - Rendimento de Telha Genérica (m2): 0; Índice de Perda Telhas (%): 0; Rendimento Cumeeira (ml): 0
DESCRIÇÃO DA ESCADA (Expressão) - Abreviação da Largura da Escada: L; Abreviação da Altura do Espelho: E; Abreviação da Profundidade do Piso: P
ESTRUTURA (Expressão) - Custo por Volume (m3): 0
EXPRESSÕES DE TEXTO (Expressão) - Localização do Produto no Projeto: Projeto: Casa Térrea IsoladaLocal: Piso: Terreo Cômodo: Banho; ID de Aberturas com Master ID: 04FX04; ID Dinâmico por Classificação: Mobília -FX04
AC_Equantity_Shower_Kit_27 - Dimension 1: 1000 mm; Dimension 2: 1000 mm; Height: 115 mm; Mounting Height: 1200 mm; Shower Head X Position: 0 mm; Shower Head Y Position: -400 mm; Shower Head Z Position: 1050 mm; Nominal Depth (ConNominalDepth_1): 25 mm; Outer Diameter (ConWidth_1): 27 mm; Outer Depth (ConDepth_1): 27 mm; Wall Thickness (ConWallThickness_1): 1 mm; Connection Length (ConLength_1): 20 mm; Connector Diameter (ConConnectorWidth_1): 40 mm; Connector Depth (ConConnectorDepth_1): 0 mm; Connector Width (ConConnectorWidth2_1): 5 mm; Connection Position X (ConPosX_1): 75 mm; Connection Position Y (ConPosY_1): 0 mm; Connection Position Z (ConPosZ_1): 1200 mm; Nominal Depth (ConNominalDepth_2): 25 mm; Outer Diameter (ConWidth_2): 27 mm; Outer Depth (ConDepth_2): 27 mm; Wall Thickness (ConWallThickness_2): 1 mm; Connection Length (ConLength_2): 20 mm; Connector Diameter (ConConnectorWidth_2): 40 mm; Connector Depth (ConConnectorDepth_2): 0 mm; Connector Width (ConConnectorWidth2_2): 5 mm; Connection Position X (ConPosX_2): -75 mm; Connection Position Y (ConPosY_2): 0 mm; Connection Position Z (ConPosZ_2): 1200 mm; Bottom Level: 1000 mm; Top Level: 0 mm
ArchiCADQuantities - Length (A): 1000 mm; Area: 1 m2; Height: 115 mm; Volume (Net): 0.00236915 m3; Width: 1000 mm; Elevation to Project Zero: 0 mm; Elevation to 1º Nível de Referência: 0 mm; Elevation to 2º Nível de Referência: 0 mm; Elevation to Sea Level: 728220 mm; Elevation to Linked/Home Story: 0 mm; Home Offset: 0 mm; Surface Area: 0.412361 m2; Top Elevation To First Reference Level: 2270 mm; Top Elevation To Home Story: 2270 mm; Top Elevation To Project Zero: 2270 mm; Top Elevation To Sea Level: 730490 mm; Top Elevation To Second Reference Level: 2270 mm; Bottom Elevation To First Reference Level: 948.486 mm; Bottom Elevation To Home Story: 948.486 mm; Bottom Elevation To Project Zero: 948.486 mm; Bottom Elevation To Sea Level: 729168 mm; Bottom Elevation To Second Reference Level: 948.486 mm; Survey Coordinate X: 6697.78 mm; Survey Coordinate Y: 4121.87 mm; Survey Coordinate Z: 0 mm; Top Surface Area (Net): 1 m2; Bottom Surface Area (Net): 0.412361 m2
Component Quantities - Component, Component Volume (Net): 0.00236915 m3; Component, Component Volume (Gross): 0.00236915 m3
SUPERFÍCIES (Mapas) - Área da Superfície da Base (Geral): 1 m2
ALVENARIAS (Expressão) - Espessura da Argamassa: 10 mm

# IfcFurnishingElement: Sofa 27 (2)
In: 01
Classification: Mobília (Classificação ARCHICAD); 3E 56 04 Elementos de mobiliário (NBR 15965-5 3E); 2C 68 26 Equipamentos e mobiliário residencial (NBR 15965-4 2C)
AC_Pset_Sofa_27 - Style (stStyle): Style 1; Style (iStyle): 1; 3D Detail Level: 1; Leg (bLeg): yes; Leg Style (iLegType): 5; Leg Style (gs_leg_type): Type 5; 2D Detail Level: 1; Symbol Type: 4; Show Seats in 2D: yes; Contour Pen: Objetos - Geral; Fill Type: Trama Vazia; Fill Pen: Fundos - Cor 1; Fill Background Pen: Fundos - Cor 1; Resolution: 12; Shadow: yes; Extra Hotspot Editing: yes; Show 2D Hotspots in 3D: no; Sofa: Tecido - 01; Cushion: Tecido - 01; Leg (gs_leg_mat): Metal - Aço Inoxidável; Side: Madeira - Nogueira Horizontal; Trimming: Plástico - Laminado; Frame: Madeira - Pinho Granulado Horizontal; Seating: Pintura - Bege Areia; Cost: 0; Group Type (FM_Type): Furniture; Group Type (iFMType): 16; Object Weight: 0; Object Weight Unit: kg
INFORMAÇÕES DO PRODUTO - Data de Aquisição: DD/MM/YYYY
ZONAS - Iluminação Mínima: 0; Ventilação Mínima: 0
FABRICAÇÃO - Data de Fabricação: DD/MM/YYYY; Site do Produto: www.graphisoft.com
ILUMINAÇÃO E VENTILAÇÃO (Expressão) - Atende: Atende; Não Atende: Não Atende
ArchiCADProperties - Surface: GENERAL; Layer: CDHU-Mobiliario; Library Part Name: Sofa 27; Building Material / Composite / Profile / Fill: Trama Vazia; Fill Type: Trama Vazia; Colliding Zones: Sala / Cozinha; Related Zone Name: Sala / Cozinha; Related Zone Number: 01; Locked: no; Home Story Name: Terreo; Home Story Number: 0; Element Type: Object; Surfaces (All): Metal - Aço Inoxidável; Tecido - 01; Design Option Name: Main Model; Design Option Set Name: Main Model; Position: Interior; Show On Renovation Filter: All Relevant Filters; Structural Function: Non-Load-Bearing Element; Renovation Status: Existing; Design Option Status: Main Model; Design Option Set: Main Model
REVESTIMENTO DE PAREDE POR ZONA (Expressão) - Número de Linhas: 10; DImensão 1: 0 mm; Dimensão 2: 0 mm; Largura do Rejunte: 10 mm; Altura do Revestimento: 100 mm
GARANTIA - Ínicio da Garantia: DD/MM/YYYY; Fim da Garantia: DD/MM/YYYY
COBERTURA (Expressão) - Rendimento de Telha Genérica (m2): 0; Índice de Perda Telhas (%): 0; Rendimento Cumeeira (ml): 0
ESTRUTURA (Expressão) - Custo por Volume (m3): 0
DESCRIÇÃO DA ESCADA (Expressão) - Abreviação da Largura da Escada: L; Abreviação da Altura do Espelho: E; Abreviação da Profundidade do Piso: P
EXPRESSÕES DE TEXTO (Expressão) - Localização do Produto no Projeto: Projeto: Casa Térrea IsoladaLocal: Piso: Terreo Cômodo: Sala / Cozinha
AC_Equantity_Sofa_27 - Dimension 2: 700 mm; Height: 800 mm; Seat Height: 450 mm; Arm Height: 600 mm; Leg Height: 80 mm; Minimal Space in Front: 500 mm; Minimal Space on Sides: 0 mm; Minimal Space Behind: 0 mm; Bottom Level: 1000 mm; Top Level: 0 mm
ArchiCADQuantities - Height: 800 mm; Width: 700 mm; Elevation to Project Zero: 0 mm; Elevation to 1º Nível de Referência: 0 mm; Elevation to 2º Nível de Referência: 0 mm; Elevation to Sea Level: 728220 mm; Elevation to Linked/Home Story: 0 mm; Home Offset: 0 mm; Top Elevation To First Reference Level: 802.375 mm; Top Elevation To Home Story: 802.375 mm; Top Elevation To Project Zero: 802.375 mm; Top Elevation To Sea Level: 729022 mm; Top Elevation To Second Reference Level: 802.375 mm; Bottom Elevation To First Reference Level: 0 mm; Bottom Elevation To Home Story: 0 mm; Bottom Elevation To Project Zero: 0 mm; Bottom Elevation To Sea Level: 728220 mm; Bottom Elevation To Second Reference Level: 0 mm; Survey Coordinate Z: 0 mm
ALVENARIAS (Expressão) - Espessura da Argamassa: 10 mm
RODAPÉ (Expressão) - Comprimento da Barra (m): 2.4; Custo da Barra: 0
PISOS (Expressão) - Índice de Perda (%): 10
Name | Description | No. of Seats | Rotation Angle (deg) | Element ID = Hotlink and Element ID = Parent ID | ID de Aberturas com Master ID | ID Dinâmico por Classificação | Dimension 1 (mm) = Length (A) (mm) | Área da Superfície da Base (Geral) (m2) = Area (m2) = Top Surface Area (Net) (m2) | Component, Component Volume (Net) (m3) = Component, Component Volume (Gross) (m3) = Volume (Net) (m3) | Surface Area (m2) = Bottom Surface Area (Net) (m2) | Survey Coordinate X (mm) | Survey Coordinate Y (mm)
MB01 | Sofa 1 lugar | 1 | 180 | MB01 | 01MB01 | Mobília -MB01 | 800 | 0.56 | 0.258599 | 7.4382 | 1782.6 | 3637.77
MB02 | Sofa 2 lugares | 2 | 0 | MB02 | 01MB02 | Mobília -MB02 | 1200 | 0.84 | 0.375787 | 10.128 | 1867.87 | 5284.8

# IfcFurnishingElement: TV Stand Mounted 27, MB03
In: 01
Description: Rack para TV; Classification: Mobília (Classificação ARCHICAD); 3E 56 04 Elementos de mobiliário (NBR 15965-5 3E); 2C 68 26 Equipamentos e mobiliário residencial (NBR 15965-4 2C)
AC_Pset_TV_Stand_Mounted_27 - Show 2D Hotspots in 3D: no; Front Panel Position: 1; Rear Panel: yes; Number of Segments: 3; Cornice (bCornice): no; Segment Type 1: 2; Drawer Number 1: 2; Shelves Number 1: 1; Top Segment 1: no; Top Segment Type 1: 3; Segment Type 2: 4; Drawer Number 2: 2; Shelves Number 2: 1; Top Segment 2: no; Top Segment Type 2: 3; Segment Type 3: 1; Drawer Number 3: 2; Shelves Number 3: 1; Top Segment 3: no; Top Segment Type 3: 3; Uniform Panels: no; Segment to Edit: 1; Scheme to Edit: 1; Knob (bKnob): yes; Knob Group: 4; Knob Style: 301; 2D Detail Level: 1; 2D Symbol Style: 1; Contour Pen: Objetos - Geral; Fill Type: Trama Vazia; Fill Pen: Fundos - Cor 1; Fill Background Pen: Fundos - Cor 1; 3D Detail Level: 1; Resolution: 24; Shadow: yes; Cabinet: Madeira - Pinho Granulado Horizontal; Cornice (matCornice): Madeira - Pinho Granulado Horizontal; Knob (knobMat): Metal - Cromado 01; Leg: Metal - Cromado 01; Leg Accessory: Pintura - Preto Marfim; Cost: 0; Group Type (FM_Type): Furniture; Group Type (iFMType): 16; Object Weight: 0; Object Weight Unit: kg
COBERTURA (Expressão) - Rendimento de Telha Genérica (m2): 0; Índice de Perda Telhas (%): 0; Rendimento Cumeeira (ml): 0
ESTRUTURA (Expressão) - Custo por Volume (m3): 0
ILUMINAÇÃO E VENTILAÇÃO (Expressão) - Atende: Atende; Não Atende: Não Atende
RODAPÉ (Expressão) - Comprimento da Barra (m): 2.4; Custo da Barra: 0
REVESTIMENTO DE PAREDE POR ZONA (Expressão) - Número de Linhas: 10; DImensão 1: 0 mm; Dimensão 2: 0 mm; Largura do Rejunte: 10 mm; Altura do Revestimento: 100 mm
PISOS (Expressão) - Índice de Perda (%): 10
GARANTIA - Ínicio da Garantia: DD/MM/YYYY; Fim da Garantia: DD/MM/YYYY
INFORMAÇÕES DO PRODUTO - Data de Aquisição: DD/MM/YYYY
FABRICAÇÃO - Data de Fabricação: DD/MM/YYYY; Site do Produto: www.graphisoft.com
ArchiCADProperties - Rotation Angle: 90 deg; Surface: GENERAL; Element ID: MB03; Hotlink and Element ID: MB03; Layer: CDHU-Mobiliario; Library Part Name: TV Stand Mounted 27; Building Material / Composite / Profile / Fill: Trama Sólida; Fill Type: Trama Sólida; Colliding Zones: Sala / Cozinha; Related Zone Name: Sala / Cozinha; Related Zone Number: 01; Locked: no; Home Story Name: Terreo; Home Story Number: 0; Element Type: Object; Parent ID: MB03; Surfaces (All): Madeira - Pinho Granulado Horizontal; Design Option Name: Main Model; Design Option Set Name: Main Model; Position: Interior; Show On Renovation Filter: All Relevant Filters; Structural Function: Non-Load-Bearing Element; Renovation Status: Existing; Design Option Status: Main Model; Design Option Set: Main Model
Component Quantities - Component, Component Volume (Net): 0.0453166 m3; Component, Component Volume (Gross): 0.0453166 m3
ALVENARIAS (Expressão) - Espessura da Argamassa: 10 mm
SUPERFÍCIES (Mapas) - Área da Superfície da Base (Geral): 0.4 m2
EXPRESSÕES DE TEXTO (Expressão) - Localização do Produto no Projeto: Projeto: Casa Térrea IsoladaLocal: Piso: Terreo Cômodo: Sala / Cozinha; ID de Aberturas com Master ID: 01MB03; ID Dinâmico por Classificação: Mobília -MB03
AC_Equantity_TV_Stand_Mounted_27 - Width: 1000 mm; Depth: 400 mm; Height: 400 mm; Bottom Level: 1000 mm; Top Level: 0 mm; Top Segment Height: 200 mm; Cornice Thickness: 30 mm; Cornice Offset: 0 mm; Segment Width 1: 333.333 mm; Segment Width 2: 200 mm; Segment Width 3: 466.667 mm; Minimal Space in Front: 900 mm
ZONAS - Iluminação Mínima: 0; Ventilação Mínima: 0
ArchiCADQuantities - Length (A): 1000 mm; Area: 0.4 m2; Height: 400 mm; Volume (Net): 0.0453166 m3; Width: 400 mm; Elevation to Project Zero: 0 mm; Elevation to 1º Nível de Referência: 0 mm; Elevation to 2º Nível de Referência: 0 mm; Elevation to Sea Level: 728220 mm; Elevation to Linked/Home Story: 0 mm; Home Offset: 0 mm; Surface Area: 4.96375 m2; Top Elevation To First Reference Level: 400 mm; Top Elevation To Home Story: 400 mm; Top Elevation To Project Zero: 400 mm; Top Elevation To Sea Level: 728620 mm; Top Elevation To Second Reference Level: 400 mm; Bottom Elevation To First Reference Level: 0 mm; Bottom Elevation To Home Story: 0 mm; Bottom Elevation To Project Zero: 0 mm; Bottom Elevation To Sea Level: 728220 mm; Bottom Elevation To Second Reference Level: 0 mm; Survey Coordinate X: 1753.93 mm; Survey Coordinate Y: 3855.68 mm; Survey Coordinate Z: 0 mm; Top Surface Area (Net): 0.4 m2; Bottom Surface Area (Net): 4.96375 m2
DESCRIÇÃO DA ESCADA (Expressão) - Abreviação da Largura da Escada: L; Abreviação da Altura do Espelho: E; Abreviação da Profundidade do Piso: P

# IfcFurnishingElement: Tanque de Lavar Roupa 26, FX05
In: Terreo
Description: Tanque de lavar roupas; Classification: Mobília (Classificação ARCHICAD); 3E 56 08 Equipamentos móveis conectados às instalações hidráulicas (NBR 15965-5 3E); 2C 78 06 18 18 Pia de serviço (NBR 15965-4 2C)
AC_Pset_Tanque_de_Lavar_Roupa_26 - Mostrar Pontos-Quentes 2D em 3D: no; Definir Programa: no; Nível de Detalhe em 3D (gs_detlevel_3D): Detalhado; Nível de Detalhe em 3D (gs_detlevel_3D_m): 2; Proteção do Cano: yes; Torneira (bTap): yes; Conexão Água Fria: yes; Tipo de Ferramenta (ConToolType_1): 2; Sistema MEP (ConSystem_1): Não-Definido; Tipo de Forma (ConType_1): Círculo; Tipo de Conexão (ConConnectorType_1): Welded; Conexão Esgoto: yes; Tipo de Ferramenta (ConToolType_2): 2; Sistema MEP (ConSystem_2): Não-Definido; Tipo de Forma (ConType_2): Círculo; Tipo de Conexão (ConConnectorType_2): Welded; Resolução: 12; Sombra: yes; Nível de Detalhe em 2D (gs_detlevel_2D): Sensível à Escala; Nível de Detalhe em 2D (gs_detlevel_2D_m): 0; Tipo de Símbolo de Torneira (tapSymbol): Detalhado; Tipo de Símbolo de Torneira (tapSymbol_m): 2; Caneta de Contorno: Equipamentos - Hidrosanitário; Tipo de Trama: Trama Vazia; Caneta da Trama: Fundos - Cor 1; Caneta do Fundo da Trama: Fundos - Cor 1; Cuba: Pintura - Branco Titânio; Tubo: Pintura - Branco Titânio; Torneira (gs_tap_mat): Metal - Aço Inoxidável; Ralo: Metal - Aço Inoxidável; Conexão: Metal - Aço Inoxidável; Usar Superfície de Sistema: no; Sistema: Pintura - Amarelo Cádmio; Versão: 4; Número de Conexões: 2; Custo: 0; Tipo de Grupo (FM_Type): Instalações Sanitárias; Tipo de Grupo (iFMType): 13; Área: 0; Volume: 0; Peso Objeto: 0; Unidade Peso Objeto: kg
ArchiCADProperties - Rotation Angle: 180 deg; Surface: GENERAL; Element ID: FX05; Hotlink and Element ID: FX05; Layer: CDHU-Mobiliario Fixo; Library Part Name: Tanque de Lavar Roupa 26; Building Material / Composite / Profile / Fill: Trama Sólida; Fill Type: Trama Sólida; Locked: no; Home Story Name: Terreo; Home Story Number: 0; Element Type: Object; Parent ID: FX05; Surfaces (All): Metal - Aço Inoxidável; Pintura - Branco Titânio; Design Option Name: Main Model; Design Option Set Name: Main Model; Position: Exterior; Show On Renovation Filter: All Relevant Filters; Structural Function: Non-Load-Bearing Element; Renovation Status: Existing; Design Option Status: Main Model; Design Option Set: Main Model
INFORMAÇÕES DO PRODUTO - Data de Aquisição: DD/MM/YYYY
GARANTIA - Ínicio da Garantia: DD/MM/YYYY; Fim da Garantia: DD/MM/YYYY
ZONAS - Iluminação Mínima: 0; Ventilação Mínima: 0
PISOS (Expressão) - Índice de Perda (%): 10
ILUMINAÇÃO E VENTILAÇÃO (Expressão) - Atende: Atende; Não Atende: Não Atende
FABRICAÇÃO - Data de Fabricação: DD/MM/YYYY; Site do Produto: www.graphisoft.com
REVESTIMENTO DE PAREDE POR ZONA (Expressão) - Número de Linhas: 10; DImensão 1: 0 mm; Dimensão 2: 0 mm; Largura do Rejunte: 10 mm; Altura do Revestimento: 100 mm
RODAPÉ (Expressão) - Comprimento da Barra (m): 2.4; Custo da Barra: 0
COBERTURA (Expressão) - Rendimento de Telha Genérica (m2): 0; Índice de Perda Telhas (%): 0; Rendimento Cumeeira (ml): 0
ESTRUTURA (Expressão) - Custo por Volume (m3): 0
DESCRIÇÃO DA ESCADA (Expressão) - Abreviação da Largura da Escada: L; Abreviação da Altura do Espelho: E; Abreviação da Profundidade do Piso: P
EXPRESSÕES DE TEXTO (Expressão) - Localização do Produto no Projeto: Projeto: Casa Térrea IsoladaLocal: Piso: Terreo Cômodo:; ID de Aberturas com Master ID: FX05; ID Dinâmico por Classificação: Mobília -FX05
AC_Equantity_Tanque_de_Lavar_Roupa_26 - Dimensão 1: 530 mm; Dimensão 2: 520 mm; Altura: 820 mm; Altura Topo: 820 mm; Altura Cuba: 330 mm; Nível da Base: 0 mm; Nível do Topo: 820 mm; Altura Abaixo da Cuba: 490 mm; Altura Torneira: 300 mm; Distância da Torneira ao Centro: 0 mm; Profundidade Nominal (ConNominalDepth_1): 25 mm; Diâmetro Exterior (ConWidth_1): 27 mm; Profundidade Exterior (ConDepth_1): 27 mm; Espessura Parede (ConWallThickness_1): 1 mm; Comprimento da Conexão (ConLength_1): 20 mm; Diãmetro Conector (ConConnectorWidth_1): 40 mm; Profundidade Conector (ConConnectorDepth_1): 0 mm; Largura Conector (ConConnectorWidth2_1): 5 mm; Posição X da Conexão (ConPosX_1): 0 mm; Posição Y da Conexão (ConPosY_1): 0 mm; Posição Z da Conexão (ConPosZ_1): 1120 mm; Profundidade Nominal (ConNominalDepth_2): 25 mm; Diâmetro Exterior (ConWidth_2): 27 mm; Profundidade Exterior (ConDepth_2): 27 mm; Espessura Parede (ConWallThickness_2): 1 mm; Comprimento da Conexão (ConLength_2): 100 mm; Diãmetro Conector (ConConnectorWidth_2): 40 mm; Profundidade Conector (ConConnectorDepth_2): 0 mm; Largura Conector (ConConnectorWidth2_2): 5 mm; Posição X da Conexão (ConPosX_2): 0 mm; Posição Y da Conexão (ConPosY_2): -70 mm; Posição Z da Conexão (ConPosZ_2): 245 mm; Espaço Mínimo na Frente: 1100 mm; Espaço Mínimo no Lado 1: 200 mm; Espaço Mínimo no Lado 2: 200 mm
Component Quantities - Component, Component Volume (Net): 0.023384 m3; Component, Component Volume (Gross): 0.023384 m3
SUPERFÍCIES (Mapas) - Área da Superfície da Base (Geral): 0.2756 m2
ALVENARIAS (Expressão) - Espessura da Argamassa: 10 mm
ArchiCADQuantities - Length (A): 530 mm; Area: 0.2756 m2; Height: 820 mm; Volume (Net): 0.023384 m3; Width: 520 mm; Elevation to Project Zero: 0 mm; Elevation to 1º Nível de Referência: 0 mm; Elevation to 2º Nível de Referência: 0 mm; Elevation to Sea Level: 728220 mm; Elevation to Linked/Home Story: 0 mm; Home Offset: 0 mm; Surface Area: 1.76014 m2; Top Elevation To First Reference Level: 1171.2 mm; Top Elevation To Home Story: 1171.2 mm; Top Elevation To Project Zero: 1171.2 mm; Top Elevation To Sea Level: 729391 mm; Top Elevation To Second Reference Level: 1171.2 mm; Bottom Elevation To First Reference Level: 0 mm; Bottom Elevation To Home Story: 0 mm; Bottom Elevation To Project Zero: 0 mm; Bottom Elevation To Sea Level: 728220 mm; Bottom Elevation To Second Reference Level: 0 mm; Survey Coordinate X: 6461.72 mm; Survey Coordinate Y: 4769.17 mm; Survey Coordinate Z: 0 mm; Top Surface Area (Net): 0.2756 m2; Bottom Surface Area (Net): 1.76014 m2

# IfcFurnishingElement: WC 27, FX03
In: 04
Description: Bacia; Classification: Mobília (Classificação ARCHICAD); 3E 56 08 Equipamentos móveis conectados às instalações hidráulicas (NBR 15965-5 3E); 2C 78 18 Vasos sanitários (NBR 15965-4 2C)
AC_Pset_WC_27 - Show 2D Hotspots in 3D: no; Set Program: no; Mounting Type: Floor Mounted; Floor Mounted Bowl Type: 8; Wall Hung Bowl Type: Type 1; Lid: yes; Seat (bSeat): yes; Seat (gs_seat): Closed; Flush Type: Cistern; Cistern Type: 7; Elevated Cistern Type: Type 1; In-Wall Carrier Button Type: Type 1; Flushometer Type: Simple; Button Position: Front; Show In-Wall Carrier in 2D: no; Show In-Wall Carrier in 3D: no; Type of Effluent: On the Floor; Water Connection: yes; Tool Type (ConToolType_1): 2; MEP System (ConSystem_1): Undefined; Shape Type (ConType_1): Circle; Connection Type (ConConnectorType_1): Welded; Waste Water Connection: yes; Tool Type (ConToolType_2): 2; MEP System (ConSystem_2): Undefined; Shape Type (ConType_2): Circle; Connection Type (ConConnectorType_2): Welded; 3D Detail Level: 1; Resolution: 32; Shadow: yes; Show 3D (2D Projection): yes; 2D Detail Level: 1; Contour Pen: Equipamentos - Hidrosanitário; Fill Type: Trama Vazia; Fill Pen: Fundos - Cor 1; Fill Background Pen: Fundos - Cor 1; Bowl (gs_bowl_mat): Cerâmica - Porcelana; Seat (matSeatCover): Plástico - Laminado; Cistern: Pintura - Branco Polido; Cistern Pipe: Metal - Aço Inoxidável; Button: Pintura - Branco Polido; Sensor: Pintura - Anthracite; Flushometer Pipe: Metal - Aço Inoxidável; Connection: Metal - Aço Inoxidável; Number of Connections: 2; Area: 0; Volume: 0; Cost: 0; Group Type (FM_Type): Sanitation; Group Type (iFMType): 13; Object Weight: 0; Object Weight Unit: kg
INFORMAÇÕES DO PRODUTO - Data de Aquisição: DD/MM/YYYY
FABRICAÇÃO - Data de Fabricação: DD/MM/YYYY; Site do Produto: www.graphisoft.com
ArchiCADProperties - Rotation Angle: 90 deg; Surface: GENERAL; Element ID: FX03; Hotlink and Element ID: FX03; Layer: CDHU-Mobiliario Fixo; Library Part Name: WC 27; Building Material / Composite / Profile / Fill: Trama Sólida; Fill Type: Trama Sólida; Colliding Zones: Banho; Related Zone Name: Banho; Related Zone Number: 04; Locked: no; Home Story Name: Terreo; Home Story Number: 0; Element Type: Object; Parent ID: FX03; Surfaces (All): Metal - Aço Inoxidável; Pintura - Branco Polido; Cerâmica - Porcelana; Plástico - Laminado; Design Option Name: Main Model; Design Option Set Name: Main Model; Position: Interior; Show On Renovation Filter: All Relevant Filters; Structural Function: Non-Load-Bearing Element; Renovation Status: Existing; Design Option Status: Main Model; Design Option Set: Main Model
ZONAS - Iluminação Mínima: 0; Ventilação Mínima: 0
GARANTIA - Ínicio da Garantia: DD/MM/YYYY; Fim da Garantia: DD/MM/YYYY
PISOS (Expressão) - Índice de Perda (%): 10
REVESTIMENTO DE PAREDE POR ZONA (Expressão) - Número de Linhas: 10; DImensão 1: 0 mm; Dimensão 2: 0 mm; Largura do Rejunte: 10 mm; Altura do Revestimento: 100 mm
ESTRUTURA (Expressão) - Custo por Volume (m3): 0
RODAPÉ (Expressão) - Comprimento da Barra (m): 2.4; Custo da Barra: 0
COBERTURA (Expressão) - Rendimento de Telha Genérica (m2): 0; Índice de Perda Telhas (%): 0; Rendimento Cumeeira (ml): 0
EXPRESSÕES DE TEXTO (Expressão) - Localização do Produto no Projeto: Projeto: Casa Térrea IsoladaLocal: Piso: Terreo Cômodo: Banho; ID de Aberturas com Master ID: 04FX03; ID Dinâmico por Classificação: Mobília -FX03
DESCRIÇÃO DA ESCADA (Expressão) - Abreviação da Largura da Escada: L; Abreviação da Altura do Espelho: E; Abreviação da Profundidade do Piso: P
ILUMINAÇÃO E VENTILAÇÃO (Expressão) - Atende: Atende; Não Atende: Não Atende
ArchiCADQuantities - Length (A): 365 mm; Area: 0.22995 m2; Height: 400 mm; Volume (Net): 0.0529924 m3; Width: 630 mm; Elevation to Project Zero: 0 mm; Elevation to 1º Nível de Referência: 0 mm; Elevation to 2º Nível de Referência: 0 mm; Elevation to Sea Level: 728220 mm; Elevation to Linked/Home Story: 0 mm; Home Offset: 0 mm; Surface Area: 2.75433 m2; Top Elevation To First Reference Level: 765 mm; Top Elevation To Home Story: 765 mm; Top Elevation To Project Zero: 765 mm; Top Elevation To Sea Level: 728985 mm; Top Elevation To Second Reference Level: 765 mm; Bottom Elevation To First Reference Level: -20 mm; Bottom Elevation To Home Story: -20 mm; Bottom Elevation To Project Zero: -20 mm; Bottom Elevation To Sea Level: 728200 mm; Bottom Elevation To Second Reference Level: -20 mm; Survey Coordinate X: 6522.36 mm; Survey Coordinate Y: 3548.08 mm; Survey Coordinate Z: 0 mm; Top Surface Area (Net): 0.22995 m2; Bottom Surface Area (Net): 2.75433 m2
AC_Equantity_WC_27 - Dimension 1: 365 mm; Dimension 2: 630 mm; Height: 400 mm; Bottom Level: 1000 mm; Top Level: 0 mm; Seat Height: 400 mm; Bowl Width: 365 mm; Bowl Depth: 630 mm; Bowl Height: 400 mm; Distance from Wall: 25 mm; Cistern Elevation: 1200 mm; Pipe Diameter: 30 mm; Cistern Width: 390 mm; Cistern Depth: 170 mm; Cistern Height: 360 mm; Carrier Width: 500 mm; Carrier Height: 1200 mm; Carrier Depth: 120 mm; Water Connection Height: 755 mm; Nominal Depth (ConNominalDepth_1): 30 mm; Outer Diameter (ConWidth_1): 32 mm; Outer Depth (ConDepth_1): 32 mm; Wall Thickness (ConWallThickness_1): 1 mm; Connection Length (ConLength_1): 20 mm; Connector Diameter (ConConnectorWidth_1): 40 mm; Connector Depth (ConConnectorDepth_1): 0 mm; Connector Width (ConConnectorWidth2_1): 5 mm; Connection Position X (ConPosX_1): 0 mm; Connection Position Y (ConPosY_1): -25 mm; Connection Position Z (ConPosZ_1): 666 mm; Nominal Depth (ConNominalDepth_2): 110 mm; Outer Diameter (ConWidth_2): 114 mm; Outer Depth (ConDepth_2): 114 mm; Wall Thickness (ConWallThickness_2): 2 mm; Connection Length (ConLength_2): 20 mm; Connector Diameter (ConConnectorWidth_2): 130 mm; Connector Depth (ConConnectorDepth_2): 0 mm; Connector Width (ConConnectorWidth2_2): 5 mm; Connection Position X (ConPosX_2): 0 mm; Connection Position Y (ConPosY_2): -187 mm; Connection Position Z (ConPosZ_2): 0 mm; Minimal Space in Front: 400 mm; Minimal Space on Side 1: 0 mm; Minimal Space on Side 2: 250 mm; Minimal Space in Width 2: 1000 mm; Minimal Space in Front 2: 1000 mm
ALVENARIAS (Expressão) - Espessura da Argamassa: 10 mm
SUPERFÍCIES (Mapas) - Área da Superfície da Base (Geral): 0.22995 m2
Component Quantities - Component, Component Volume (Net): 0.0529924 m3; Component, Component Volume (Gross): 0.0529924 m3

# IfcFurnishingElement: Wardrobe Modular 27 (2)
Description: Guarda-roupas; Classification: Mobília (Classificação ARCHICAD); 3E 56 04 Elementos de mobiliário (NBR 15965-5 3E); 2C 68 26 14 Armários e gabinetes (NBR 15965-4 2C)
ArchiCADProperties - Rotation Angle: 0 deg; Surface: GENERAL; Layer: CDHU-Mobiliario; Library Part Name: Wardrobe Modular 27; Building Material / Composite / Profile / Fill: Trama Vazia; Fill Type: Trama Vazia; Locked: no; Home Story Name: Terreo; Home Story Number: 0; Element Type: Object; Surfaces (All): Metal - Cromado 01; Madeira - Pinho Granulado Horizontal; Pintura - Branco Polido; Metal - Alumínio; Vidro - Espelho; Design Option Name: Main Model; Design Option Set Name: Main Model; Position: Interior; Show On Renovation Filter: All Relevant Filters; Structural Function: Non-Load-Bearing Element; Renovation Status: Existing; Design Option Status: Main Model; Design Option Set: Main Model
INFORMAÇÕES DO PRODUTO - Data de Aquisição: DD/MM/YYYY
AC_Pset_Wardrobe_Modular_27 - Number of Modules (nModule): 1; Number of Modules (nTempModule): 1; Uniform Module Width: yes; Frame Type (frameType): Solid; Frame Type (iFrameType): 1; Door Type (doorType): Double Sliding Door; Door Type (iDoorType): 2; Select Module to Edit: 1; Horizontal Division (bDivision01): yes; Interior Fitting above Division (interiorTypeAbove01): Hanger; Interior Fitting Type (interiorType01): Hanger; Interior Fitting Type (iInteriorType01): 1; Number of Shelves (nShelves01): 6; Number of Drawers (nDrawers01): 1; Number of Drawers with Front (nDrawersFront01): 1; Number of Wire Basket (nWire01): 1; Number of Hangers (nHangers01): 1; Interior Fitting under Division (interiorTypeUnder01): Drawer; Interior Fitting under Division (iInteriorTypeUnder01): 4; Number of Shelves (nShelvesUnder01): 1; Number of Drawers (nDrawersUnder01): 3; Number of Drawers with Front (nDrawersFrontUnder01): 1; Number of Wire Basket (nWireUnder01): 1; Number of Hangers (nHangersUnder01): 1; Horizontal Division (bDivision02): no; Interior Fitting above Division (interiorTypeAbove02): Shelf; Interior Fitting Type (interiorType02): Shelf; Interior Fitting Type (iInteriorType02): 5; Number of Shelves (nShelves02): 6; Number of Drawers (nDrawers02): 1; Number of Drawers with Front (nDrawersFront02): 1; Number of Wire Basket (nWire02): 1; Number of Hangers (nHangers02): 1; Interior Fitting under Division (iInteriorTypeUnder02): 0; Number of Shelves (nShelvesUnder02): 1; Number of Drawers (nDrawersUnder02): 1; Number of Drawers with Front (nDrawersFrontUnder02): 1; Number of Wire Basket (nWireUnder02): 1; Number of Hangers (nHangersUnder02): 1; Horizontal Division (bDivision03): yes; Interior Fitting above Division (interiorTypeAbove03): Hanger; Interior Fitting Type (interiorType03): Hanger; Interior Fitting Type (iInteriorType03): 1; Number of Shelves (nShelves03): 6; Number of Drawers (nDrawers03): 1; Number of Drawers with Front (nDrawersFront03): 1; Number of Wire Basket (nWire03): 4; Number of Hangers (nHangers03): 1; Interior Fitting under Division (interiorTypeUnder03): Drawer; Interior Fitting under Division (iInteriorTypeUnder03): 4; Number of Shelves (nShelvesUnder03): 1; Number of Drawers (nDrawersUnder03): 3; Number of Drawers with Front (nDrawersFrontUnder03): 1; Number of Wire Basket (nWireUnder03): 1; Number of Hangers (nHangersUnder03): 1; Horizontal Division (bDivision04): no; Interior Fitting above Division (interiorTypeAbove04): Hanger; Interior Fitting Type (interiorType04): Hanger; Interior Fitting Type (iInteriorType04): 1; Number of Shelves (nShelves04): 6; Number of Drawers (nDrawers04): 1; Number of Drawers with Front (nDrawersFront04): 1; Number of Wire Basket (nWire04): 1; Number of Hangers (nHangers04): 1; Interior Fitting under Division (iInteriorTypeUnder04): 0; Number of Shelves (nShelvesUnder04): 1; Number of Drawers (nDrawersUnder04): 1; Number of Drawers with Front (nDrawersFrontUnder04): 1; Number of Wire Basket (nWireUnder04): 1; Number of Hangers (nHangersUnder04): 1; Horizontal Division (bDivision05): no; Interior Fitting above Division (interiorTypeAbove05): Shelf; Interior Fitting Type (interiorType05): Shelf; Interior Fitting Type (iInteriorType05): 5; Number of Shelves (nShelves05): 6; Number of Drawers (nDrawers05): 1; Number of Drawers with Front (nDrawersFront05): 1; Number of Wire Basket (nWire05): 1; Number of Hangers (nHangers05): 1; Interior Fitting under Division (iInteriorTypeUnder05): 0; Number of Shelves (nShelvesUnder05): 1; Number of Drawers (nDrawersUnder05): 1; Number of Drawers with Front (nDrawersFrontUnder05): 1; Number of Wire Basket (nWireUnder05): 1; Number of Hangers (nHangersUnder05): 1; Horizontal Division (bDivision06): no; Interior Fitting above Division (interiorTypeAbove06): Shelf; Interior Fitting Type (interiorType06): Shelf; Interior Fitting Type (iInteriorType06): 5; Number of Shelves (nShelves06): 6; Number of Drawers (nDrawers06): 1; Number of Drawers with Front (nDrawersFront06): 1; Number of Wire Basket (nWire06): 1; Number of Hangers (nHangers06): 1; Interior Fitting under Division (iInteriorTypeUnder06): 0; Number of Shelves (nShelvesUnder06): 1; Number of Drawers (nDrawersUnder06): 1; Number of Drawers with Front (nDrawersFrontUnder06): 1; Number of Wire Basket (nWireUnder06): 1; Number of Hangers (nHangersUnder06): 1; Door Style (doorStyle): Style 8; Door Style (iDoorStyle): 15; Edge Bevel: no; No. of Hor. Door Grids: 4; No. of Vert. Door Grids: 0; Door 1 Position %: 0; Door 2 Position %: 0; Door 3 Position %: 0; Drawer Style (drawerStyle): Style 1; Drawer Style (iDrawerStyle): 1; Knob (bKnob): no; Knob Style: 1; Placing: 1; Cornice (bCornice): yes; Cornice Style: 1; Side Overhang (gs_lining): Front; Side Overhang (gs_lining_m): 4; Base: yes; Base Style: 4; 2D Detail Level: 1; 2D Symbol Style: 1; Show Hanger in 2D: no; Contour Pen: Objetos - Geral; Fill Type: Trama Vazia; Fill Pen: Fundos - Cor 1; Fill Background Pen: Fundos - Cor 1; 3D Detail Level: 1; Resolution: 12; Shadow: yes; Showing 2D Hotspots in 3D: no; Cabinet (gs_cabinet_mat): Madeira - Pinho Granulado Horizontal; Cabinet (matSteelCabinet): Metal - Alumínio; Door Frame: Metal - Cromado 01; Door (Inset 1): Vidro - Espelho; Door (Inset 2): Pintura - Branco Polido; Knob (gs_knob_mat): Metal - Alumínio; Shelf (gs_shelf_mat): Madeira - Pinho Granulado Horizontal; Shelf (matSteelShelf): Metal - Alumínio; Hanger: Metal - Alumínio; Drawer (Frame): Madeira - Pinho Granulado Horizontal; Drawer (Inset): 0; Cornice (gs_cornice_mat): Madeira - Pinho Granulado Horizontal; Leg: Madeira - Pinho Granulado Horizontal; Wire Basket: Metal - Alumínio; Cost: 0; Group Type (FM_Type): Furniture; Group Type (iFMType): 16; Object Weight: 0; Object Weight Unit: kg
FABRICAÇÃO - Data de Fabricação: DD/MM/YYYY; Site do Produto: www.graphisoft.com
ZONAS - Iluminação Mínima: 0; Ventilação Mínima: 0
PISOS (Expressão) - Índice de Perda (%): 10
ILUMINAÇÃO E VENTILAÇÃO (Expressão) - Atende: Atende; Não Atende: Não Atende
GARANTIA - Ínicio da Garantia: DD/MM/YYYY; Fim da Garantia: DD/MM/YYYY
REVESTIMENTO DE PAREDE POR ZONA (Expressão) - Número de Linhas: 10; DImensão 1: 0 mm; Dimensão 2: 0 mm; Largura do Rejunte: 10 mm; Altura do Revestimento: 100 mm
ESTRUTURA (Expressão) - Custo por Volume (m3): 0
ALVENARIAS (Expressão) - Espessura da Argamassa: 10 mm
AC_Equantity_Wardrobe_Modular_27 - Depth: 500.001 mm; Height: 2200 mm; Frame Width: 20 mm; Horizontal Division Height (divisionHeight01): 700 mm; Module Width (modulWidth02): 640 mm; Horizontal Division Height (divisionHeight02): 300 mm; Module Width (modulWidth03): 526.667 mm; Horizontal Division Height (divisionHeight03): 700 mm; Horizontal Division Height (divisionHeight04): 600 mm; Horizontal Division Height (divisionHeight05): 600 mm; Horizontal Division Height (divisionHeight06): 600 mm; Door Thickness: 20 mm; Door Frame Width: 20 mm; Grid Width: 60 mm; Door 1 Position %: 0 mm; Door 2 Position %: 0 mm; Door 3 Position %: 0 mm; Drawer Frame: 30 mm; Horizontal Position: 50 mm; Vertical Position: 850 mm; Size: 100 mm; Cornice Thickness: 30 mm; Cornice Overhang: 0 mm; Base Height: 100 mm; Base Width: 20 mm; Minimal Space in Front: 500 mm; Bottom Level: 1000 mm; Top Level: 0 mm
ArchiCADQuantities - Height: 2200 mm; Width: 500.001 mm; Elevation to Project Zero: 0 mm; Elevation to 1º Nível de Referência: 0 mm; Elevation to 2º Nível de Referência: 0 mm; Elevation to Sea Level: 728220 mm; Elevation to Linked/Home Story: 0 mm; Home Offset: 0 mm; Top Elevation To First Reference Level: 2200 mm; Top Elevation To Home Story: 2200 mm; Top Elevation To Project Zero: 2200 mm; Top Elevation To Sea Level: 730420 mm; Top Elevation To Second Reference Level: 2200 mm; Bottom Elevation To First Reference Level: 0 mm; Bottom Elevation To Home Story: 0 mm; Bottom Elevation To Project Zero: 0 mm; Bottom Elevation To Sea Level: 728220 mm; Bottom Elevation To Second Reference Level: 0 mm; Survey Coordinate Z: 0 mm
DESCRIÇÃO DA ESCADA (Expressão) - Abreviação da Largura da Escada: L; Abreviação da Altura do Espelho: E; Abreviação da Profundidade do Piso: P
COBERTURA (Expressão) - Rendimento de Telha Genérica (m2): 0; Índice de Perda Telhas (%): 0; Rendimento Cumeeira (ml): 0
RODAPÉ (Expressão) - Comprimento da Barra (m): 2.4; Custo da Barra: 0
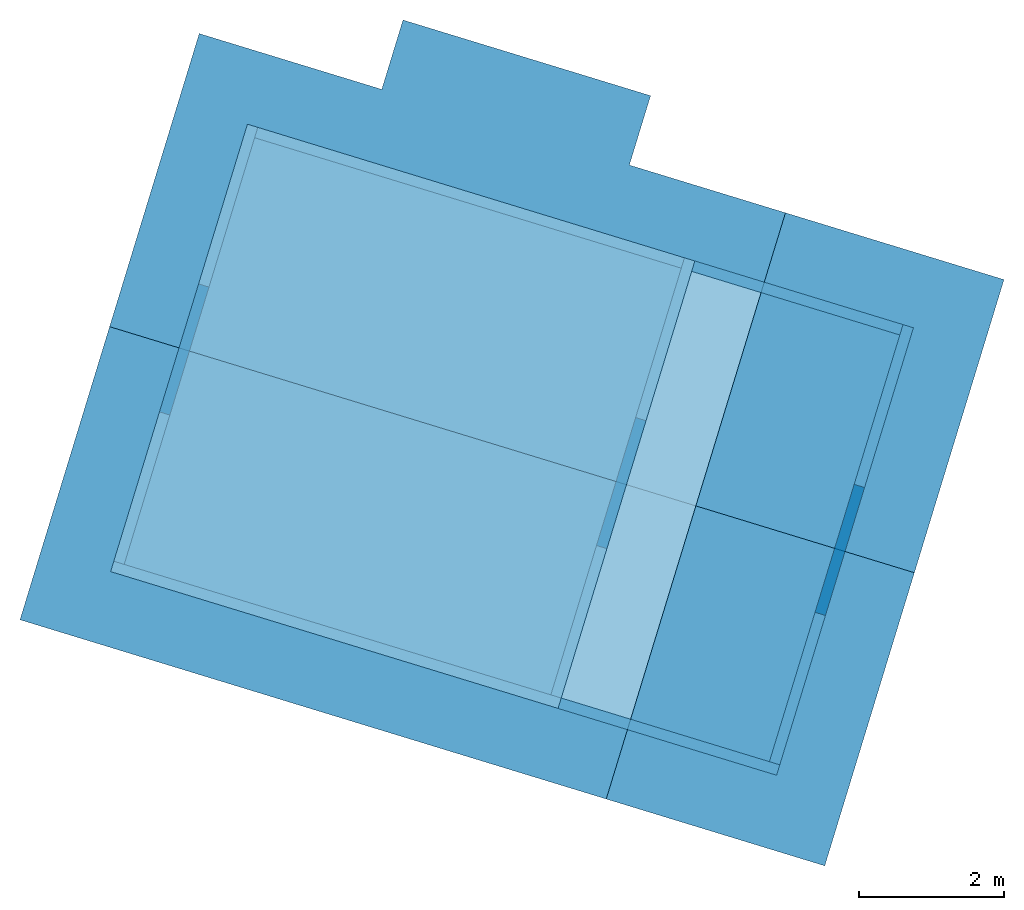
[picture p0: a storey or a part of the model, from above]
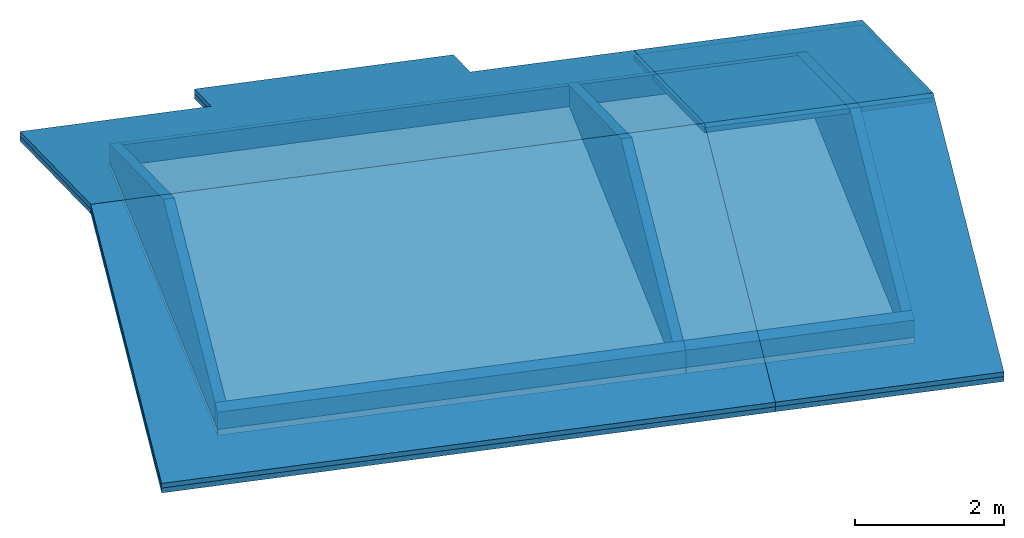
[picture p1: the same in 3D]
Properties of the parts of a building model (IFC2X3), part 5 of 7

# IfcFurnishingElement: Wardrobe Modular 27 (2)
Name | In | Element ID = Hotlink and Element ID = Parent ID | Colliding Zones = Related Zone Name | Related Zone Number | Component, Component Volume (Net) (m3) = Component, Component Volume (Gross) (m3) = Volume (Net) (m3) | Total Width (mm) = Length (A) (mm) | Module Width (modulWidth01) (mm) | Module Width (modulWidth04) (mm) | Module Width (modulWidth05) (mm) = Module Width (modulWidth06) (mm) | Area (m2) = Top Surface Area (Net) (m2) = Área da Superfície da Base (Geral) (m2) | Surface Area (m2) = Bottom Surface Area (Net) (m2) | Survey Coordinate X (mm) | Survey Coordinate Y (mm) | Localização do Produto no Projeto | ID de Aberturas com Master ID | ID Dinâmico por Classificação
MB11 | 02 | MB11 | Dormitorio 01 | 02 | 0.194554 | 1300 | 1280 | 13.3333 | 0 | 0.650001 | 25.7312 | 918.232 | 2490.35 | Projeto: Casa Térrea IsoladaLocal: Piso: Terreo Cômodo: Dormitorio 01 | 02MB11 | Mobília -MB11
MB12 | 03 | MB12 | Dormitorio 02 | 03 | 0.250939 | 1800 | 1780 | 100 | 100 | 0.900001 | 33.5407 | 3930.59 | 1569.38 | Projeto: Casa Térrea IsoladaLocal: Piso: Terreo Cômodo: Dormitorio 02 | 03MB12 | Mobília -MB12

# IfcOpeningElement (11)
In: Terreo
BaseQuantities - Depth: 150 mm
Name | Height (mm) | Width (mm) | Area (m2) | Volume (m3)
J07 | 1000 | 1000 | 1 | 0.02219
Porta 04 | 2200 | 850 | 1.87 | 0.10109
J06 | 1000 | 1000 | 1 | 0.02219
J01 | 1000 | 1000 | 1 | 0.02219
J04 | 1000 | 1000 | 1 | 0.02219
J05 | 1000 | 1000 | 1 | 0.02219
Porta 02 | 2200 | 850 | 1.87 | 0.10109
Porta 03 | 2200 | 850 | 1.87 | 0.10109
J02 | 1200 | 840 | 1.008 | 0.0147355
Porta 01 | 2200 | 850 | 1.87 | 0.0652821
J03 | 800 | 840 | 0.672 | 0.018413

# IfcRoof (4)
In: Cobertura
Classification: 3E 14 04 02 Telhado (NBR 15965-5 3E); Cobertura (Classificação ARCHICAD)
Pset_RoofCommon - IsExternal: yes
ArchiCADProperties - Geometry Method: Single-plane; Pitch: 21.8014 deg; Roof Level: 1; Trimming Body: Contours Down; Building Material / Composite / Profile / Fill: Cobertura, Telha Simples; Composite Structure: Cobertura, Telha Simples; Locked: no; Home Story Name: Cobertura; Home Story Number: 1; Element Type: Roof; Structure Type: Composite; Building Materials (All): Telha - Cobertura; Madeiramento - Estrutural; Surfaces (All): Madeira - Pinho Granulado Horizontal; Cobertura Telhas - Francesa Vermelho; Cover Fill: Trama Vazia; Position: Exterior; Show On Renovation Filter: All Relevant Filters; Structural Function: Non-Load-Bearing Element
FABRICAÇÃO - Data de Fabricação: DD/MM/YYYY; Site do Produto: www.graphisoft.com
INFORMAÇÕES DO PRODUTO - Data de Aquisição: DD/MM/YYYY
GARANTIA - Ínicio da Garantia: DD/MM/YYYY; Fim da Garantia: DD/MM/YYYY
ZONAS - Iluminação Mínima: 0; Ventilação Mínima: 0
PISOS (Expressão) - Índice de Perda (%): 10
Pset_ManufacturerTypeInformation - ProductionYear: DD/MM/YYYY
RODAPÉ (Expressão) - Comprimento da Barra (m): 2.4; Custo da Barra: 0
COBERTURA (Expressão) - Rendimento de Telha Genérica (m2): 0; Índice de Perda Telhas (%): 0; Rendimento Cumeeira (ml): 0
REVESTIMENTO DE PAREDE POR ZONA (Expressão) - Número de Linhas: 10; DImensão 1: 0 mm; Dimensão 2: 0 mm; Largura do Rejunte: 10 mm; Altura do Revestimento: 100 mm
ILUMINAÇÃO E VENTILAÇÃO (Expressão) - Atende: Atende; Não Atende: Não Atende
ESTRUTURA (Expressão) - Custo por Volume (m3): 0; Estimativa de Custo Total por Volume: 0; Estimativa de Custo Total por Volume (R$): 0,00 R$
DESCRIÇÃO DA ESCADA (Expressão) - Abreviação da Largura da Escada: L; Abreviação da Altura do Espelho: E; Abreviação da Profundidade do Piso: P
EXPRESSÕES DE TEXTO (Expressão) - Localização do Produto no Projeto: Projeto: Casa Térrea IsoladaLocal: Piso: Cobertura Cômodo:; Inclinação em %: i= 40%
SUPERFÍCIES (Mapas) - Superfície do Topo (Geral): Cobertura Telhas - Francesa Vermelho; Superfície da Base (Geral): Madeira - Pinho Granulado Horizontal
ArchiCADQuantities - Dome Connection Length: 0 mm; Eaves Length: 0 mm; End Wall Connection Length: 0 mm; Gables Length: 0 mm; Hips Length: 0 mm; Holes Surface Area: 0 m2; Hollow Connection Length: 0 mm; Number of Holes: 0; Number of Skylights: 0; Openings Surface Area: 0 m2; Peaks Length: 0 mm; Ridges Length: 0 mm; Side Wall Connection Length: 0 mm; Valleys Length: 0 mm; Thickness: 145 mm; Vertical Thickness: 156.17 mm; Height: 145 mm; Elevation to Project Zero: 2800 mm; Elevation to 1º Nível de Referência: 2800 mm; Elevation to 2º Nível de Referência: 2800 mm; Elevation to Sea Level: 731020 mm; Elevation to Linked/Home Story: 300 mm; Home Offset: 300 mm; Top Elevation To First Reference Level: 4246.17 mm; Top Elevation To Home Story: 1746.17 mm; Top Elevation To Project Zero: 4246.17 mm; Top Elevation To Sea Level: 732466 mm; Top Elevation To Second Reference Level: 4246.17 mm
ALVENARIAS (Expressão) - Espessura da Argamassa: 10 mm
Name | TotalArea (m2) = Surface Area of the Roof Bottom (Gross) (m2) = Surface Area of the Roof Top (Gross) (m2) = TotalSurfaceArea (m2) = Área Condicional da Superfície do Topo (Geral) (m2) | Element ID = Hotlink and Element ID = Parent ID = ID de Aberturas com Master ID | Layer | Design Option Name | Design Option Set Name = Design Option Set | Renovation Status | Design Option Status | ID Dinâmico por Classificação | Surface Area of the Roof Edges (Gross) (m2) | Surface Area of the Roof Bottom (Net) (m2) = Área Condicional da Superfície da Base (Geral) (m2) | Bottom Elevation To First Reference Level (mm) = Bottom Elevation To Project Zero (mm) = Bottom Elevation To Second Reference Level (mm) | Bottom Elevation To Home Story (mm) | Bottom Elevation To Sea Level (mm) | Área da Superfície da Face (Geral) (m2) | Área da Superfície da Base (Geral) (m2)
Telhado 02 | 38.4514 | Telhado 02 | CDHU-Telhado | Main Model | Main Model | Existing | Main Model | Cobertura -Telhado 02 | 3.9589 | 36.2543 | 2400 | -100 | 730620 | 3.92255 | 35.7012
Telhado 03 | 14.3339 | Telhado 03 | CDHU-Ampliacao | Ampliacao | New Option Set | New | New Option Set - Ampliacao | Cobertura -Telhado 03 | 2.3035 | 13.4898 | 2400 | -100 | 730620 | 2.27927 | 13.3087
Telhado 01 | 42.2949 | Telhado 01 | CDHU-Telhado | Main Model | Main Model | Existing | Main Model | Cobertura -Telhado 01 | 4.27124 | 40.0978 | 2000 | -500 | 730220 | 4.23489 | 39.2699
Telhado 04 | 14.3339 | Telhado 04 | CDHU-Ampliacao | Ampliacao | New Option Set | New | New Option Set - Ampliacao | Cobertura -Telhado 04 | 2.3035 | 13.4898 | 2400 | -100 | 730620 | 2.27927 | 13.3087

# IfcSlab: Concreto - Contra Piso 100 (2)
In: Terreo
Type - PredefinedType: FLOOR
Description: Laje_interior_generico_in-loco_concreto-armado_140mm; Classification: Laje (Classificação ARCHICAD); 3E 16 02 02 Contrapiso (NBR 15965-5 3E); Material: Concreto - Contra Piso
ArchiCADProperties - Reference Plane Location: Top; Structural Analytical Model Generation: yes; Member Geometry Edited Manually: no; Building Material / Composite / Profile / Fill: Concreto - Contra Piso; Building Material: Concreto - Contra Piso; Locked: no; Home Story Name: Terreo; Home Story Number: 0; Element Type: Slab; Structure Type: Basic; Building Materials (All): Concreto - Contra Piso; Surfaces (All): Concreto - 03; Cover Fill: Trama Vazia; Number of Openings: 0; Top Surface: Concreto - 03; Edge Surface: Concreto - 03; Bottom Surface: Concreto - 03; Position: Interior; Show On Renovation Filter: All Relevant Filters; Structural Function: Load-Bearing Element
GARANTIA - Ínicio da Garantia: DD/MM/YYYY; Fim da Garantia: DD/MM/YYYY
FABRICAÇÃO - Data de Fabricação: DD/MM/YYYY; Site do Produto: www.graphisoft.com
Pset_ManufacturerTypeInformation - ProductionYear: DD/MM/YYYY
ZONAS - Iluminação Mínima: 0; Ventilação Mínima: 0
INFORMAÇÕES DO PRODUTO - Data de Aquisição: DD/MM/YYYY
REVESTIMENTO DE PAREDE POR ZONA (Expressão) - Número de Linhas: 10; DImensão 1: 0 mm; Dimensão 2: 0 mm; Largura do Rejunte: 10 mm; Altura do Revestimento: 100 mm
RODAPÉ (Expressão) - Comprimento da Barra (m): 2.4; Custo da Barra: 0
PISOS (Expressão) - Índice de Perda (%): 10
COBERTURA (Expressão) - Rendimento de Telha Genérica (m2): 0; Índice de Perda Telhas (%): 0; Rendimento Cumeeira (ml): 0
ILUMINAÇÃO E VENTILAÇÃO (Expressão) - Atende: Atende; Não Atende: Não Atende
SUPERFÍCIES (Mapas) - Superfície do Topo (Geral): Concreto - 03; Superfície da Face (Geral): Concreto - 03; Superfície da Base (Geral): Concreto - 03
ESTRUTURA (Expressão) - Custo por Volume (m3): 0; Estimativa de Custo Total por Volume: 0; Estimativa de Custo Total por Volume (R$): 0,00 R$
DESCRIÇÃO DA ESCADA (Expressão) - Abreviação da Largura da Escada: L; Abreviação da Altura do Espelho: E; Abreviação da Profundidade do Piso: P
Pset_SlabCommon - IsExternal: no; LoadBearing: yes
Material Properties - Concreto - Contra Piso, ThermalConductivity: 1.15; Concreto - Contra Piso, SpecificHeatCapacity: 1000 J/kg/K; Concreto - Contra Piso, MassDensity: 1800 kg/m3; Concreto - Contra Piso, Embodied Energy: 0.74 (MJ/kg); Concreto - Contra Piso, Embodied Carbon: 0.107 (kgCO₂/kg); Concreto - Contra Piso, Name: Concreto - Contra Piso; Concreto - Contra Piso, ID: REV; Concreto - Contra Piso, Participates in Collision Detection: yes; Concreto - Contra Piso, Data de Aquisição: DD/MM/YYYY; Concreto - Contra Piso, Data de Fabricação: DD/MM/YYYY; Concreto - Contra Piso, Site do Produto: www.graphisoft.com; Concreto - Contra Piso, Ínicio da Garantia: DD/MM/YYYY; Concreto - Contra Piso, Fim da Garantia: DD/MM/YYYY; Concreto - Contra Piso, Iluminação Mínima: 0; Concreto - Contra Piso, Ventilação Mínima: 0; Concreto - Contra Piso, Atende: Atende; Concreto - Contra Piso, Não Atende: Não Atende; Concreto - Contra Piso, Índice de Perda (%): 10; Concreto - Contra Piso, DImensão 1: 0 mm; Concreto - Contra Piso, Dimensão 2: 0 mm; Concreto - Contra Piso, Largura do Rejunte: 10 mm; Concreto - Contra Piso, Número de Linhas: 10; Concreto - Contra Piso, Comprimento da Barra (m): 2.4; Concreto - Contra Piso, Custo da Barra: 0; Concreto - Contra Piso, Espessura da Argamassa: 10 mm; Concreto - Contra Piso, Rendimento de Telha Genérica (m2): 0; Concreto - Contra Piso, Índice de Perda Telhas (%): 0; Concreto - Contra Piso, Rendimento Cumeeira (ml): 0; Concreto - Contra Piso, Custo por Volume (m3): 0; Concreto - Contra Piso, Abreviação da Largura da Escada: L; Concreto - Contra Piso, Abreviação da Altura do Espelho: E; Concreto - Contra Piso, Abreviação da Profundidade do Piso: P
ArchiCADQuantities - Elevation Bottom: -100 mm; Holes Surface Area: 0 m2; Elevation Top: 0 mm; Height: 100 mm; Elevation to Project Zero: 0 mm; Elevation to 1º Nível de Referência: 0 mm; Elevation to 2º Nível de Referência: 0 mm; Elevation to Sea Level: 728220 mm; Elevation to Linked/Home Story: 0 mm; Home Offset: 0 mm; Thickness: 100 mm; Floor Plan Holes Perimeter: 0 mm; Top Elevation To First Reference Level: 0 mm; Top Elevation To Home Story: 0 mm; Top Elevation To Project Zero: 0 mm; Top Elevation To Sea Level: 728220 mm; Top Elevation To Second Reference Level: 0 mm; Bottom Elevation To First Reference Level: -100 mm; Bottom Elevation To Home Story: -100 mm; Bottom Elevation To Project Zero: -100 mm; Bottom Elevation To Sea Level: 728120 mm; Bottom Elevation To Second Reference Level: -100 mm
BaseQuantities - Width: 100 mm
ALVENARIAS (Expressão) - Espessura da Argamassa: 10 mm
Component Quantities - Concreto - Contra Piso, Component Thickness: 100 mm
Name | Element ID = Hotlink and Element ID = Parent ID | Layer | Related Zone Name | Related Zone Number | Design Option Name | Design Option Set Name = Design Option Set | Renovation Status | Design Option Status | Localização do Produto no Projeto | ID de Aberturas com Master ID | ID Dinâmico por Classificação | Surface Area of the Slab Top (Conditional) (m2) = Surface Area of the Slab Bottom (Gross) (m2) = Surface Area of the Slab Bottom (Gross, with holes) (m2) = Surface Area of the Slab Top (Gross) (m2) = Surface Area of the Slab Top (Gross, with holes) (m2) = Area (m2) = Surface Area (m2) = Top Surface Area (Net) (m2) = Top Surface Area (Conditional) (m2) = Bottom Surface Area (Net) (m2) = Bottom Surface Area (Conditional) (m2) = Bottom Surface Area (Gross) (m2) = Top Surface Area (Gross) (m2) = GrossArea (m2) = NetArea (m2) = Concreto - Contra Piso, Projected Component Area (Net) (m2) = Concreto - Contra Piso, Projected Component Area (Gross) (m2) = Concreto - Contra Piso, Projected Component Area (Conditional) (m2) = Área da Superfície do Topo (Geral) (m2) = Área da Superfície da Base (Geral) (m2) = Área Condicional da Superfície do Topo (Geral) (m2) = Área Condicional da Superfície da Base (Geral) (m2) | Surface Area of the Slab Edges (Gross) (m2) = Surface Area of the Slab Edges (Gross, with holes) (m2) = Edge Surface Area (Net) (m2) = Edge Surface Area (Gross) (m2) = Área da Superfície da Face (Geral) (m2) | Volume (Net) (m3) = Volume (Conditional) (m3) = Volume (Gross) (m3) = GrossVolume (m3) = NetVolume (m3) = Concreto - Contra Piso, Component Volume (Net) (m3) = Concreto - Contra Piso, Component Volume (Gross) (m3) = Concreto - Contra Piso, Component Volume (Conditional) (m3) | Floor Plan Perimeter (mm) = Perimeter (mm) | Concreto - Contra Piso, Embodied Carbon | Concreto - Contra Piso, Embodied Energy (MJ) | Concreto - Contra Piso, Mass (kg)
Piso 01 | Piso 01 | CDHU-Piso | Dormitorio 01 | 02 | Main Model | Main Model | Existing | Main Model | Projeto: Casa Térrea IsoladaLocal: Piso: Terreo Cômodo: Dormitorio 01 | 02Piso 01 | Laje -Piso 01 | 41.6025 | 2.58 | 4.16025 | 25800 | 801.265 (kgCO₂) | 5541.46 | 7488.45
Piso 03 | Piso 03 | CDHU-Ampliacao | Futura Ampliacao | 07 | Ampliacao | New Option Set | New | New Option Set - Ampliacao | Projeto: Casa Térrea IsoladaLocal: Piso: Terreo Cômodo: Futura Ampliacao | 07Piso 03 | Laje -Piso 03 | 20.3175 | 1.92 | 2.03175 | 19200 | 391.315 (kgCO₂) | 2706.29 | 3657.15

# IfcSlab: Concreto - Contra Piso 50 (2)
In: Terreo
Type - PredefinedType: FLOOR
Description: Laje_interior_generico_in-loco_concreto-armado_140mm; Classification: Laje (Classificação ARCHICAD); 3E 16 02 02 Contrapiso (NBR 15965-5 3E); Material: Concreto - Contra Piso
ArchiCADProperties - Reference Plane Location: Top; Structural Analytical Model Generation: yes; Member Geometry Edited Manually: no; Building Material / Composite / Profile / Fill: Concreto - Contra Piso; Building Material: Concreto - Contra Piso; Locked: no; Home Story Name: Terreo; Home Story Number: 0; Element Type: Slab; Structure Type: Basic; Building Materials (All): Concreto - Contra Piso; Surfaces (All): Concreto - 03; Cover Fill: Trama Vazia; Number of Openings: 0; Top Surface: Concreto - 03; Edge Surface: Concreto - 03; Bottom Surface: Concreto - 03; Position: Interior; Show On Renovation Filter: All Relevant Filters; Structural Function: Load-Bearing Element
Pset_ManufacturerTypeInformation - ProductionYear: DD/MM/YYYY
INFORMAÇÕES DO PRODUTO - Data de Aquisição: DD/MM/YYYY
GARANTIA - Ínicio da Garantia: DD/MM/YYYY; Fim da Garantia: DD/MM/YYYY
FABRICAÇÃO - Data de Fabricação: DD/MM/YYYY; Site do Produto: www.graphisoft.com
ILUMINAÇÃO E VENTILAÇÃO (Expressão) - Atende: Atende; Não Atende: Não Atende
PISOS (Expressão) - Índice de Perda (%): 10
REVESTIMENTO DE PAREDE POR ZONA (Expressão) - Número de Linhas: 10; DImensão 1: 0 mm; Dimensão 2: 0 mm; Largura do Rejunte: 10 mm; Altura do Revestimento: 100 mm
ZONAS - Iluminação Mínima: 0; Ventilação Mínima: 0
RODAPÉ (Expressão) - Comprimento da Barra (m): 2.4; Custo da Barra: 0
DESCRIÇÃO DA ESCADA (Expressão) - Abreviação da Largura da Escada: L; Abreviação da Altura do Espelho: E; Abreviação da Profundidade do Piso: P
EXPRESSÕES DE TEXTO (Expressão) - Localização do Produto no Projeto: Projeto: Casa Térrea IsoladaLocal: Piso: Terreo Cômodo:
COBERTURA (Expressão) - Rendimento de Telha Genérica (m2): 0; Índice de Perda Telhas (%): 0; Rendimento Cumeeira (ml): 0
ESTRUTURA (Expressão) - Custo por Volume (m3): 0; Estimativa de Custo Total por Volume: 0; Estimativa de Custo Total por Volume (R$): 0,00 R$
Pset_SlabCommon - IsExternal: no; LoadBearing: yes
Material Properties - Concreto - Contra Piso, ThermalConductivity: 1.15; Concreto - Contra Piso, SpecificHeatCapacity: 1000 J/kg/K; Concreto - Contra Piso, MassDensity: 1800 kg/m3; Concreto - Contra Piso, Embodied Energy: 0.74 (MJ/kg); Concreto - Contra Piso, Embodied Carbon: 0.107 (kgCO₂/kg); Concreto - Contra Piso, Name: Concreto - Contra Piso; Concreto - Contra Piso, ID: REV; Concreto - Contra Piso, Participates in Collision Detection: yes; Concreto - Contra Piso, Data de Aquisição: DD/MM/YYYY; Concreto - Contra Piso, Data de Fabricação: DD/MM/YYYY; Concreto - Contra Piso, Site do Produto: www.graphisoft.com; Concreto - Contra Piso, Ínicio da Garantia: DD/MM/YYYY; Concreto - Contra Piso, Fim da Garantia: DD/MM/YYYY; Concreto - Contra Piso, Iluminação Mínima: 0; Concreto - Contra Piso, Ventilação Mínima: 0; Concreto - Contra Piso, Atende: Atende; Concreto - Contra Piso, Não Atende: Não Atende; Concreto - Contra Piso, Índice de Perda (%): 10; Concreto - Contra Piso, DImensão 1: 0 mm; Concreto - Contra Piso, Dimensão 2: 0 mm; Concreto - Contra Piso, Largura do Rejunte: 10 mm; Concreto - Contra Piso, Número de Linhas: 10; Concreto - Contra Piso, Comprimento da Barra (m): 2.4; Concreto - Contra Piso, Custo da Barra: 0; Concreto - Contra Piso, Espessura da Argamassa: 10 mm; Concreto - Contra Piso, Rendimento de Telha Genérica (m2): 0; Concreto - Contra Piso, Índice de Perda Telhas (%): 0; Concreto - Contra Piso, Rendimento Cumeeira (ml): 0; Concreto - Contra Piso, Custo por Volume (m3): 0; Concreto - Contra Piso, Abreviação da Largura da Escada: L; Concreto - Contra Piso, Abreviação da Altura do Espelho: E; Concreto - Contra Piso, Abreviação da Profundidade do Piso: P
BaseQuantities - Width: 50 mm
ArchiCADQuantities - Elevation Bottom: -100 mm; Holes Surface Area: 0 m2; Elevation Top: -50 mm; Height: 50 mm; Elevation to Project Zero: -50 mm; Elevation to 1º Nível de Referência: -50 mm; Elevation to 2º Nível de Referência: -50 mm; Elevation to Sea Level: 728170 mm; Elevation to Linked/Home Story: -50 mm; Home Offset: -50 mm; Thickness: 50 mm; Floor Plan Holes Perimeter: 0 mm; Top Elevation To First Reference Level: -50 mm; Top Elevation To Home Story: -50 mm; Top Elevation To Project Zero: -50 mm; Top Elevation To Sea Level: 728170 mm; Top Elevation To Second Reference Level: -50 mm; Bottom Elevation To First Reference Level: -100 mm; Bottom Elevation To Home Story: -100 mm; Bottom Elevation To Project Zero: -100 mm; Bottom Elevation To Sea Level: 728120 mm; Bottom Elevation To Second Reference Level: -100 mm
ALVENARIAS (Expressão) - Espessura da Argamassa: 10 mm
Component Quantities - Concreto - Contra Piso, Component Thickness: 50 mm
SUPERFÍCIES (Mapas) - Superfície do Topo (Geral): Concreto - 03; Superfície da Face (Geral): Concreto - 03; Superfície da Base (Geral): Concreto - 03
Name | Element ID = Hotlink and Element ID = Parent ID = ID de Aberturas com Master ID | Layer | Design Option Name | Design Option Set Name = Design Option Set | Renovation Status | Design Option Status | ID Dinâmico por Classificação | Concreto - Contra Piso, Embodied Carbon | Concreto - Contra Piso, Embodied Energy (MJ) | Perimeter (mm) = Floor Plan Perimeter (mm) | GrossArea (m2) = NetArea (m2) = Surface Area of the Slab Top (Conditional) (m2) = Surface Area of the Slab Bottom (Gross) (m2) = Surface Area of the Slab Bottom (Gross, with holes) (m2) = Surface Area of the Slab Top (Gross) (m2) = Surface Area of the Slab Top (Gross, with holes) (m2) = Area (m2) = Surface Area (m2) = Top Surface Area (Net) (m2) = Top Surface Area (Conditional) (m2) = Bottom Surface Area (Net) (m2) = Bottom Surface Area (Conditional) (m2) = Bottom Surface Area (Gross) (m2) = Top Surface Area (Gross) (m2) = Área da Superfície do Topo (Geral) (m2) = Área da Superfície da Base (Geral) (m2) = Área Condicional da Superfície do Topo (Geral) (m2) = Área Condicional da Superfície da Base (Geral) (m2) = Concreto - Contra Piso, Projected Component Area (Net) (m2) = Concreto - Contra Piso, Projected Component Area (Gross) (m2) = Concreto - Contra Piso, Projected Component Area (Conditional) (m2) | GrossVolume (m3) = NetVolume (m3) = Volume (Net) (m3) = Volume (Conditional) (m3) = Volume (Gross) (m3) = Concreto - Contra Piso, Component Volume (Net) (m3) = Concreto - Contra Piso, Component Volume (Gross) (m3) = Concreto - Contra Piso, Component Volume (Conditional) (m3) | Surface Area of the Slab Edges (Gross) (m2) = Surface Area of the Slab Edges (Gross, with holes) (m2) = Edge Surface Area (Net) (m2) = Edge Surface Area (Gross) (m2) = Área da Superfície da Face (Geral) (m2) | Concreto - Contra Piso, Mass (kg)
Piso 02 | Piso 02 | CDHU-Piso | Main Model | Main Model | Existing | Main Model | Laje -Piso 02 | 239.966 (kgCO₂) | 1659.58 | 46700 | 24.9186 | 1.24593 | 2.335 | 2242.67
Piso 04 | Piso 04 | CDHU-Ampliacao | Ampliacao | New Option Set | New | New Option Set - Ampliacao | Laje -Piso 04 | 142.042 (kgCO₂) | 982.349 | 31500 | 14.75 | 0.737499 | 1.575 | 1327.5

# IfcSlab: Concreto - Estrutural 100 (2)
In: Cobertura
Type - PredefinedType: FLOOR
Description: Laje_interior_generico_in-loco_concreto-armado_140mm; Classification: Laje (Classificação ARCHICAD); 3E 12 06 08 Laje (NBR 15965-5 3E); Material: Concreto - Estrutural
Pset_ManufacturerTypeInformation - ProductionYear: DD/MM/YYYY
FABRICAÇÃO - Data de Fabricação: DD/MM/YYYY; Site do Produto: www.graphisoft.com
INFORMAÇÕES DO PRODUTO - Data de Aquisição: DD/MM/YYYY
GARANTIA - Ínicio da Garantia: DD/MM/YYYY; Fim da Garantia: DD/MM/YYYY
ZONAS - Iluminação Mínima: 0; Ventilação Mínima: 0
ArchiCADProperties - Reference Plane Location: Bottom; Structural Analytical Model Generation: yes; Member Geometry Edited Manually: no; Building Material / Composite / Profile / Fill: Concreto - Estrutural; Building Material: Concreto - Estrutural; Locked: no; Home Story Name: Cobertura; Home Story Number: 1; Element Type: Slab; Structure Type: Basic; Building Materials (All): Concreto - Estrutural; Surfaces (All): Concreto - 03; Cover Fill: Trama Vazia; Number of Openings: 0; Top Surface: Concreto - 03; Edge Surface: Concreto - 03; Bottom Surface: Concreto - 03; Position: Interior; Show On Renovation Filter: All Relevant Filters; Structural Function: Load-Bearing Element
PISOS (Expressão) - Índice de Perda (%): 10
RODAPÉ (Expressão) - Comprimento da Barra (m): 2.4; Custo da Barra: 0
REVESTIMENTO DE PAREDE POR ZONA (Expressão) - Número de Linhas: 10; DImensão 1: 0 mm; Dimensão 2: 0 mm; Largura do Rejunte: 10 mm; Altura do Revestimento: 100 mm
ILUMINAÇÃO E VENTILAÇÃO (Expressão) - Atende: Atende; Não Atende: Não Atende
SUPERFÍCIES (Mapas) - Superfície do Topo (Geral): Concreto - 03; Superfície da Face (Geral): Concreto - 03; Superfície da Base (Geral): Concreto - 03
EXPRESSÕES DE TEXTO (Expressão) - Localização do Produto no Projeto: Projeto: Casa Térrea IsoladaLocal: Piso: Cobertura Cômodo:
ESTRUTURA (Expressão) - Custo por Volume (m3): 0; Estimativa de Custo Total por Volume: 0; Estimativa de Custo Total por Volume (R$): 0,00 R$
COBERTURA (Expressão) - Rendimento de Telha Genérica (m2): 0; Índice de Perda Telhas (%): 0; Rendimento Cumeeira (ml): 0
Pset_SlabCommon - IsExternal: no; LoadBearing: yes
Material Properties - Concreto - Estrutural, ThermalConductivity: 2.3; Concreto - Estrutural, SpecificHeatCapacity: 1000 J/kg/K; Concreto - Estrutural, MassDensity: 2300 kg/m3; Concreto - Estrutural, Embodied Energy: 1.92 (MJ/kg); Concreto - Estrutural, Embodied Carbon: 0.198 (kgCO₂/kg); Concreto - Estrutural, Name: Concreto - Estrutural; Concreto - Estrutural, ID: CON; Concreto - Estrutural, Participates in Collision Detection: yes; Concreto - Estrutural, Data de Aquisição: DD/MM/YYYY; Concreto - Estrutural, Data de Fabricação: DD/MM/YYYY; Concreto - Estrutural, Site do Produto: www.graphisoft.com; Concreto - Estrutural, Ínicio da Garantia: DD/MM/YYYY; Concreto - Estrutural, Fim da Garantia: DD/MM/YYYY; Concreto - Estrutural, Iluminação Mínima: 0; Concreto - Estrutural, Ventilação Mínima: 0; Concreto - Estrutural, Atende: Atende; Concreto - Estrutural, Não Atende: Não Atende; Concreto - Estrutural, Índice de Perda (%): 10; Concreto - Estrutural, DImensão 1: 0 mm; Concreto - Estrutural, Dimensão 2: 0 mm; Concreto - Estrutural, Largura do Rejunte: 10 mm; Concreto - Estrutural, Número de Linhas: 10; Concreto - Estrutural, Comprimento da Barra (m): 2.4; Concreto - Estrutural, Custo da Barra: 0; Concreto - Estrutural, Espessura da Argamassa: 10 mm; Concreto - Estrutural, Rendimento de Telha Genérica (m2): 0; Concreto - Estrutural, Índice de Perda Telhas (%): 0; Concreto - Estrutural, Rendimento Cumeeira (ml): 0; Concreto - Estrutural, Custo por Volume (m3): 0; Concreto - Estrutural, Abreviação da Largura da Escada: L; Concreto - Estrutural, Abreviação da Altura do Espelho: E; Concreto - Estrutural, Abreviação da Profundidade do Piso: P
DESCRIÇÃO DA ESCADA (Expressão) - Abreviação da Largura da Escada: L; Abreviação da Altura do Espelho: E; Abreviação da Profundidade do Piso: P
ALVENARIAS (Expressão) - Espessura da Argamassa: 10 mm
BaseQuantities - Width: 100 mm
ArchiCADQuantities - Elevation Bottom: 2500 mm; Holes Surface Area: 0 m2; Elevation Top: 2600 mm; Height: 100 mm; Elevation to Project Zero: 2500 mm; Elevation to 1º Nível de Referência: 2500 mm; Elevation to 2º Nível de Referência: 2500 mm; Elevation to Sea Level: 730720 mm; Elevation to Linked/Home Story: 0 mm; Home Offset: 0 mm; Thickness: 100 mm; Floor Plan Holes Perimeter: 0 mm; Top Elevation To First Reference Level: 2600 mm; Top Elevation To Home Story: 100 mm; Top Elevation To Project Zero: 2600 mm; Top Elevation To Sea Level: 730820 mm; Top Elevation To Second Reference Level: 2600 mm; Bottom Elevation To First Reference Level: 2500 mm; Bottom Elevation To Home Story: 0 mm; Bottom Elevation To Project Zero: 2500 mm; Bottom Elevation To Sea Level: 730720 mm; Bottom Elevation To Second Reference Level: 2500 mm
Component Quantities - Concreto - Estrutural, Component Thickness: 100 mm
Name | Element ID = Hotlink and Element ID = Parent ID = ID de Aberturas com Master ID | Layer | Design Option Name | Design Option Set Name = Design Option Set | Renovation Status | Design Option Status | ID Dinâmico por Classificação | Concreto - Estrutural, Embodied Carbon | Concreto - Estrutural, Embodied Energy (MJ) | Perimeter (mm) = Floor Plan Perimeter (mm) | GrossArea (m2) = NetArea (m2) = Surface Area of the Slab Top (Conditional) (m2) = Surface Area of the Slab Bottom (Gross) (m2) = Surface Area of the Slab Bottom (Gross, with holes) (m2) = Surface Area of the Slab Top (Gross) (m2) = Surface Area of the Slab Top (Gross, with holes) (m2) = Area (m2) = Surface Area (m2) = Top Surface Area (Net) (m2) = Top Surface Area (Conditional) (m2) = Bottom Surface Area (Net) (m2) = Bottom Surface Area (Conditional) (m2) = Bottom Surface Area (Gross) (m2) = Top Surface Area (Gross) (m2) = Área da Superfície do Topo (Geral) (m2) = Área da Superfície da Base (Geral) (m2) = Área Condicional da Superfície do Topo (Geral) (m2) = Área Condicional da Superfície da Base (Geral) (m2) = Concreto - Estrutural, Projected Component Area (Net) (m2) = Concreto - Estrutural, Projected Component Area (Gross) (m2) = Concreto - Estrutural, Projected Component Area (Conditional) (m2) | GrossVolume (m3) = NetVolume (m3) = Volume (Net) (m3) = Volume (Conditional) (m3) = Volume (Gross) (m3) = Concreto - Estrutural, Component Volume (Net) (m3) = Concreto - Estrutural, Component Volume (Gross) (m3) = Concreto - Estrutural, Component Volume (Conditional) (m3) | Surface Area of the Slab Edges (Gross) (m2) = Surface Area of the Slab Edges (Gross, with holes) (m2) = Edge Surface Area (Net) (m2) = Edge Surface Area (Gross) (m2) = Área da Superfície da Face (Geral) (m2) | Concreto - Estrutural, Mass (kg)
Laje 02 | Laje 02 | CDHU-Ampliacao | Ampliacao | New Option Set | New | New Option Set - Ampliacao | Laje -Laje 02 | 925.258 (kgCO₂) | 8972.2 | 19200 | 20.3175 | 2.03175 | 1.92 | 4673.02
Laje 01 | Laje 01 | CDHU-Laje | Main Model | Main Model | Existing | Main Model | Laje -Laje 01 | 1894.58 (kgCO₂) | 18371.7 | 25800 | 41.6025 | 4.16025 | 2.58 | 9568.58

# IfcWall: Bloco de Concreto - Estrutural 150 (23)
Description: Parede-interior-generico-in_loco-tijolo_maciço_sem_revestimento-140mm; Classification: Parede (Classificação ARCHICAD); 3E 14 02 00 Parede (NBR 15965-5 3E); Material: Bloco de Concreto - Estrutural
Pset_WallCommon - AcousticRating: 0,00; LoadBearing: yes
Pset_ManufacturerTypeInformation - ProductionYear: DD/MM/YYYY
INFORMAÇÕES DO PRODUTO - Data de Aquisição: DD/MM/YYYY
FABRICAÇÃO - Data de Fabricação: DD/MM/YYYY; Site do Produto: www.graphisoft.com
ArchiCADProperties - Wall Complexity: Straight; Geometry Method: Uniform; Reference Line Location: Center; Inside Face Surface: Blocos de Concreto - Aparelho ao Comprido; Outside Face Surface: Blocos de Concreto - Aparelho ao Comprido; Wall Inside Slant Angle: 90 deg; Wall Outside Slant Angle: 90 deg; Structural Analytical Model Generation: yes; Member Geometry Edited Manually: no; Building Material / Composite / Profile / Fill: Bloco de Concreto - Estrutural; Building Material: Bloco de Concreto - Estrutural; Locked: no; Element Type: Wall; Structure Type: Basic; Building Materials (All): Bloco de Concreto - Estrutural; Surfaces (All): Blocos de Concreto - Aparelho ao Comprido; Slant Angle: 90 deg; Number of Openings: 0; Edge Surface: Blocos de Concreto - Aparelho ao Comprido; Show On Renovation Filter: All Relevant Filters; Structural Function: Load-Bearing Element
CLASSIFICAÇÕES GERAIS - Transmissão Sonora: 0
GARANTIA - Ínicio da Garantia: DD/MM/YYYY; Fim da Garantia: DD/MM/YYYY
ZONAS - Iluminação Mínima: 0; Ventilação Mínima: 0
PISOS (Expressão) - Índice de Perda (%): 10
ILUMINAÇÃO E VENTILAÇÃO (Expressão) - Atende: Atende; Não Atende: Não Atende
COBERTURA (Expressão) - Rendimento de Telha Genérica (m2): 0; Índice de Perda Telhas (%): 0; Rendimento Cumeeira (ml): 0
ESTRUTURA (Expressão) - Custo por Volume (m3): 0; Estimativa de Custo Total por Volume: 0; Estimativa de Custo Total por Volume (R$): 0,00 R$
RODAPÉ (Expressão) - Comprimento da Barra (m): 2.4; Custo da Barra: 0
SUPERFÍCIES (Mapas) - Superfície da Face (Geral): Blocos de Concreto - Aparelho ao Comprido
DESCRIÇÃO DA ESCADA (Expressão) - Abreviação da Largura da Escada: L; Abreviação da Altura do Espelho: E; Abreviação da Profundidade do Piso: P
Material Properties - Bloco de Concreto - Estrutural, ThermalConductivity: 0.6; Bloco de Concreto - Estrutural, SpecificHeatCapacity: 880 J/kg/K; Bloco de Concreto - Estrutural, MassDensity: 1400 kg/m3; Bloco de Concreto - Estrutural, Embodied Energy: 0.72 (MJ/kg); Bloco de Concreto - Estrutural, Embodied Carbon: 0.088 (kgCO₂/kg); Bloco de Concreto - Estrutural, Name: Bloco de Concreto - Estrutural; Bloco de Concreto - Estrutural, ID: CON; Bloco de Concreto - Estrutural, Participates in Collision Detection: yes; Bloco de Concreto - Estrutural, Data de Aquisição: DD/MM/YYYY; Bloco de Concreto - Estrutural, Data de Fabricação: DD/MM/YYYY; Bloco de Concreto - Estrutural, Site do Produto: www.graphisoft.com; Bloco de Concreto - Estrutural, Ínicio da Garantia: DD/MM/YYYY; Bloco de Concreto - Estrutural, Fim da Garantia: DD/MM/YYYY; Bloco de Concreto - Estrutural, Iluminação Mínima: 0; Bloco de Concreto - Estrutural, Ventilação Mínima: 0; Bloco de Concreto - Estrutural, Atende: Atende; Bloco de Concreto - Estrutural, Não Atende: Não Atende; Bloco de Concreto - Estrutural, Índice de Perda (%): 10; Bloco de Concreto - Estrutural, DImensão 1: 0 mm; Bloco de Concreto - Estrutural, Dimensão 2: 0 mm; Bloco de Concreto - Estrutural, Largura do Rejunte: 10 mm; Bloco de Concreto - Estrutural, Número de Linhas: 10; Bloco de Concreto - Estrutural, Comprimento da Barra (m): 2.4; Bloco de Concreto - Estrutural, Custo da Barra: 0; Bloco de Concreto - Estrutural, Espessura da Argamassa: 10 mm; Bloco de Concreto - Estrutural, Rendimento de Telha Genérica (m2): 0; Bloco de Concreto - Estrutural, Índice de Perda Telhas (%): 0; Bloco de Concreto - Estrutural, Rendimento Cumeeira (ml): 0; Bloco de Concreto - Estrutural, Custo por Volume (m3): 0; Bloco de Concreto - Estrutural, Abreviação da Largura da Escada: L; Bloco de Concreto - Estrutural, Abreviação da Altura do Espelho: E; Bloco de Concreto - Estrutural, Abreviação da Profundidade do Piso: P
BaseQuantities - Width: 150 mm
REVESTIMENTO DE PAREDE POR ZONA (Expressão) - Número de Linhas: 10; DImensão 1: 0 mm; Dimensão 2: 0 mm; Largura do Rejunte: 10 mm; Altura do Revestimento: 100 mm
Component Quantities - Bloco de Concreto - Estrutural, Component Thickness: 150 mm; Bloco de Concreto - Estrutural, Rectangular Component Height: 2500 mm; Bloco de Concreto - Estrutural, Rectangular Component Width: 150 mm; Bloco de Concreto - Estrutural, Component Cross Section Area: 0.375 m2
ArchiCADQuantities - Number of Holes (Number of Empty Openings): 0; Number of Columns: 0; Volume of the Columns: 0 m3; Maximum Height of the Wall Skin on the Inside Face: 0 mm; Minimum Height of the Wall Skin on the Inside Face: 0 mm; Maximum Height of the Wall Skin on the Outside Face: 0 mm; Minimum Height of the Wall Skin on the Outside Face: 0 mm; Air Skin Thickness: 0 mm; Wall Component Thickness on the Inside Face: 0 mm; Wall Component Thickness on the Outside Face: 0 mm; End Thickness of the Wall: 150 mm; Surface Area of Empty Openings in the Wall: 0 m2; Height: 2500 mm; Width: 150 mm; Top Offset: 0 mm; Thickness: 150 mm; Insulation Skin Thickness: 0 mm
ALVENARIAS (Expressão) - Espessura da Argamassa: 10 mm
Name | In | IsExternal | Element ID = Hotlink and Element ID = Parent ID | Layer | Related Zone Name | Related Zone Number | Home Story Name | Home Story Number | Absolute Top Link Story | Relative Top Link Story | Top Link Story | Design Option Name | Design Option Set Name = Design Option Set | Position | Renovation Status | Design Option Status | Bloco de Concreto - Estrutural, Embodied Carbon | Bloco de Concreto - Estrutural, Embodied Energy (MJ) | Localização do Produto no Projeto | ID de Aberturas com Master ID | ID Dinâmico por Classificação | Length (mm) = Average length of the Wall (mm) = Length of the Wall at the Center (mm) | Height (mm) = Maximum Height of the Wall (mm) | GrossFootprintArea (m2) = NetFootprintArea (m2) = Área da Superfície da Base (Geral) (m2) = Area (m2) = Top Surface Area (Net) (m2) | GrossSideArea (m2) | NetSideArea (m2) | GrossVolume (m3) = Bloco de Concreto - Estrutural, Component Volume (Gross) (m3) = Bloco de Concreto - Estrutural, Component Volume (Conditional) (m3) = Volume (Conditional) (m3) | NetVolume (m3) = Bloco de Concreto - Estrutural, Component Volume (Net) (m3) = Volume (Net) (m3) | Área da Superfície da Face (Geral) (m2) = Edge Surface Area (Net) (m2) | Bloco de Concreto - Estrutural, Mass (kg) | Bloco de Concreto - Estrutural, Projected Component Area (Net) (m2) | Bloco de Concreto - Estrutural, Projected Component Area (Gross) (m2) | Bloco de Concreto - Estrutural, Projected Component Area (Conditional) (m2) | Number of Doors | Number of Windows | Minimum Height of the Wall (mm) | Area of the Doors (m2) | Combined Width of Doors (mm) | Area of the Windows (m2) | Combined Width of Windows (mm) | Analytic Surface Area of Openings on the Inside Face (m2) | Analytic Surface Area of Openings on the Outside Face (m2) | Surface Area of the Wall Inside Face (Net) (m2) | Surface Area of the Wall Outside Face (Net) (m2) = Surface Area (m2) = Bottom Surface Area (Net) (m2) | Analytic Volume of the Openings (m3) | Length of Reference Line (mm) | Length of the Wall Inside Face (Conditional) (mm) | Surface Area of the Wall Inside Face (Conditional) (m2) | Length of the Wall Outside Face (Conditional) (mm) | Surface Area of the Wall Outside Face (Conditional) (m2) | Surface Area of the Wall Inside Face (Gross) (m2) | Surface Area of the Wall Outside Face (Gross) (m2) | Length of the Wall on the Inside Face (mm) | Length of the Wall on the Outside Face (mm) | Elevation to Project Zero (mm) = Elevation to 1º Nível de Referência (mm) = Elevation to 2º Nível de Referência (mm) = Bottom Elevation To First Reference Level (mm) = Bottom Elevation To Project Zero (mm) = Bottom Elevation To Second Reference Level (mm) | Elevation to Sea Level (mm) = Bottom Elevation To Sea Level (mm) | Elevation to Linked/Home Story (mm) = Home Offset (mm) = Bottom Elevation To Home Story (mm) | 3D Length (mm) | Volume (Gross) (m3) | Floor Plan Perimeter (mm) | Top Elevation To First Reference Level (mm) = Top Elevation To Project Zero (mm) = Top Elevation To Second Reference Level (mm) | Top Elevation To Home Story (mm) | Top Elevation To Sea Level (mm)
Parede 06 | Terreo | no | Parede 06 | CDHU-Parede | Dormitorio 01 | 02 | Terreo | 0 | Cobertura | Home + 1 | Home + 1 (Cobertura) | Main Model | Main Model | Interior | Existing | Main Model | 138.6 (kgCO₂) | 1134 | Projeto: Casa Térrea IsoladaLocal: Piso: Terreo Cômodo: Dormitorio 01 | 02Parede 06 | Parede -Parede 06 | 3000 | 2500 | 0.45 | 7.5 | 7.5 | 1.125 | 1.125 | 0.9 | 1575 | 7.5 | 7.5 | 7.5 | 0 | 0 | 0 | 0 | 0 | 0 | 0 | 0 | 0 | 7.5 | 7.5 | 0 | 3150 | 3000 | 7.5 | 3000 | 7.5 | 8.25 | 8.25 | 3000 | 3000 | 0 | 728220 | 0 | 3000 | 1.2375 | 6300 | 2500 | 2500 | 730720
Parede 07 | Terreo | no | Parede 07 | CDHU-Parede | Sala / Cozinha | 01 | Terreo | 0 | Cobertura | Home + 1 | Home + 1 (Cobertura) | Main Model | Main Model | Interior | Existing | Main Model | 99.3301 (kgCO₂) | 812.701 | Projeto: Casa Térrea IsoladaLocal: Piso: Terreo Cômodo: Sala / Cozinha | 01Parede 07 | Parede -Parede 07 | 2075 | 2500 | 0.3225 | 5.37501 | 5.37501 | 0.806251 | 0.806251 | 0.645001 | 1128.75 | 5.37501 | 5.37501 | 5.37501 | 0 | 0 | 0 | 0 | 0 | 0 | 0 | 0 | 0 | 5.37501 | 5.37501 | 0 | 2150 | 2000 | 5.37501 | 2150 | 5.37501 | 5.75001 | 5.75001 | 2000 | 2150 | 0 | 728220 | 0 | 2150 | 0.862501 | 4512.14 | 2500 | 2500 | 730720
Parede 16 | Terreo | yes | Parede 16 | CDHU-Ampliacao | Futura Ampliacao | 08 | Terreo | 0 | Cobertura | Home + 1 | Home + 1 (Cobertura) | Ampliacao | New Option Set | Exterior | New | New Option Set - Ampliacao | 120.12 (kgCO₂) | 982.8 | Projeto: Casa Térrea IsoladaLocal: Piso: Terreo Cômodo: Futura Ampliacao | 08Parede 16 | Parede -Parede 16 | 3075 | 2500 | 0.45 | 7.5 | 6.5 | 1.125 | 0.975 | 1.275 | 1365 | 6.5 | 7.5 | 7.5 | 0 | 1 | 0 | 0 | 0 | 1 | 1000 | 1 | 1 | 6.5 | 6.5 | 0.15 | 3075 | 3000 | 7.5 | 3150 | 7.5 | 7.875 | 7.875 | 3000 | 3150 | 0 | 728220 | 0 | 3000 | 1.18125 | 6512.13 | 2500 | 2500 | 730720
Parede 14 | Terreo | no | Parede 14 | CDHU-Ampliacao | Futura Ampliacao | 07 | Terreo | 0 | Cobertura | Home + 1 | Home + 1 (Cobertura) | Ampliacao | New Option Set | Interior | New | New Option Set - Ampliacao | 24.2551 (kgCO₂) | 198.451 | Projeto: Casa Térrea IsoladaLocal: Piso: Terreo Cômodo: Futura Ampliacao | 07Parede 14 | Parede -Parede 14 | 450.002 | 2500 | 0.0787503 | 1.31251 | 1.31251 | 0.196876 | 0.196876 | 0.532501 | 275.626 | 1.31251 | 1.31251 | 1.31251 | 0 | 0 | 0 | 0 | 0 | 0 | 0 | 0 | 0 | 1.31251 | 1.31251 | 0 | 450.002 | 525.002 | 1.31251 | 375.002 | 1.31251 | 1.31251 | 1.31251 | 525.002 | 375.002 | 0 | 728220 | 0 | 525.002 | 0.196876 | 1262.14 | 2500 | 2500 | 730720
Parede 15 | Terreo | no | Parede 15 | CDHU-Ampliacao | Futura Ampliacao | 07 | Terreo | 0 | Cobertura | Home + 1 | Home + 1 (Cobertura) | Ampliacao | New Option Set | Interior | New | New Option Set - Ampliacao | 98.175 (kgCO₂) | 803.25 | Projeto: Casa Térrea IsoladaLocal: Piso: Terreo Cômodo: Futura Ampliacao | 07Parede 15 | Parede -Parede 15 | 2125 | 2500 | 0.31875 | 5.3125 | 5.3125 | 0.796875 | 0.796875 | 1.0125 | 1115.63 | 5.3125 | 5.3125 | 5.3125 | 0 | 0 | 0 | 0 | 0 | 0 | 0 | 0 | 0 | 5.3125 | 5.3125 | 0 | 2200 | 2125 | 5.3125 | 2125 | 5.3125 | 5.6875 | 5.6875 | 2125 | 2125 | 0 | 728220 | 0 | 2125 | 0.853125 | 4550 | 2500 | 2500 | 730720
Parede 02 | Terreo | no | Parede 02 | CDHU-Parede | Hall | 05 | Terreo | 0 | Cobertura | Home + 1 | Home + 1 (Cobertura) | Main Model | Main Model | Interior | Existing | Main Model | 16.2624 (kgCO₂) | 133.056 | Projeto: Casa Térrea IsoladaLocal: Piso: Terreo Cômodo: Hall | 05Parede 02 | Parede -Parede 02 | 1325 | 2500 | 0.0374999 | 2.74999 | 0.879998 | 0.412499 | 0.132 | 0.2025 | 184.8 | 0.879998 | 2.74999 | 2.75 | 1 | 0 | 0 | 1.87 | 850 | 0 | 0 | 1.87 | 1.87 | 0.879998 | 0.879998 | 0.280499 | 1325 | 400.001 | 2.74999 | 550.001 | 2.74999 | 3.5 | 3.5 | 1250 | 1400 | 0 | 728220 | 0 | 1100 | 0.525 | 3012.13 | 2500 | 2500 | 730720
Parede 05 | Terreo | yes | Parede 05 | CDHU-Parede | Dormitorio 01 | 02 | Terreo | 0 | Cobertura | Home + 1 | Home + 1 (Cobertura) | Main Model | Main Model | Exterior | Existing | Main Model | 254.1 (kgCO₂) | 2079 | Projeto: Casa Térrea IsoladaLocal: Piso: Terreo Cômodo: Dormitorio 01 | 02Parede 05 | Parede -Parede 05 | 6300 | 2500 | 0.945 | 15.75 | 13.75 | 2.3625 | 2.0625 | 1.89 | 2887.5 | 13.75 | 15.75 | 15.75 | 0 | 2 | 0 | 0 | 0 | 2 | 2000 | 2 | 2 | 13.75 | 13.75 | 0.3 | 6300 | 6150 | 15.75 | 6450 | 15.75 | 16.125 | 16.125 | 6150 | 6450 | 0 | 728220 | 0 | 6300 | 2.41875 | 13024.3 | 2500 | 2500 | 730720
Parede 13 | Terreo | yes | Parede 13 | CDHU-Ampliacao | Futura Ampliacao | 06 | Terreo | 0 | Cobertura | Home + 1 | Home + 1 (Cobertura) | Ampliacao | New Option Set | Exterior | New | New Option Set - Ampliacao | 120.12 (kgCO₂) | 982.8 | Projeto: Casa Térrea IsoladaLocal: Piso: Terreo Cômodo: Futura Ampliacao | 06Parede 13 | Parede -Parede 13 | 3075 | 2500 | 0.45 | 7.5 | 6.5 | 1.125 | 0.975 | 1.275 | 1365 | 6.5 | 7.5 | 7.5 | 0 | 1 | 0 | 0 | 0 | 1 | 1000 | 1 | 1 | 6.5 | 6.5 | 0.15 | 3075 | 3150 | 7.5 | 3000 | 7.5 | 7.875 | 7.875 | 3150 | 3000 | 0 | 728220 | 0 | 3000 | 1.18125 | 6512.13 | 2500 | 2500 | 730720
Parede 17 | Terreo | no | Parede 17 | CDHU-Ampliacao | Futura Ampliacao | 07 | Terreo | 0 | Cobertura | Home + 1 | Home + 1 (Cobertura) | Ampliacao | New Option Set | Interior | New | New Option Set - Ampliacao | 39.2701 (kgCO₂) | 321.301 | Projeto: Casa Térrea IsoladaLocal: Piso: Terreo Cômodo: Futura Ampliacao | 07Parede 17 | Parede -Parede 17 | 925.002 | 2500 | 0.1275 | 2.12501 | 2.12501 | 0.318751 | 0.318751 | 0.255001 | 446.251 | 2.12501 | 2.12501 | 2.12501 | 0 | 0 | 0 | 0 | 0 | 0 | 0 | 0 | 0 | 2.12501 | 2.12501 | 0 | 1000 | 1000 | 2.12501 | 850.002 | 2.12501 | 2.87501 | 2.87501 | 1000 | 850.002 | 0 | 728220 | 0 | 850.002 | 0.431251 | 2212.14 | 2500 | 2500 | 730720
Parede 04 | Terreo | yes | Parede 04 | CDHU-Parede | Dormitorio 01 | 02 | Terreo | 0 | Cobertura | Home + 1 | Home + 1 (Cobertura) | Main Model | Main Model | Exterior | Existing | Main Model | 279.51 (kgCO₂) | 2286.9 | Projeto: Casa Térrea IsoladaLocal: Piso: Terreo Cômodo: Dormitorio 01 | 02Parede 04 | Parede -Parede 04 | 6300 | 2500 | 0.9675 | 16.125 | 15.125 | 2.41875 | 2.26875 | 1.935 | 3176.25 | 15.125 | 16.125 | 16.125 | 0 | 1 | 0 | 0 | 0 | 1 | 1000 | 1 | 1 | 15.125 | 15.125 | 0.15 | 6300 | 6150 | 16.125 | 6450 | 16.125 | 16.125 | 16.125 | 6150 | 6450 | 0 | 728220 | 0 | 6450 | 2.41875 | 13024.3 | 2500 | 2500 | 730720
Parede 08 | Terreo | yes | Parede 08 | CDHU-Parede | Dormitorio 02 | 03 | Terreo | 0 | Cobertura | Home + 1 | Home + 1 (Cobertura) | Main Model | Main Model | Exterior | Existing | Main Model | 145.53 (kgCO₂) | 1190.7 | Projeto: Casa Térrea IsoladaLocal: Piso: Terreo Cômodo: Dormitorio 02 | 03Parede 08 | Parede -Parede 08 | 3225 | 2500 | 0.4725 | 7.87499 | 7.87499 | 1.18125 | 1.18125 | 1.32 | 1653.75 | 7.87499 | 7.87499 | 7.87499 | 0 | 0 | 0 | 0 | 0 | 0 | 0 | 0 | 0 | 7.87499 | 7.87499 | 0 | 3225 | 3300 | 7.87499 | 3150 | 7.87499 | 8.24999 | 8.24999 | 3300 | 3150 | 0 | 728220 | 0 | 3150 | 1.2375 | 6812.13 | 2500 | 2500 | 730720
Parede 03 | Terreo | no | Parede 03 | CDHU-Parede | Dormitorio 01 | 02 | Terreo | 0 | Cobertura | Home + 1 | Home + 1 (Cobertura) | Main Model | Main Model | Interior | Existing | Main Model | 215.015 (kgCO₂) | 1759.21 | Projeto: Casa Térrea IsoladaLocal: Piso: Terreo Cômodo: Dormitorio 01 | 02Parede 03 | Parede -Parede 03 | 6150 | 2500 | 0.6675 | 15.375 | 11.635 | 2.30625 | 1.74525 | 1.59 | 2443.35 | 11.635 | 15.375 | 15.375 | 2 | 0 | 0 | 3.74 | 1700 | 0 | 0 | 3.74 | 3.74 | 11.635 | 11.635 | 0.561 | 6300 | 4450 | 15.375 | 4450 | 15.375 | 16.125 | 16.125 | 6150 | 6150 | 0 | 728220 | 0 | 6150 | 2.41875 | 12600 | 2500 | 2500 | 730720
Parede 01 | Terreo | yes | Parede 01 | CDHU-Parede | Sala / Cozinha | 01 | Terreo | 0 | Cobertura | Home + 1 | Home + 1 (Cobertura) | Main Model | Main Model | Exterior | Existing | Main Model | 225.456 (kgCO₂) | 1844.64 | Projeto: Casa Térrea IsoladaLocal: Piso: Terreo Cômodo: Sala / Cozinha | 01Parede 01 | Parede -Parede 01 | 6300 | 2500 | 0.8175 | 15.75 | 12.2 | 2.3625 | 1.83 | 1.7625 | 2562 | 12.2 | 15.75 | 15.75 | 1 | 2 | 0 | 1.87 | 850 | 1.68 | 1680 | 3.55 | 3.55 | 12.2 | 12.2 | 0.5325 | 6300 | 5600 | 15.75 | 5300 | 15.75 | 16.125 | 16.125 | 6450 | 6150 | 0 | 728220 | 0 | 6300 | 2.41875 | 13024.3 | 2500 | 2500 | 730720
Parede 08 | Terreo | yes | Parede 08 | CDHU-Demolir | Hall | 05 | Terreo | 0 | Cobertura | Home + 1 | Home + 1 (Cobertura) | Main Model | Main Model | Exterior | To Be Demolished | Main Model | 39.2701 (kgCO₂) | 321.301 | Projeto: Casa Térrea IsoladaLocal: Piso: Terreo Cômodo: Hall | 05Parede 08 | Parede -Parede 08 | 850.002 | 2500 | 0.1275 | 2.12501 | 2.12501 | 0.318751 | 0.318751 | 1.005 | 446.251 | 2.12501 | 2.12501 | 2.12501 | 0 | 0 | 2500 | 0 | 0 | 0 | 0 | 0 | 0 | 2.12501 | 2.12501 | 0 | 850.002 | 850.002 | 2.12501 | 850.002 | 2.12501 | 2.12501 | 2.12501 | 850.002 | 850.002 | 0 | 728220 | 0 | 850.002 | 0.318751 | 2000 | 2500 | 2500 | 730720
Parede 18 | Terreo | yes | Parede 18 | CDHU-Ampliacao | Futura Ampliacao | 06 | Terreo | 0 | Cobertura | Home + 1 | Home + 1 (Cobertura) | Ampliacao | New Option Set | Exterior | New | New Option Set - Ampliacao | 297.99 (kgCO₂) | 2438.1 | Projeto: Casa Térrea IsoladaLocal: Piso: Terreo Cômodo: Futura Ampliacao | 06Parede 18 | Parede -Parede 18 | 6300 | 2500 | 0.9675 | 16.125 | 16.125 | 2.41875 | 2.41875 | 1.935 | 3386.25 | 16.125 | 16.125 | 16.125 | 0 | 0 | 0 | 0 | 0 | 0 | 0 | 0 | 0 | 16.125 | 16.125 | 0 | 6300 | 6450 | 16.125 | 6150 | 16.125 | 16.125 | 16.125 | 6450 | 6150 | 0 | 728220 | 0 | 6450 | 2.41875 | 13024.3 | 2500 | 2500 | 730720
Parede 19 | Cobertura | yes | Parede 19 | CDHU-Ampliacao |  |  | Cobertura | 1 | Not Linked | Not Linked | Not Linked | Ampliacao | New Option Set | Exterior | New | New Option Set - Ampliacao | 17.2294 (kgCO₂) | 140.968 | Projeto: Casa Térrea IsoladaLocal: Piso: Cobertura Cômodo: | Parede 19 | Parede -Parede 19 | 3075 | 340.775 | 0.45 | 0.932325 | 0.932325 | 0.139849 | 0.139849 | 0.496616 | 195.788 | 1.02233 | 1.02233 | 1.02233 | 0 | 0 | 0 | 0 | 0 | 0 | 0 | 0 | -6.66134e-16 | 0.842325 | 1.02233 | 0 | 3075 | 3150 | 0.842325 | 3000 | 1.02233 | 1.12193 | 1.31093 | 3150 | 3000 | 2600 | 730820 | 100 | 3000 | 0.182464 | 6512.13 | 2940.78 | 440.775 | 731161
Parede 09 | Cobertura | yes | Parede 09 | CDHU-Parede |  |  | Cobertura | 1 | Not Linked | Not Linked | Not Linked | Main Model | Main Model | Exterior | Existing | Main Model | 35.3203 (kgCO₂) | 288.984 | Projeto: Casa Térrea IsoladaLocal: Piso: Cobertura Cômodo: | Parede 09 | Parede -Parede 09 | 6300 | 340.776 | 0.9225 | 1.91127 | 1.91127 | 0.286691 | 0.286691 | 0.9225 | 401.367 | 2.09577 | 2.09577 | 2.09577 | 0 | 0 | 0 | 0 | 0 | 0 | 0 | -2.66454e-15 | -3.10862e-15 | 1.72677 | 2.09577 | -2.22045e-16 | 6300 | 6450 | 1.72677 | 6150 | 2.09577 | 2.29728 | 2.68428 | 6450 | 6150 | 2600 | 730820 | 100 | 6150 | 0.373618 | 13024.3 | 2940.78 | 440.776 | 731161
Parede 08 | Terreo | yes | Parede 08 | CDHU-Parede | Banho | 04 | Terreo | 0 | Cobertura | Home + 1 | Home + 1 (Cobertura) | Main Model | Main Model | Exterior | Existing | Main Model | 99.3301 (kgCO₂) | 812.701 | Projeto: Casa Térrea IsoladaLocal: Piso: Terreo Cômodo: Banho | 04Parede 08 | Parede -Parede 08 | 2225 | 2500 | 0.3225 | 5.37501 | 5.37501 | 0.806251 | 0.806251 | 1.02 | 1128.75 | 5.37501 | 5.37501 | 5.37501 | 0 | 0 | 0 | 0 | 0 | 0 | 0 | 0 | 0 | 5.37501 | 5.37501 | 0 | 2225 | 2300 | 5.37501 | 2150 | 5.37501 | 5.75001 | 5.75001 | 2300 | 2150 | 0 | 728220 | 0 | 2150 | 0.862501 | 4812.14 | 2500 | 2500 | 730720
Parede 12 | Cobertura | yes | Parede 12 | CDHU-Parede |  |  | Cobertura | 1 | Not Linked | Not Linked | Not Linked | Main Model | Main Model | Exterior | Existing | Main Model | 109.488 (kgCO₂) | 895.807 | Projeto: Casa Térrea IsoladaLocal: Piso: Cobertura Cômodo: | Parede 12 | Parede -Parede 12 | 6300 | 1570.78 | 0.945 | 5.92465 | 5.92465 | 0.888697 | 0.888697 | 0.945 | 1244.18 | 5.92465 | 5.92465 | 5.92465 | 0 | 0 | 0 | 0 | 0 | 0 | 0 | 0 | -1.77636e-15 | 5.92465 | 5.92465 | -1.11022e-16 | 6300 | 6450 | 5.92465 | 6150 | 5.92465 | 6.45755 | 6.45755 | 6450 | 6150 | 2600 | 730820 | 100 | 6300 | 0.968632 | 13024.3 | 4170.78 | 1670.78 | 732391
Parede 11 | Cobertura | yes | Parede 11 | CDHU-Parede |  |  | Cobertura | 1 | Not Linked | Not Linked | Not Linked | Main Model | Main Model | Exterior | Existing | Main Model | 109.488 (kgCO₂) | 895.807 | Projeto: Casa Térrea IsoladaLocal: Piso: Cobertura Cômodo: | Parede 11 | Parede -Parede 11 | 6300 | 1570.78 | 0.945 | 5.92465 | 5.92465 | 0.888697 | 0.888697 | 0.945 | 1244.18 | 5.92465 | 5.92465 | 5.92465 | 0 | 0 | 0 | 0 | 0 | 0 | 0 | 0 | -1.77636e-15 | 5.92465 | 5.92465 | -1.11022e-16 | 6300 | 6150 | 5.92465 | 6450 | 5.92465 | 6.45755 | 6.45755 | 6150 | 6450 | 2600 | 730820 | 100 | 6300 | 0.968632 | 13024.3 | 4170.78 | 1670.78 | 732391
Parede 21 | Cobertura | yes | Parede 21 | CDHU-Ampliacao |  |  | Cobertura | 1 | Not Linked | Not Linked | Not Linked | Ampliacao | New Option Set | Exterior | New | New Option Set - Ampliacao | 109.488 (kgCO₂) | 895.807 | Projeto: Casa Térrea IsoladaLocal: Piso: Cobertura Cômodo: | Parede 21 | Parede -Parede 21 | 6300 | 1570.78 | 0.945 | 5.92465 | 5.92465 | 0.888697 | 0.888697 | 0.945 | 1244.18 | 5.92465 | 5.92465 | 5.92465 | 0 | 0 | 0 | 0 | 0 | 0 | 0 | 1.77636e-15 | 0 | 5.92465 | 5.92465 | 1.11022e-16 | 6300 | 6450 | 5.92465 | 6150 | 5.92465 | 6.45755 | 6.45755 | 6450 | 6150 | 2600 | 730820 | 100 | 6300 | 0.968632 | 13024.3 | 4170.78 | 1670.78 | 732391
Parede 10 | Cobertura | yes | Parede 10 | CDHU-Parede |  |  | Cobertura | 1 | Not Linked | Not Linked | Not Linked | Main Model | Main Model | Exterior | Existing | Main Model | 37.0435 (kgCO₂) | 303.083 | Projeto: Casa Térrea IsoladaLocal: Piso: Cobertura Cômodo: | Parede 10 | Parede -Parede 10 | 6300 | 340.779 | 0.9675 | 2.00452 | 2.00452 | 0.300678 | 0.300678 | 0.9675 | 420.949 | 2.19802 | 2.19802 | 2.19802 | 0 | 0 | 0 | 0 | 0 | 0 | 0 | 0 | 0 | 2.19802 | 1.81102 | 0 | 6300 | 6150 | 2.19802 | 6450 | 1.81102 | 2.6843 | 2.2973 | 6150 | 6450 | 2600 | 730820 | 100 | 6450 | 0.373619 | 13024.3 | 2940.78 | 440.779 | 731161
Parede 20 | Cobertura | yes | Parede 20 | CDHU-Ampliacao |  |  | Cobertura | 1 | Not Linked | Not Linked | Not Linked | Ampliacao | New Option Set | Exterior | New | New Option Set - Ampliacao | 18.0911 (kgCO₂) | 148.018 | Projeto: Casa Térrea IsoladaLocal: Piso: Cobertura Cômodo: | Parede 20 | Parede -Parede 20 | 3075 | 340.779 | 0.4725 | 0.978953 | 0.978953 | 0.146843 | 0.146843 | 0.519117 | 205.58 | 1.07345 | 1.07345 | 1.07345 | 0 | 0 | 0 | 0 | 0 | 0 | 0 | 6.66134e-16 | 0 | 1.07345 | 0.884453 | 2.77556e-17 | 3075 | 3000 | 1.07345 | 3150 | 0.884453 | 1.31094 | 1.12194 | 3000 | 3150 | 2600 | 730820 | 100 | 3150 | 0.182466 | 6512.13 | 2940.78 | 440.779 | 731161

# IfcWindow: Janela 26 (2)
In: Terreo
Type - OperationType: DOUBLE_PANEL_VERTICAL; ParameterTakesPrecedence: no; Sizeable: no
Type - Window Lining Properties - LiningDepth: 50 mm; LiningThickness: 35 mm; MullionThickness: 50 mm; FirstMullionOffset: 0.5
Type - Window Panel Properties - Panel 1 - OperationType: SLIDINGHORIZONTAL; PanelPosition: LEFT; FrameDepth: 20 mm; FrameThickness: 50 mm
Type - Window Panel Properties - Panel 2 - OperationType: SLIDINGHORIZONTAL; PanelPosition: RIGHT; FrameDepth: 20 mm; FrameThickness: 50 mm
Description: Janela de correr 2 folhas em aluminio; OverallHeight: 1000 mm; OverallWidth: 1000 mm; Classification: 3E 20 04 02 02 Janela de correr (NBR 15965-5 3E); Janela (Classificação ARCHICAD)
Pset_WindowCommon - ThermalTransmittance: 0; IsExternal: yes
INFORMAÇÕES DO PRODUTO - Data de Aquisição: DD/MM/YYYY
ArchiCADProperties - Reveal Dimensions: 1,00×1,00; Wallhole Dimensions: 1,00×1,00; Unit Dimensions: 1,00×1,00; Nominal W x H Size: 1,00×1,00; Nominal W x H x T Size: 1,00×1,00×0,15; Wall Structure: Bloco de Concreto - Estrutural; Opening Library Part Name: Janela 26; Opening Side Fill Index: Trama Vazia; Library Part Name: Janela 26; Building Material / Composite / Profile / Fill: Trama Vazia; Fill Type: Trama Vazia; Locked: no; Home Story Name: Terreo; Home Story Number: 0; Element Type: Window; Surfaces (All): Vidro - Simples; Metal - Alumínio; Position: Exterior; Show On Renovation Filter: All Relevant Filters; Structural Function: Non-Load-Bearing Element
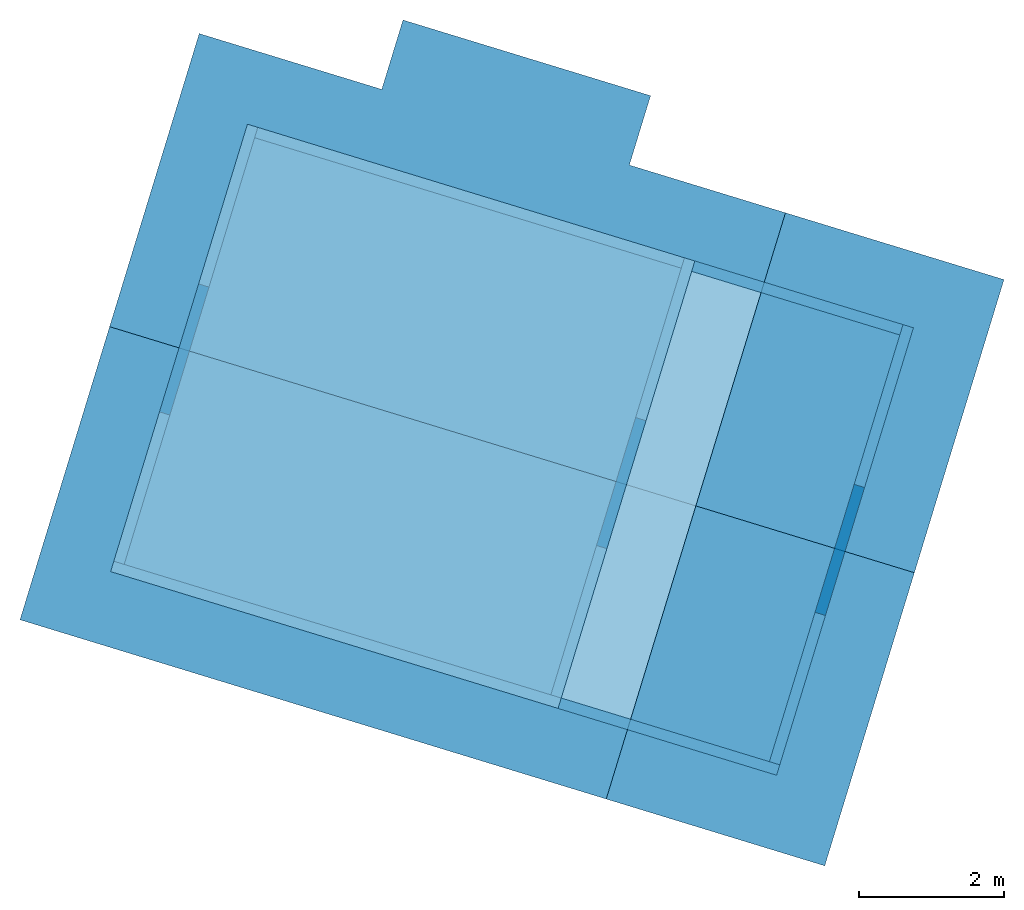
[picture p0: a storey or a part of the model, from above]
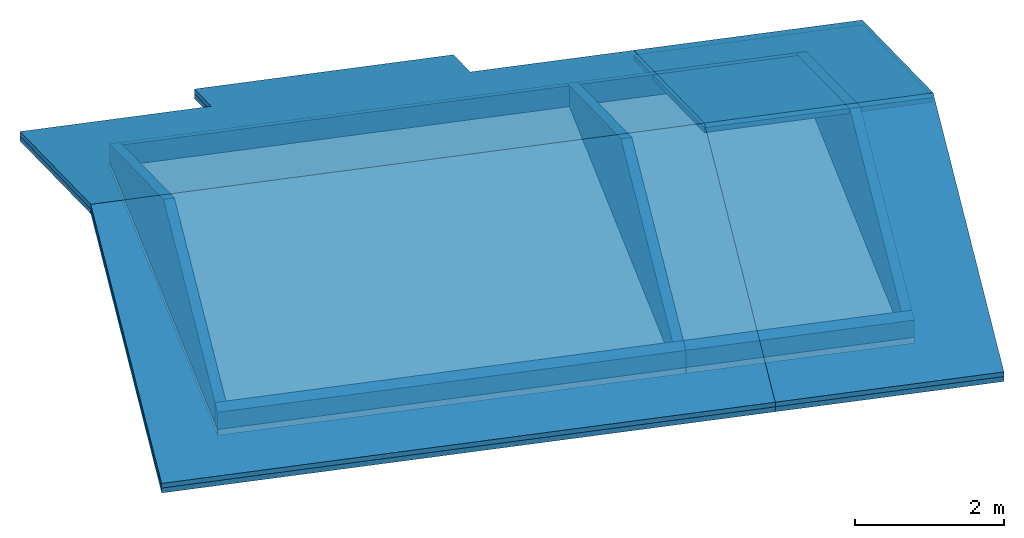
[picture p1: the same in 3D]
Properties of the parts of a building model (IFC2X3), part 7 of 7

# IfcWindow: Janela 26, J03
ArchiCADProperties - Reveal Dimensions: 0,84×0,80; Wallhole Dimensions: 0,84×0,80; Unit Dimensions: 0,84×0,80; Nominal W x H Size: 0,84×0,80; Nominal W x H x T Size: 0,84×0,80×0,15; Wall Structure: Bloco de Concreto - Estrutural; Opening Library Part Name: Janela 26; Opening Side Fill Index: Trama Vazia; Element ID: J03; Hotlink and Element ID: J03; Layer: CDHU-Parede; Library Part Name: Janela 26; Building Material / Composite / Profile / Fill: Trama Vazia; Fill Type: Trama Vazia; Related Zone Name: Banho; Related Zone Number: 04; Locked: no; Home Story Name: Terreo; Home Story Number: 0; Element Type: Window; Parent ID: Parede 01; Surfaces (All): Vidro - Simples; Metal - Alumínio; From Zone: Banho; From Zone Number: 04; Design Option Name: Main Model; Design Option Set Name: Main Model; Position: Interior; Show On Renovation Filter: All Relevant Filters; Structural Function: Non-Load-Bearing Element; Renovation Status: Existing; Design Option Status: Main Model; Design Option Set: Main Model
INFORMAÇÕES DO PRODUTO - Data de Aquisição: DD/MM/YYYY
AC_Pset_Janela_26 - Contornos Parede (0-Nenhum,1-Completo,2-Lado,3-Comprimento): 0; Pontos-Quentes 0-Nenhum,1-2D,2-3D,3-Todos: 3; Opção de Visualização em Planta: 3; Ângulo de Posição da Abertura: 0 deg; Furo tem Superfície Lateral Parede: yes; Furos em Divisão de Superfícies são Curvos em Paredes Curvas: no; Mostrar Pontos-Quentes 2D em 3D: yes; Tipo de Parede: 1; Tipo de Direção de Parede: 2; Posição de Ancoragem da Abertura: 1; Função de correção de erros de Janela de canto: no; Tipo de Posicionamento (1=CW,0=W): no; Corda: no; Demolição / Nova Construção: 1; Novo Tipo de Trama de Parede: Bloco; Nova Caneta de Trama de Parede: Geral - Geral; Nova Caneta de Fundo de Trama de Parede: Fundos - Cor 1; Mostrar nova construção na Parede: no; Tipo de linha de demolição: 4; Mostrar parâmetro Demolição / Novo: no; Função Janela de Canto: yes; Ângulo de Canto: 90 deg; Espess. Dif. Parede Conexão: no; Pilar de Canto: no; Canto 2: no; Ângulo do Canto 2: 90 deg; Dif. Conexões de Espessura Parede 2: no; Canto 1: no; Ângulo do Canto 1: 90 deg; Dif. Conexões de Espessura Parede 1: no; Tipo de Conexão 1 do Canto: 1; Tipo de Conexão 2 do Canto: 1; Inteiramente Editável: yes; 2D: 1; Mostrar Face de Vão em Símbolo: 2; 3D: 8; Tamanho Nominal: 0; Definir Tamanho de Vão como Tamanho Nominal: yes; Definir Tamanho de Reentrância como Tamanho Nominal: no; Definir Tamanho de Unidade como Tamanho Nominal: no; Transferir Tamanho Nominal Atual para Seleção: no; Painéis Horizontais: 1; Largura Uniforme Batente: yes; Bandeira Superior: no; Bandeira Superior Dividida: no; Bandeira Inferior: no; Bandeira Inferior Dividida: no; Painéis Verticais: 3; Caixilhos Uniformes: no; Direção do Vidro Fixo (FixGlassDir): Pela Direção da Abertura; Direção do Vidro Fixo (FixGlassDir_m): 1; Tipo Abertura Caixilho Principal: Presa Topo; Tipo Abertura (gs_optype_m_01): 8; Tipo Abertura (gs_optype_m_03): 1; Tipo Abertura Caixilho Travessa: Vidro Fixo; Tipo Abertura (gs_optype_m_02): 1; Tipo Caixilho (MullionStyle_00): Sem Grelha; Tipo Caixilho (iMullionStyle_00): 1; Tipo Caixilho Caixilho Principal: Sem Grelha; Tipo Caixilho (iMullionStyle_01): 1; Tipo Caixilho (iMullionStyle_03): 1; Tipo Caixilho Caixilho Travessa: Sem Montantes; Tipo Caixilho (iMullionStyle_02): 1; Painel Person. Espelhado (gs_bMirr_cust_panel_01): no; Painel Person. Espelhado (gs_bMirr_cust_panel2_01): no; Painel Person. Espelhado (gs_bMirr_cust_panel_03): no; Painel Person. Espelhado (gs_bMirr_cust_panel2_03): no; Painel Person. Espelhado (gs_bMirr_cust_panel_02): no; Painel Person. Espelhado (gs_bMirr_cust_panel2_02): no; Editar Ponto-quente Grelha: yes; Posição Grelha (MullionPosition): Por tudo; Posição Grelha (iMullionPosition): 3; Nº Paineis Verticais Caixilho Principal: 3; Nº Paineis Horizontais Caixilho Principal: 4; Nº Paineis Verticais 2 Caixilho Principal: 3; Nº Paineis Horizontais 2 Caixilho Principal: 4; Nº Paineis Verticais Caixilho Inferior: 1; Nº Paineis Horizontais Caixilho Inferior: 4; Nº Paineis Verticais 2 Caixilho Inferior: 1; Nº Paineis Horizontais 2 Caixilho Inferior 2: 4; Nº Paineis Verticais Caixilho Travessa: 1; Nº Paineis Horizontais Caixilho Travessa: 4; Nº Paineis Verticais 2 Caixilho Travessa: 1; Nº Paineis Horizontais 2 Caixilho Travessa: 4; Estilo Venezianas (iLouverStyle): 1; Ângulo de Abertura de Lanternins: 0 deg; Maçaneta Janela: no; Tipo Maçaneta Janela (gs_handle_type_win): Estilo 1; Tipo Maçaneta Janela (gs_handle_type_win_m): 1; Guarnição Externa: no; Tipo Guarnição Externa (gs_trimtype_out): Simples; Tipo Guarnição Externa (gs_trimtype_out_int): 1; Tipo de Travessa Guarnição Externa: 1; Arquitrave Principal: yes; Tipo Arquitrave Principal: 1; Guarnição Externa Inferior: yes; Guarnição/Alizar na Superfície Externa da Parede: yes; Larguras Uniformes da Guarnição (gs_trim_outside_uniform): no; Guarnição Interna: yes; Tipo Guarnição Interna (gs_trimtype_in): Simples; Tipo Guarnição Interna (gs_trimtype_in_int): 1; Guarnição/Alizar na Superfície Interna da Parede: yes; Larguras Uniformes da Guarnição (gs_trim_inside_uniform): yes; Soleira/Peitoril (gs_sill_outside): no; Sobredim. Peitoril: no; Tipo de Parapeito Exterior: 3; Ângulo Peitoril: 8 deg; Parapeito Curvo em Paredes Curvas: yes; Isolamento abaixo do Peitoril: yes; Usar Camada Isolamento de Parede: no; Nível Detalhe 3D Peitoril Tijolo: 1; Peitoril Interno (gs_board_inside): no; Ângulo Peitoril Int.: 0 deg; Peitoril Int. Curvado em Paredes Curvas: yes; Peitoril Int. em Paredes Poligonais: 1; Ventilação Natural: no; Tipo Ventilação Natural: 2; Caixilho Principal: yes; Caixilho Inferior: no; Caixilho Bandeira: no; Quebra-Sol: no; Tipo Quebra-Sol: 1; Tipos de Quebra-Sol Ativados: 126; Número de Paineis: 2; Número de Paineis 2: 1; Posição Painel (gs_shutter_panelPos): Simétrico; Posição Painel (gs_shutter_iPanelPos): 1; Altura Automática Veneziana: yes; Batente Extra: no; Tipo Cobertura (gs_slidingShutter_cover): Perfil-Z; Tipo Cobertura (gs_slidingShutter_iCover): 1; Direção de Empilham. (gs_foldingShutter_stacking): Dentro; Direção de Empilham. (gs_foldingShutter_iStacking): 1; Abrir em 3D: yes; Ângulo de abertura 3D: 180 deg; Mostrar Símbolo 2D: yes; Mostrar Linhas de Abertura no Símbolo: no; Tipo Painel (gs_shutPanel_type): Estilo 1; Tipo Painel (gs_shutPanel_iType): 1; Largura Base Batente Diferente: no; Largura Automática Veneziana: yes; Ângulo Grelha Ventilação: 30 deg; Nº Vãos Horiz.: 5; Nº Vãos Vert.: 8; Posição Rolamento Veneziana (gs_shutRoll_placement): Na Fachada; Posição Rolamento Veneziana (gs_shutRoll_iPlacement): 1; Tipo Caixa (gs_shutRoll_boxType): Rectangular; Tipo Caixa (gs_shutRoll_iBoxType): 1; Posição Grade (gs_shutRoll_railPos): Em Guarnição; Posição Grade (gs_shutRoll_iRailPos): 1; Mostrar Guarnição Atrás do Quebra-Sol (gs_shutRoll_showCasingBehind): no; Isolamento Atrás da Caixa (gs_shutRoll_cutWallBehind): no; Incluir Altura na Altura do Vão da Parede: no; Ângulo de Topo da Caixa: 10 deg; Largura Caixa Original (gs_shutRoll_boxDefaultSize): Largura Face de Vão; Largura Caixa Original (gs_shutRoll_iBoxDefaultSize): 1; Colocação Persianas (gs_shutLam_placement): Fixada na Fachada; Colocação Persianas (gs_shutLam_iPlacement): 1; Isolamento Atrás da Caixa (gs_shutLam_cutWallBehind): no; Caixa Aberta: yes; Trilho: yes; Posição Grade (gs_shutLam_railPos): Em Guarnição; Posição Grade (gs_shutLam_iRailPos): 1; Mostrar Guarnição Atrás do Quebra-Sol (gs_shutLam_showCasingBehind): no; Ângulo Rotação das Lamelas (gs_shutLam_rotation): 45 deg; Ângulo Rotação das Lamelas (gs_shutLam2_rotation): 45 deg; Arco de Alvenaria (bMasonryArch): no; Arco de Alvenaria (gs_masonry_arch_int): 2; Tipo de Arco de Alvenaria (gs_masonry_arch_structure): Arco de Reboco; Tipo de Arco de Alvenaria (gs_masonry_arch_structure_int): 1; Arco no Topo: yes; Nicho abaixo do Arco: yes; Ângulo de Plano do Arco: 75 deg; Superfícies dos Nichos Personalizados: no; Tipo de Requadro (gs_reveal_type_new): Requadro Reto - Borda; Tipo de Requadro (gs_reveal_type_int): 1; Tipo de Requadro Base (gs_reveal_type_bottom): Uniforme; Tipo de Requadro Base (gs_reveal_type_bottom_int): 1; Tipo de Requadro Exterior: Requadro Reto; Tipo de Requadro (gs_reveal_doubleOuterTypeInt): 0; Tipo de Requadro Interior: Requadro Reto; Tipo de Requadro (gs_reveal_doubleInnerTypeInt): 0; Profundidade Uniforme: yes; Ângulo Lado 2: 20 deg; Ângulo Lado: 20 deg; Ângulo do Topo: 20 deg; Ângulo da Base: 20 deg; Usar Componente de Acabamento: no; Auto Ligagem da Face Interna da Argamassa: yes; Ligar Face Interna da Argamassa: 0; Auto Ligagem da face Externa da Argamassa: yes; Ligar Face Externa da Argamassa: 0; Dimensionável em 2D: no; Mostrar em 3D: no; Tipo de Fechamento (gs_closure_type): Sem Fechamento; Tipo de Fechamento (gs_closure_type_int): 1; Dobrar Camada no Lado (gs_cavity_side): Ambas; Dobrar Camada no Lado (iCavityClosureSide): 1; No. de Camadas: 1; Numerar a partir de (gs_nTurnDir): Face externa; Numerar a partir de (iCavityClosureTurnDir): 1; Colocar Fechamento no Lado 2: yes; Colocar Fechamento no Lado 1: yes; Colocar Fechamento no Topo: no; Colocar Fechamento na Base: no; Colocar Fechamento para Camada: 1; Colocar Fechamento do Lado (gs_cc_dutch_ClosureToSide): 1; Fenda na Camada Externa: yes; Dobrar Camada para Encerram.: no; Inserir Camada de Isolamento: yes; Mostrar Camada de Isolamento: yes; Caneta de Contorno (gs_penJoint): Aberturas - Corte Não Estrutural; Tipo Linha Contorno (gs_ltJoint): 1; Tipo de Trama (gs_fillJoint): Isolamento 2; Caneta da Trama (gs_penJointFg): Geral - Geral; Caneta do Fundo da Trama (gs_penJointBg): Elementos 2D - Desenhos; Superfície Personalizada: no; Superfície: Madeira - Pinho Granulado Horizontal; Caneta de Contorno (gs_penPlug): Aberturas - Corte Não Estrutural; Tipo Linha Contorno (gs_ltPlug): 1; Tipo de Trama (gs_fillPlug): Isolamento 2; Caneta da Trama (gs_penPlugFg): Geral - Geral; Caneta do Fundo da Trama (gs_penPlugBg): Elementos 2D - Desenhos; Lado Ombreira Editado: 1; Lado Parede Editado: 1; Número de Camada Editado: 1; Camada que Dobra: no; Considerar Camada como Reboco: no; Espessura da Camada que Dobra: 1; Orientação Trama: 1; Linha Separa Camada que Dobra: no; Caneta Linha Separação: Geral - Geral; Último Lado Selecionado: no; Método de Fechamento Alterado Automaticamente: no; Conexão à Esquerda: no; Conexão à Direita: no; Conexão em Cima: no; Conexão em Baixo: no; Recorte na Parede: no; Tamanhos da Inserção na Parede (gs_parapet_sizes_st): Automático; Tamanhos da Inserção na Parede (iParapetSize): 1; Dimensões Autom. de Largura e Altura: yes; Inserção de Parede Embaixo a (gs_parapet_bottom_st): Piso Atual; Inserção de Parede Embaixo a (iParapetBottom): 1; Mostrar Parapeito Escondido: yes; Tipo Linha Peitoril Escondido: 1; Ângulo de Abertura Caixilho Principal (openingAngle_01): 9.93923e-16 deg; Ângulo de Abertura Caixilho Principal (openingAngle2_01): 0 deg; Ângulo de Abertura Caixilho Inferior (openingAngle_03): 0 deg; Ângulo de Abertura Caixilho Inferior (openingAngle2_03): 0 deg; Ângulo de Abertura Caixilho Travessa (openingAngle_02): 0 deg; Ângulo de Abertura Caixilho Travessa (openingAngle2_02): 0 deg; Ângulo Abertura 2D: 0 deg; Substituir OVM para Visual. Simbólica 2D: no; Tipo Linha Abertura: 1; Forma da Linha de Abertura (or_SwingType): Curva; Forma da Linha de Abertura (or_iSwingType): 1; Forma da Linha de Abertura (or_SlidingType): Nenhum; Forma da Linha de Abertura (or_iSlidingType): 0; Caneta de Linha de Abertura em 2D/3D (or_opLinePen): Aberturas - Geral; Caneta de Linha de Abertura em 2D/3D (or_iOpLinePen): 3; Substituir OVM para Projeções 3D: no; Mostrar Linha de Abertura: yes; Tipo Linha Lado da Abertura (or_opLineType3dIn): Linha Sólida; Tipo Linha Lado da Abertura (or_iOpLineType3dIn): 0; Tipo Linha Lado Oposto (or_opLineType3dOut): Linha Sólida; Tipo Linha Lado Oposto (or_iOpLineType3dOut): 0; Orientação da Linha (or_oplineStyle): Maçaneta; Orientação da Linha (or_iOplineStyle): 1; Caneta de Linha em Vista: Aberturas - Geral; Caneta da Linha em Corte: Aberturas - Moldura; Caneta de Linha em Corte em Ambos os Lados da Guarnição: Aberturas - Geral; Linha Contorno Parede (gs_wcont_line): Ambos Lados; Linha Contorno Parede (iWallContourLine): 4; Tipo de Linha Interior Contorno Parede: 1; Tipo de Linha Exterior Contorno Parede: 1; Linha Interna Tracejada de Projeção Parede: 4; Linha Externa Tracejada de Projeção Parede: 4; Caneta Linha Contorno Parede: Aberturas - Geral; Tramas Usadas: yes; Tipo Trama Batente: Trama Vazia; Caneta Trama Batente: Aberturas - Fundo de Trama; Caneta Fundo Trama Batente: Aberturas - Fundo de Trama; Tipo de Trama Caixilho: Ar (Vazio); Caneta da Trama Caixilho: Aberturas - Fundo de Trama; Caneta da Trama de Fundo Divisões Interiores: Fundos - Cor 1; Tipo de Trama de Não-Cortado: Trama Vazia; Caneta da Trama de Não-Cortado: Aberturas - Fundo de Trama; Caneta de Fundo da Trama Não-Cortado: Aberturas - Fundo de Trama; Tipo Trama Símbolo em Planta: Trama Vazia; Caneta Trama para Símb. em Planta: Aberturas - Fundo de Trama; Caneta Fundo para Simb. em Planta: Aberturas - Fundo de Trama; Caneta de Vista e 3D da Peitoril: Geral - Geral; Caneta de Contorno de Corte Peitoril: Aberturas - Corte Não Estrutural; Tipo de Trama Corte Peitoril: Trama Vazia; Caneta Trama do Parapeito em Corte: Aberturas - Fundo de Trama; Caneta Trama de Fundo do Parapeito em Corte: Aberturas - Fundo de Trama; Caneta de Contorno Isolamento Seção: Aberturas - Corte Não Estrutural; Tipo de Trama do Isolamento da Seção: Isolamento 2; Caneta Trama Isolamento Seção: Aberturas - Fundo de Trama; Caneta da Trama de Fundo Isolamento Seção: Aberturas - Fundo de Trama; Caneta de Vista e 3D do Peitoril Interno: Geral - Geral; Caneta de Contorno Seção Peitoril Interno: Geral - Geral; Tipo de Trama do Peitoril Interno em Corte: Trama Vazia; Caneta Trama do Peitoril Interno em Corte: Fundos - Cor 1; Caneta Trama de Fundo do Peitoril Interno em Corte: Fundos - Cor 1; Tipo de Trama de Guarnição Int.: Trama Vazia; Caneta de Trama de Guarnição Int: Aberturas - Fundo de Trama; Caneta de Fundo de Trama de Guarnição Int: Aberturas - Fundo de Trama; Tipo de Trama de Guarnição Ext: Trama Vazia; Caneta de Trama de Guarnição Ext: Fundos - Cor 1; Caneta de Fundo de Trama de Guarnição Ext: Fundos - Cor 1; Tipo de Trama de Seção do Arco: Trama Vazia; Caneta da Trama da Seção do Arco: Fundos - Cor 1; Caneta de Fundo de Trama de Seção do Arco: Fundos - Cor 1; Tipo de Trama do Corte do Perfil da Ventilação: Ar (Vazio); Caneta da Trama do Corte do Perfil da Ventilação: Fundos - Cor 1; Caneta do Fundo da Trama do Corte do Perfil da Ventilação: Fundos - Cor 1; Tipo de Linha de Símbolo Quebra-Sol: 1; Caneta da Linha em Corte do Quebra-Sol: Geral - Geral; 3D/Caneta das Linhas não Cortadas no Corte: Geral - Geral; Tipo da Trama de Corte Quebra-Sol (gs_sunShade_cutFillType): Trama Vazia; Tipo da Trama de Corte Quebra-Sol (gs_sunShade_cutFillPen): Geral - Geral; Caneta da Trama do Fundo Corte Quebra-Sol: Window Background; Tipo Trama Isolamento Quebra-Sol: Trama Vazia; Caneta da Trama Isolamento Quebra-Sol: Geral - Geral; Caneta do Fundo Isolamento Quebra-Sol: Window Background; Junção Elementos Batente: 2; Caneta Moldura: Aberturas - Geral; Caneta Caixilho: Aberturas - Geral; Caneta Vidro: Aberturas - Fundo de Trama; Caneta de Arco de Alvenaria: Paredes - Geral; Sombra: yes; Superfícies Uniformes Janela: yes; Batente Externo: Metal - Alumínio; Batente Interno: Metal - Alumínio; Caixilho Externo: Metal - Alumínio; Caixilho Interno: Metal - Alumínio; Persianas: Madeira - Pinho Granulado Horizontal; Vidro: Vidro - Simples; Grelha Externa: Metal - Alumínio; Grelha Interna: Metal - Alumínio; Painel Sólido Exterior: Metal - Alumínio; Painel Sólido Interior: Metal - Alumínio; Maçaneta: Metal - Aço Inoxidável; Superfícies Guarnição Uniformes: no; Interior Guarnição: Metal - Alumínio; Exterior Guarnição: Metal - Alumínio; Perfil de Ventilação: Metal - Alumínio; Painel Veneziana: Madeira - Pinho Granulado Horizontal; Moldura Painel Veneziana: Madeira - Pinho Granulado Horizontal; Caixa do Rolamento Veneziana: Metal - Aço Inoxidável; Lâminas Rolamento Veneziana: Pintura - Branco Titânio; Barras Rolamento Veneziana: Pintura - Branco Titânio; Caixa Persianas: Metal - Aço Inoxidável; Segmento Persianas: Pintura - Branco Titânio; Trilho Deslizante Veneziana: Metal - Aço Inoxidável; Soleira/Peitoril (gs_sill_mat): Pedra - Granito Cinza; Argamassa do Peitoril em Tijolo: Estuque - Branco Áspera; Peitoril Interno (gs_board_mat): Pedra - Granito Cinza; Arco de Alvenaria em Tijolo: Tijolo - Aparelho ao Comprido; Argamassa do Arco de Alvenaria: Estuque - Branco Áspera; Fecho Arco de Alvenaria: Pedra - Arenito 01; Nincho: Pintura - Óxido de Chumbo Amarelo; Superfície de Pilar de Canto: Metal - Alumínio; Direção da Abertura: 1; Visualizar como Travessa: no; Caneta Linha Fim Parede: Geral - Geral; Tipo de Linha Fim de Parede: 4; Profundidade Travessa em Símbolo: no; Tipo de Linha do Símbolo da Profundidade Travessa: 4; Caneta do Símbolo da Profundidade Travessa: Texto - Geral; Janela pertence à Zona dentro da qual abre: no; Custo: 0; Área Total Envidraçada (gs_list_glassarea_tmp): 0; Substituir Área Envidraçada: yes; Área Total Envidraçada (gs_list_glassarea): 0; Perimetro Total Vidro: 0; Desempenho Ar Livre (mm2/l/m): 0; Tipo de Grupo (FM_Type): Objetos padrão; Tipo de Grupo (iFMType): 1; Peso Objeto: 0; Unidade Peso Objeto: kg; Definição de Orientação Janela: 0; Operação IFC (ifc_optypestr): Simples; Operação IFC (ifc_optype): 1; Ângulo de Abertura Veneziana: 180 deg; Estilo Linha de Abertura: 2
ZONAS - Iluminação Mínima: 0; Ventilação Mínima: 0
FABRICAÇÃO - Data de Fabricação: DD/MM/YYYY; Site do Produto: www.graphisoft.com
ABERTURAS - Tipo de Abertura: Basculante; Material: Alumínio; Vidro
GARANTIA - Ínicio da Garantia: DD/MM/YYYY; Fim da Garantia: DD/MM/YYYY
PISOS (Expressão) - Índice de Perda (%): 10
REVESTIMENTO DE PAREDE POR ZONA (Expressão) - Número de Linhas: 10; DImensão 1: 0 mm; Dimensão 2: 0 mm; Largura do Rejunte: 10 mm; Altura do Revestimento: 100 mm
ILUMINAÇÃO E VENTILAÇÃO (Expressão) - Atende: Atende; Não Atende: Não Atende
RODAPÉ (Expressão) - Comprimento da Barra (m): 2.4; Custo da Barra: 0
ESTRUTURA (Expressão) - Custo por Volume (m3): 0
COBERTURA (Expressão) - Rendimento de Telha Genérica (m2): 0; Índice de Perda Telhas (%): 0; Rendimento Cumeeira (ml): 0
ArchiCADQuantities - W/D Opening Opening Volume: 0.1008 m3; W/D Opening Nominal Volume: 0.1008 m3; W/D Opening Surface Area: 3.20431 m2; W/D Opening Nominal Surface Area: 0.672 m2; W/D Opening Width on the Reveal Side: 840 mm; W/D Opening Height on the Reveal Side: 800 mm; W/D Opening Width on the Side Opposite to the Reveal Side: 840 mm; W/D Opening Height on the Side Opposite to the Reveal Side: 800 mm; W/D Opening Surface Area on the Reveal Side: 0.672 m2; W/D Opening Surface Area on the Side Opposite to the Reveal Side: 0.672 m2; Nominal W/D Opening Width on the Reveal Side: 840 mm; Nominal W/D Opening Height on the Reveal Side: 800 mm; Nominal W/D Opening Width on the Side Opposite to the Reveal Side: 840 mm; Nominal W/D Opening Height on the Side Opposite to the Reveal Side: 800 mm; Nominal W/D Opening Surface Area on the Reveal Side: 0.672 m2; Nominal W/D Opening Surface Area on the Side Opposite to the Reveal Side: 0.672 m2; Sill/Header Value: 1400 mm; W/D Nominal Sill Height: 1400 mm; W/D Sill Height on the Reveal Side: 1400 mm; W/D Sill Height on the Side Opposite to the Reveal Side: 1400 mm; W/D Nominal Head Height: 2200 mm; W/D Head Height on the Reveal Side: 2200 mm; W/D Head Height on the Side Opposite to the Reveal Side: 2200 mm; Wall Thickness: 150 mm; Frame Thickness: 50 mm; Height: 800 mm; Volume (Net): 0.018413 m3; Width: 840 mm; Elevation to Project Zero: 1400 mm; Elevation to 1º Nível de Referência: 1400 mm; Elevation to 2º Nível de Referência: 1400 mm; Elevation to Sea Level: 729620 mm; Elevation to Linked/Home Story: 1400 mm; Home Offset: 1400 mm; Surface Area: 3.20431 m2; Top Elevation To First Reference Level: 2215 mm; Top Elevation To Home Story: 2215 mm; Top Elevation To Project Zero: 2215 mm; Top Elevation To Sea Level: 730435 mm; Top Elevation To Second Reference Level: 2215 mm; Bottom Elevation To First Reference Level: 1385 mm; Bottom Elevation To Home Story: 1385 mm; Bottom Elevation To Project Zero: 1385 mm; Bottom Elevation To Sea Level: 729605 mm; Bottom Elevation To Second Reference Level: 1385 mm; Bottom Surface Area (Net): 3.20431 m2
EXPRESSÕES DE TEXTO (Expressão) - Localização do Produto no Projeto: Projeto: Casa Térrea IsoladaLocal: Piso: Terreo Cômodo: Banho; ID de Aberturas com Master ID: 04J03; ID Dinâmico por Classificação: Janela -J03
DESCRIÇÃO DA ESCADA (Expressão) - Abreviação da Largura da Escada: L; Abreviação da Altura do Espelho: E; Abreviação da Profundidade do Piso: P
AC_Equantity_Janela_26 - Largura: 840 mm; Altura: 800 mm; Dimensão Z: 1000 mm; Nível da Base: 1000 mm; Nível do Topo: 0 mm; Altura Peitoril ao Piso Atual: 1400 mm; Abertura para o Núcleo da Parede: 0 mm; Nova Largura Direita da Trama de Parede: 150 mm; Nova Largura Esquerda da Trama de Parede: 150 mm; Espessura Parede Ligação: 0 mm; Espessura Parede 2 Conectada: 150 mm; Espessura Parede 1 Conectada: 150 mm; Largura Pilar de Canto: 0 mm; Espessura Pilar Canto: 0 mm; Projeção Pilar de Canto: 0 mm; Tolerância Máxima: 100 mm; Tolerância: 0 mm; Tolerância Esquerda: 0 mm; Tolerância Direita: 0 mm; Tolerância Superior: 0 mm; Tolerância Inferior: 0 mm; Largura de Vão: 840 mm; Altura de Vão: 800 mm; Largura Face de Vão: 840 mm; Altura Face de Vão: 800 mm; Largura Unidade: 840 mm; Altura Unidade: 800 mm; Largura Painel Lado: 0 mm; Largura Painel Meio: 420 mm; Espessura Batente: 50 mm; Largura Batente: 35 mm; Largura Batente Lado 2: 47 mm; Largura Batente Cimo: 47 mm; Largura Batente Base: 47 mm; Profundidade Rebaixo: 20 mm; Largura Rebaixo: 20 mm; Largura Divisão Superior: 100 mm; Altura Divisões Sup. Horiz.: 453 mm; Largura Divisão Inferior: 100 mm; Altura Divisões Inf. Horiz: 330 mm; Largura Montante Lado 1: 100 mm; Largura Montante Lado 2: 100 mm; Altura Divisão Horizontal Caixilho Principal: 355 mm; Altura Divisão Horizontal Caixilho Inferior: 900 mm; Altura Divisão Horizontal Caixilho Travessa: 900 mm; Espessura Estrutura Caixilho: 20 mm; Largura Caixilho: 50 mm; Largura Grelha: 20 mm; Espessura Grelha: 25 mm; Espessura Vidro: 20 mm; Espessura Venezianas: 10 mm; Largura Venezianas: 50 mm; Sobred. Abertura Esquerda: 0 mm; Sobred. Direita Abertura: 0 mm; Sobred. Topo Abertura: 0 mm; Sobred. Base Abertura: 0 mm; Largura Arquitrave Principal: 20 mm; Largura Lado 1 (gs_tw_right_out): 100 mm; Largura Lado 2 (gs_tw_left_out): 100 mm; Largura Topo (gs_tw_top_out): 100 mm; Largura Inferior (gs_tw_bottom_out): 100 mm; Espessura de Parede (gs_trim_thk_out): 25 mm; Espessura na Abertura da Parede (gs_trim_width_out): 25 mm; Paralelas (gs_trim_offs_out): 0 mm; Bordo (gs_trim_jambext_nosing_out): 50 mm; Saliência Superior (gs_trimov_top_left_out): 0 mm; Saliência Superior (gs_trimov_top_right_out): 0 mm; Ressalto Inferior (gs_trimov_bot_left_out): 0 mm; Ressalto Inferior (gs_trimov_bot_right_out): 0 mm; Ressalto Inferior (casingOverhangBottomSideOut): 50 mm; Largura Lado 1 (gs_tw_right_in): 40 mm; Largura Lado 2 (gs_tw_left_in): 100 mm; Largura Topo (gs_tw_top_in): 100 mm; Largura Inferior (gs_tw_bottom_in): 100 mm; Espessura de Parede (gs_trim_thk_in): 25 mm; Espessura na Abertura da Parede (gs_trim_width_in): 25 mm; Paralelas (gs_trim_offs_in): 0 mm; Bordo (gs_trim_jambext_nosing_in): 50 mm; Saliência Superior (gs_trimov_top_left_in): 0 mm; Saliência Superior (gs_trimov_top_right_in): 0 mm; Ressalto Inferior (gs_trimov_bot_left_in): 0 mm; Ressalto Inferior (gs_trimov_bot_right_in): 0 mm; Largura Peitoril: 60 mm; Largura Topo Parapeito: 10 mm; Altura Topo Peitoril: 10 mm; Espessura Peitoril: 30 mm; Espessura Lateral da Frente Peitoril: 15 mm; Elevação Peitoril: 5 mm; Recobrimento Goteira Peitoril: 20 mm; Largura Goteira Peitoril: 30 mm; Testeira Peitoril: 25 mm; Avanço do Parapeito Esquerda: 0 mm; Avanço do Parapeito Direita: 0 mm; Inclinação do Parapeito: 35 mm; Inclin. Peitoril da Parede: 0 mm; Profund. Vão Posterior (gs_sill_holeDepthBehind): 0 mm; Espessura do Tijolo (gs_brick_sill_br_thk): 65 mm; Espessura de Argamassa (gs_brick_sill_mort_thk): 15 mm; Largura Peitoril Int.: 125 mm; Espessura Peitoril Int.: 25 mm; Peitoril Int. Arredondado: 25 mm; Saliência Esq. Peitoril Int.: 0 mm; Saliência Dir. Peitoril Int.: 0 mm; Inclinação do Parapeito Int.: 0 mm; Altura Perfil: 65 mm; Espessura Perfil: 110 mm; Altura Painel: 1500 mm; Afast. Interior: 20 mm; Profund. Fechamento: 0 mm; Largura Batente Extra: 40 mm; Espess. Batente Extra: 30 mm; Largura Barra:: 30 mm; Comprim. Vara Suspensa: 20 mm; Raio Vara Suspensa: 5 mm; Distância Painel: 6 mm; Saliência Exterior: 0 mm; Largura Painel Interior: 120 mm; Comprim. Abertura 3D: 1500 mm; Comprim. Fechado 3D: 0 mm; Comprimento 1 Abertura 3D (gs_shutter_opLength_1): 560 mm; Comprimento 1 Abertura 3D (gs_shutter_opLength_2): 140 mm; Altura Abertura 3D: 1500 mm; Altura Fechado 3D: 0 mm; Espessura Painel: 50 mm; Largura Estrutura Painel: 50 mm; Largura Moldura Inferior: 50 mm; Largura Painel: 0 mm; Espess. de Enchimento de Painel: 10 mm; Espessura da Veneziana: 10 mm; Largura Grelha Ventilação: 40 mm; Largura Divisor Moldura Horiz.: 50 mm; Largura de Divisor Moldura Vert.: 50 mm; Raio do Vão: 10 mm; Largura Bordo Vertical: 100 mm; Largura Estrutura Z: 50 mm; Espessura Estrutura Z: 25 mm; Espess. Placas Verticais: 25 mm; Espess. Placas Horizontais: 25 mm; Largura Aprox. Placas Verticais: 80 mm; Largura Aprox. Placas Horizontais: 115 mm; Altura Caixa (gs_shutRoll_boxHeight): 200 mm; Profund. Caixa (gs_shutRoll_boxWidth): 150 mm; Afast. Caixa Esq.: 0 mm; Afast. Caixa Dir.: 0 mm; Profund. Anteparos: 72.5 mm; Distância da Parede (gs_shutRoll_distFromWall): 0 mm; Distância da Padieira (gs_shutRoll_distFromHead): 0 mm; Largura da Ripa: 50 mm; Altura Caixa (gs_shutLam_boxHeight): 200 mm; Profund. Caixa (gs_shutLam_boxWidth): 150 mm; Largura Capa: 0 mm; Distância da Parede (gs_shutLam_distFromWall): 0 mm; Distância da Padieira (gs_shutLam_distFromHead): 0 mm; Largura Segmento (gs_shutLam_segmentWidth): 60 mm; Altura Caixa (gs_shutLam2_boxHeight): 60 mm; Largura Caixa: 60 mm; Distância da Janela: 60 mm; Distância da Padieira (gs_shutLam2_distFromHead): 60 mm; Altura do Eixo da Caixa da Padieira: 0 mm; Largura Segmento (gs_shutLam2_segmentWidth): 60 mm; Distância entre Arco e Janela: 0 mm; Avanço à Esquerda do Arco de Alvenaria: 0 mm; Avanço à Direita do Arco de Alvenaria: 0 mm; Espelho do Arco de Alvenaria: 30 mm; Projeção do Arco de Alvenaria: 0 mm; Altura do Arco de Alvenaria: 250 mm; Profundidade do Arco de Alvenaria: 120 mm; Profund. Vão Posterior (gs_masonry_arch_rearHoleDepth): 0 mm; Espessura do Tijolo (gs_masonry_arch_brick_thk): 65 mm; Espessura de Argamassa (gs_masonry_arch_mort_thk): 10 mm; Largura Fecho: 100 mm; Sobredimensão Fecho: 0 mm; Projeção Fecho: 10 mm; Profund. Face de Vão (gs_wido_sill): 0 mm; Profund. Face de Vão (AC_wido_sill): 0 mm; Profund. Ombreira Lado 2: 60 mm; Profund. Ombreira: 60 mm; Profund. Ombreira Interior Lado 2 (gs_reveal_splayed_innerLeft): 60 mm; Profund. Ombreira Interior (gs_reveal_splayed_innerRight): 60 mm; Profund. Ombreira Interior Lado 2 (gs_reveal_double_innerLeft): 60 mm; Profund. Ombreira Interior (gs_reveal_double_innerRight): 60 mm; Profund. Batente Cima: 60 mm; Profund. Batente Peitoril: 60 mm; Profundidade Padieira Interior (gs_reveal_splayed_innerTop): 60 mm; Profundidade Peitoril Interior (gs_reveal_splayed_innerBottom): 60 mm; Profundidade Padieira Interior (gs_reveal_double_innerTop): 60 mm; Profundidade Peitoril Interior (gs_reveal_double_innerBottom): 0 mm; Profund. Batente Exterior: 80 mm; Limite Espess. Reboco: 40 mm; Distância de Camada do Encerram.: 0 mm; Largura do Fecho: 38 mm; Espessura do Fecho: 100 mm; Espessura da Camada: 25 mm; Espessura do Perfil: 75 mm; Espessura Personal.: 15 mm; Saliência Camada para Espess. Batente: 0 mm; Profundidade do Recorte: 50 mm; Largura de Parapeito: 1000 mm; Avanço Lateral 1: 0 mm; Avanço Lateral 2: 0 mm; Altura Parapeito: 900 mm; Ressalto Inferior (gs_parapet_botelev): 0 mm; Distância Abertura 1 Caixilho Principal: 0 mm; Distância Abertura 2 Caixilho Principal: 0 mm; Distância Abertura 1 Caixilho Inferior: 0 mm; Distância Abertura 2 Caixilho Inferior: 0 mm; Distância Abertura 1 Bandeira Caixilho: 0 mm; Distância Abertura 2 Bandeira Caixilho: 0 mm; Comprimento Abertura em 2D: 0 mm; Sobred. Abertura Esq. AC: 0 mm; Sobred. Abertura Dir. AC: 0 mm; Sobred. Padieira AC: 0 mm; Sobred. Abertura Base AC: 0 mm
BaseQuantities - GrossArea: 0.672 m2; Height: 800 mm; Width: 840 mm; Perimeter: 3280 mm; Area: 0.672 m2; Volume: 0.018413 m3; Depth: 150 mm; NetVolume: 0.018413 m3
ALVENARIAS (Expressão) - Espessura da Argamassa: 10 mm
Component Quantities - Component, Component Volume (Net): 0.018413 m3; Component, Component Volume (Gross): 0.018413 m3

# IfcWindow: Vertical Multi-Sash Window 27, J02
In: Terreo
Type - OperationType: USERDEFINED; ParameterTakesPrecedence: no; Sizeable: no
Description: Janela basculante em aluminio; OverallHeight: 1200 mm; OverallWidth: 840 mm; Classification: Janela (Classificação ARCHICAD); 3E 20 04 02 06 Janela basculante (NBR 15965-5 3E)
Pset_WindowCommon - ThermalTransmittance: 0; IsExternal: no
ArchiCADProperties - Reveal Dimensions: 0,84×1,20; Wallhole Dimensions: 0,84×1,20; Unit Dimensions: 0,84×1,20; Nominal W x H Size: 0,84×1,20; Nominal W x H x T Size: 0,84×1,20×0,15; Wall Structure: Bloco de Concreto - Estrutural; Opening Library Part Name: Vertical Multi-Sash Window 27; Opening Side Fill Index: Trama Vazia; Element ID: J02; Hotlink and Element ID: J02; Layer: CDHU-Parede; Library Part Name: Vertical Multi-Sash Window 27; Building Material / Composite / Profile / Fill: Trama Vazia; Fill Type: Trama Vazia; Related Zone Name: Sala / Cozinha; Related Zone Number: 01; Locked: no; Home Story Name: Terreo; Home Story Number: 0; Element Type: Window; Parent ID: Parede 01; Surfaces (All): Vidro - Simples; Metal - Alumínio; To Zone: Sala / Cozinha; To Zone Number: 01; Design Option Name: Main Model; Design Option Set Name: Main Model; Position: Interior; Show On Renovation Filter: All Relevant Filters; Structural Function: Non-Load-Bearing Element; Renovation Status: Existing; Design Option Status: Main Model; Design Option Set: Main Model
GARANTIA - Ínicio da Garantia: DD/MM/YYYY; Fim da Garantia: DD/MM/YYYY
AC_Pset_Vertical_Multi-Sash_Window_27 - Wall Contours (0-None,1-Full,2-Side,3-Length): 1; Hotspots 0-None,1-2D,2-3D,3-All: 3; Floor Plan Display Option: 2; Hole Position Angle: 0 deg; Hole has Wall's Side Surface: yes; Hole Surface's Split is Curved in Curved Walls: no; Show 2D Hotspots in 3D: yes; Wall Type: 1; Wall Direction Type: 2; Reveal Anchor Position: 1; Corner Window Debug Function: no; Placement Type (1=CW,0=W): no; Flip: no; Demolition / New construction: 1; New Wall Fill Type: Bloco; New Wall Fill Pen: Geral - Geral; New Wall Fill Background Pen: Fundos - Cor 1; Show new construction on Wall: no; Demolition line type: 4; Show Demolition/New parameter: no; Corner Window Function: yes; Corner Angle: 90 deg; Diff. Conn. Wall Thickness: no; Corner Column: no; Corner 2: no; Corner Angle 2: 90 deg; Diff. Conn. Wall Thickness 2: no; Corner 1: no; Corner Angle 1: 90 deg; Diff. Conn. Wall Thickness 1: no; Corner Connection Type 1: 1; Corner Connection Type 2: 1; Sash to Show on Symbol (gs_ShowSashOnSymbol): 1. Sash; Sash to Show on Symbol (gs_iShowSashOnSymbol): 1; Fully Editable: yes; 2D Detail Level: 1; Show Reveal on Symbol: 2; 3D Detail Level: 8; Nominal Size: 0; Set Wallhole Size as Nominal Size: yes; Set Reveal Size as Nominal Size: no; Set Unit Size as Nominal Size: no; Transfer Current Nominal Size to Selection: no; Panes Number: 6; Multiply Unit: no; Number of Copies: 2; Keep Axis Distance: yes; Panes Vertical: 1; Uniform Frame Width: yes; Uniform Sashes: yes; Fixed Glass Direction (FixGlassDir): By Opening Direction; Fixed Glass Direction (FixGlassDir_m): 1; Opening Type Sash 1: Fixed Glass; Opening Type (gs_optype_m_01): 1; Opening Type Sash 2: Fixed Glass; Opening Type (gs_optype_m_02): 1; Opening Type Sash 3: Reversible Horizontal; Opening Type (gs_optype_m_03): 9; Opening Type Sash 4: Reversible Horizontal; Opening Type (gs_optype_m_04): 9; Opening Type Sash 5: Reversible Horizontal; Opening Type (gs_optype_m_05): 9; Opening Type Sash 6: Fixed Glass; Opening Type (gs_optype_m_06): 1; Opening Type Sash 7: Vidro Fixo; Opening Type (gs_optype_m_07): 1; Opening Type Sash 8: Vidro Fixo; Opening Type (gs_optype_m_08): 1; Opening Type Sash 9: Vidro Fixo; Opening Type (gs_optype_m_09): 1; Opening Type Sash 10: Vidro Fixo; Opening Type (gs_optype_m_10): 1; Sash Type (MullionStyle_00): No Grid; Sash Type (iMullionStyle_00): 1; Sash Type Sash 1: No Grid; Sash Type (iMullionStyle_01): 1; Sash Type Sash 2: No Grid; Sash Type (iMullionStyle_02): 1; Sash Type Sash 3: No Grid; Sash Type (iMullionStyle_03): 1; Sash Type Sash 4: No Grid; Sash Type (iMullionStyle_04): 1; Sash Type Sash 5: No Grid; Sash Type (iMullionStyle_05): 1; Sash Type Sash 6: No Grid; Sash Type (iMullionStyle_06): 1; Sash Type Sash 7: Sem Grade; Sash Type (iMullionStyle_07): 1; Sash Type Sash 8: Sem Grade; Sash Type (iMullionStyle_08): 1; Sash Type Sash 9: Sem Grade; Sash Type (iMullionStyle_09): 1; Sash Type (iMullionStyle_10): 1; Hotspot Grill Editing: yes; Grid Position (MullionPosition): Throughout; Grid Position (iMullionPosition): 3; Panes Number Vertically Sash 1: 3; Panes Number Horizontally Sash 1: 4; Panes Number Vertically 2 Sash 1: 3; Panes Number Horizontally 2 Sash 1: 4; Panes Number Vertically Sash 2: 1; Panes Number Horizontally Sash 2: 4; Panes Number Vertically 2 Sash 2: 1; Panes Number Horizontally 2 Sash 2: 4; Panes Number Vertically Sash 3: 1; Panes Number Horizontally Sash 3: 4; Panes Number Vertically 2 Sash 3: 1; Panes Number Horizontally 2 Sash 3: 4; Panes Number Vertically Sash 4: 2; Panes Number Horizontally Sash 4: 2; Panes Number Vertically 2 Sash 4: 2; Panes Number Horizontally 2 Sash 4: 2; Panes Number Vertically Sash 5: 2; Panes Number Horizontally Sash 5: 2; Panes Number Vertically 2 Sash 5: 2; Panes Number Horizontally 2 Sash 5: 2; Panes Number Vertically Sash 6: 2; Panes Number Horizontally Sash 6: 2; Panes Number Vertically 2 Sash 6: 2; Panes Number Horizontally 2 Sash 6: 2; Panes Number Vertically Sash 7: 2; Panes Number Horizontally Sash 7: 2; Panes Number Vertically 2 Sash 7: 2; Panes Number Horizontally 2 Sash 7: 2; Panes Number Vertically Sash 8: 2; Panes Number Horizontally Sash 8: 2; Panes Number Vertically 2 Sash 8: 2; Panes Number Horizontally 2 Sash 8: 2; Panes Number Vertically Sash 9: 2; Panes Number Horizontally Sash 9: 2; Panes Number Vertically 2 Sash 9: 2; Panes Number Horizontally 2 Sash 9: 2; Panes Number Vertically Sash 10: 2; Panes Number Horizontally Sash 10: 2; Panes Number Vertically 2 Sash 10: 2; Panes Number Horizontally 2 Sash 10: 2; Louvers Style (iLouverStyle): 1; Opening Angle of Louvers: 0 deg; Window Handle: no; Window Handle Type (gs_handle_type_win): Style 1; Window Handle Type (gs_handle_type_win_m): 1; Casing Outside: no; Casing Type Outside (gs_trimtype_out): Simple; Casing Type Outside (gs_trimtype_out_int): 1; Outside Casing Head Type: 1; Architrave Capital: yes; Architrave Capital Type: 1; Outside Bottom Casing: no; Cover Outer Wall Surface: yes; Uniform Casing Widths (gs_trim_outside_uniform): no; Casing Inside: no; Casing Type Inside (gs_trimtype_in): Simple; Casing Type Inside (gs_trimtype_in_int): 1; Cover Inner Wall Surface: yes; Uniform Casing Widths (gs_trim_inside_uniform): no; Sill (gs_sill_outside): no; Sill Oversize: no; Type of the Sill: 3; Sill Angle: 1.15 deg; Sill is Curved in Curved Walls: yes; Insulation below Sill: yes; Use Wall Insulation Skin: no; Brick Sill 3D Detail Level: 1; Board (gs_board_inside): no; Board Angle: 0 deg; Board is Curved in Curved Walls: yes; Board in Polygonal Walls: 1; Natural Ventilation: no; Natural Ventilation Type: 2; Sash 1: yes; Sash 2: no; Sash 3: no; Sash 4: yes; Sash 5: no; Sash 6: no; Sash 7: no; Sash 8: no; Sash 9: no; Sash 10: no; Sunshade: no; Sunshade Type: 1; Enabled Sunshade Types: 126; Number of Panels: 2; Number of Panels 2: 1; Panel Position (gs_shutter_panelPos): Simétrico; Panel Position (gs_shutter_iPanelPos): 1; Automatic Shutter Height: yes; Extra Frame: no; Cover Type (gs_slidingShutter_cover): Perfil-Z; Cover Type (gs_slidingShutter_iCover): 1; Stacking Direction (gs_foldingShutter_stacking): Dentro; Stacking Direction (gs_foldingShutter_iStacking): 1; Open in 3D: yes; 3D Opening Angle: 180 deg; Show 2D Symbol: yes; Show Opening Lines on Symbol: no; Panel Type (gs_shutPanel_type): Estilo 1; Panel Type (gs_shutPanel_iType): 1; Different Bottom Frame Width: no; Automatic Shutter Width: yes; Louver Angle: 30 deg; Holes Number Horizontal: 5; Holes Number Vertical: 8; Rolling Shutter Placement (gs_shutRoll_placement): Na Fachada; Rolling Shutter Placement (gs_shutRoll_iPlacement): 1; Box Type (gs_shutRoll_boxType): Rectangular; Box Type (gs_shutRoll_iBoxType): 1; Rail Position (gs_shutRoll_railPos): Em Guarnição; Rail Position (gs_shutRoll_iRailPos): 1; Show Casing behind Sunshade (gs_shutRoll_showCasingBehind): no; Insulation behind Box (gs_shutRoll_cutWallBehind): no; Include Height in Wallhole Height: no; Box Top Angle: 10 deg; Box Default Width (gs_shutRoll_boxDefaultSize): Largura Face de Vão; Box Default Width (gs_shutRoll_iBoxDefaultSize): 1; Venetian Blinds Placement (gs_shutLam_placement): Fixada na Fachada; Venetian Blinds Placement (gs_shutLam_iPlacement): 1; Insulation behind Box (gs_shutLam_cutWallBehind): no; Opened Box: yes; Rail: yes; Rail Position (gs_shutLam_railPos): Em Guarnição; Rail Position (gs_shutLam_iRailPos): 1; Show Casing behind Sunshade (gs_shutLam_showCasingBehind): no; Rotation Angle of Slats (gs_shutLam_rotation): 45 deg; Rotation Angle of Slats (gs_shutLam2_rotation): 45 deg; Masonry Arch (bMasonryArch): no; Masonry Arch (gs_masonry_arch_int): 2; Masonry Arch Type (gs_masonry_arch_structure): Stucco Arch; Masonry Arch Type (gs_masonry_arch_structure_int): 1; Arch on Header: yes; Niche below Arch: yes; Skewback Angle: 75 deg; Custom Niche Surface: no; Reveal Type (gs_reveal_type_new): No Reveal; Reveal Type (gs_reveal_type_int): 2; Bottom Reveal Type (gs_reveal_type_bottom): Uniform; Bottom Reveal Type (gs_reveal_type_bottom_int): 1; Outer Reveal Type: No Reveal; Reveal Type (gs_reveal_doubleOuterTypeInt): 0; Inner Reveal Type: No Reveal; Reveal Type (gs_reveal_doubleInnerTypeInt): 0; Uniform Jamb Depth: yes; Angle Side 2: 20 deg; Angle Side: 20 deg; Upper Side Angle: 20 deg; Bottom Side Angle: 20 deg; Use Wall Finish Component: no; Auto Turn Inside Face Plaster: yes; Turn Inside Face Plaster: 0; Auto Turn Outside Face Plaster: yes; Turn Outside Face Plaster: 0; Dimensionable on 2D: no; Show in 3D: no; Closure Type (gs_closure_type): No Closure; Closure Type (gs_closure_type_int): 1; Turn Skin on Side (gs_cavity_side): Both; Turn Skin on Side (iCavityClosureSide): 1; Number of Skins to Turn: 1; Number from (gs_nTurnDir): Outside Face; Number from (iCavityClosureTurnDir): 1; Place Closer on Side 2: yes; Place Closer on Side 1: yes; Place Closer on Top: no; Place Closer on Bottom: no; Place Closer to Skin: 1; Place Closer from Side (gs_cc_dutch_ClosureToSide): 1; Gap at Outside Skin: yes; Turn Skin to Closer: no; Insert Insulation Strip: yes; Show Insulation Strip: yes; Contour Pen (gs_penJoint): Aberturas - Corte Não Estrutural; Contour Line Type (gs_ltJoint): 1; Fill Type (gs_fillJoint): Isolamento 2; Fill Pen (gs_penJointFg): Geral - Geral; Fill Background Pen (gs_penJointBg): Elementos 2D - Desenhos; Custom Surface: no; Surface: Madeira - Pinho Granulado Horizontal; Contour Pen (gs_penPlug): Aberturas - Corte Não Estrutural; Contour Line Type (gs_ltPlug): 1; Fill Type (gs_fillPlug): Isolamento 2; Fill Pen (gs_penPlugFg): Geral - Geral; Fill Background Pen (gs_penPlugBg): Elementos 2D - Desenhos; Edited Jamb Side: 1; Edited Wall Side: 1; Edited Skin Number: 1; Turn-in Skin: no; Consider Skin as Plaster: no; Turn-in Thickness: 1; Hatch Orientation: 1; Separating Line at Turn-in: no; Separating Line Pen: Geral - Geral; Last Selected Side: no; Closure Method Changed Automatically: no; Connection on the Left: no; Connection on the Right: no; Connection on the Top: no; Connection on the Bottom: no; Wall Inset: no; Wall Inset Sizes (gs_parapet_sizes_st): Automatic; Wall Inset Sizes (iParapetSize): 1; Auto Width and Height Dimensions: yes; Wall Inset Bottom at (gs_parapet_bottom_st): Current Story; Wall Inset Bottom at (iParapetBottom): 1; Show Hidden Parapet: yes; Hidden Parapet Line Type: 1; Opening Angle of Sash 1 (openingAngle_01): 0 deg; Opening Angle of Sash 1 (openingAngle2_01): 0 deg; Opening Angle of Sash 2 (openingAngle_02): 0 deg; Opening Angle of Sash 2 (openingAngle2_02): 0 deg; Opening Angle of Sash 3 (openingAngle_03): 3.89618e-14 deg; Opening Angle of Sash 3 (openingAngle2_03): 0 deg; Opening Angle of Sash 4 (openingAngle_04): 0 deg; Opening Angle of Sash 4 (openingAngle2_04): 0 deg; Opening Angle of Sash 5 (openingAngle_05): 0 deg; Opening Angle of Sash 5 (openingAngle2_05): 0 deg; Opening Angle of Sash 6 (openingAngle_06): 0 deg; Opening Angle of Sash 6 (openingAngle2_06): 0 deg; Opening Angle of Sash 7 (openingAngle_07): 0 deg; Opening Angle of Sash 7 (openingAngle2_07): 0 deg; Opening Angle of Sash 8 (openingAngle_08): 0 deg; Opening Angle of Sash 8 (openingAngle2_08): 0 deg; Opening Angle of Sash 9 (openingAngle_09): 0 deg; Opening Angle of Sash 9 (openingAngle2_09): 0 deg; Opening Angle of Sash 10 (openingAngle_10): 0 deg; Opening Angle of Sash 10 (openingAngle2_10): 0 deg; Opening Angle in 2D: 0 deg; Override MVO for 2D Symbolic Display: no; Opening Line Type: 1; Opening Line Shape (or_SwingType): Curved; Opening Line Shape (or_iSwingType): 1; Opening Line Shape (or_SlidingType): Nenhum; Opening Line Shape (or_iSlidingType): 0; Opening Line Pen in 2D/3D (or_opLinePen): Aberturas - Geral; Opening Line Pen in 2D/3D (or_iOpLinePen): 3; Override MVO for 3D Projections: no; Show Opening Line: yes; Line Type Opening Side (or_opLineType3dIn): Solid Line; Line Type Opening Side (or_iOpLineType3dIn): 0; Line Type Opposite Side (or_opLineType3dOut): Solid Line; Line Type Opposite Side (or_iOpLineType3dOut): 0; Line Orientation (or_oplineStyle): Handle; Line Orientation (or_iOplineStyle): 1; Uncut Line Pen: Aberturas - Geral; Cut Line Pen: Aberturas - Moldura; Casing Cut Line Pen on Both Sides: Aberturas - Geral; Wall Contour Line (gs_wcont_line): Both Sides; Wall Contour Line (iWallContourLine): 4; Wall Contour Line Type Inside: 1; Wall Contour Line Type Outside: 1; Hidden Wall Contour Line Type Inside: 4; Hidden Wall Contour Line Type Outside: 4; Wall Contour Line Pen: Aberturas - Geral; Use Fills: yes; Frame Fill Type: Trama Vazia; Frame Fill Pen: Aberturas - Fundo de Trama; Frame Fill Background Pen: Aberturas - Fundo de Trama; Sash Fill Type: Ar (Vazio); Sash Fill Pen: Aberturas - Fundo de Trama; Sash Fill Background Pen: Fundos - Cor 1; Uncut Fill Type: Trama Vazia; Uncut Fill Pen: Aberturas - Fundo de Trama; Uncut Fill Background Pen: Aberturas - Fundo de Trama; Plan Symbol Fill Type: Trama Vazia; Plan Symbol Fill Pen: Aberturas - Fundo de Trama; Plan Symbol Fill Background Pen: Aberturas - Fundo de Trama; Sill 3D and Uncut Pen: Geral - Geral; Sill Section Contour Pen: Aberturas - Corte Não Estrutural; Sill Section Fill Type: Trama Vazia; Sill Section Fill Pen: Aberturas - Fundo de Trama; Sill Section Fill Bkg. Pen: Aberturas - Fundo de Trama; Section Insulation Contour Pen: Aberturas - Corte Não Estrutural; Section Insulation Fill Type: Isolamento 2; Section Insulation Fill Pen: Aberturas - Fundo de Trama; Section Insulation Fill Background Pen: Aberturas - Fundo de Trama; Board 3D and Uncut Pen: Geral - Geral; Board Section Contour Pen: Geral - Geral; Board Section Fill Type: Trama Vazia; Board Section Fill Pen: Fundos - Cor 1; Board Section Fill Bkg. Pen: Fundos - Cor 1; Casing Fill Type Inside: Trama Vazia; Casing Fill Pen Inside: Aberturas - Fundo de Trama; Casing Fill Background Pen Inside: Aberturas - Fundo de Trama; Casing Fill Type Outside: Trama Vazia; Casing Fill Pen Outside: Fundos - Cor 1; Casing Fill Background Pen Outside: Fundos - Cor 1; Arch Section Fill Type: Trama Vazia; Arch Section Fill Pen: Fundos - Cor 1; Arch Section Fill Bkg. Pen: Fundos - Cor 1; Ventilation Profile Section Fill Type: Ar (Vazio); Ventilation Profile Section Fill Pen: Fundos - Cor 1; Ventilation Profile Section Fill Background Pen: Fundos - Cor 1; Sunshade Symbol Line Type: 1; Sunshade Cut Line Pen: Geral - Geral; 3D/Section Uncut Line Pen: Geral - Geral; Sunshade Cut Fill Type: Trama Vazia; Sunshade Cut Fill Pen: Geral - Geral; Sunshade Cut Fill Background Pen: Window Background; Sunshade Insulation Fill Type: Trama Vazia; Sunshade Insulation Fill Pen: Geral - Geral; Sunshade Insulation Background Pen: Window Background; Frame Element Joinery: 2; Frame Pen: Aberturas - Geral; Sash Pen: Aberturas - Geral; Glass Pen: Aberturas - Fundo de Trama; Masonry Arch Pen: Paredes - Geral; Shadow: yes; Uniform Window Surfaces: yes; Frame Outside: Metal - Alumínio; Frame Inside: Metal - Alumínio; Sash Outside: Metal - Alumínio; Sash Inside: Metal - Alumínio; Louvers: Madeira - Pinho Granulado Horizontal; Glass: Vidro - Simples; Grid Outside: Metal - Alumínio; Grid Inside: Metal - Alumínio; Solid Panel Outside: Metal - Alumínio; Solid Panel Inside: Metal - Alumínio; Handle: Metal - Aço Inoxidável; Uniform Casing Surfaces: no; Interior Casing: Metal - Alumínio; Exterior Casing: Metal - Alumínio; Ventilation Profile: Metal - Alumínio; Shutter Panel: Madeira - Pinho Granulado Horizontal; Shutter Panel Frame: Madeira - Pinho Granulado Horizontal; Rolling Shutter Box: Metal - Aço Inoxidável; Rolling Shutter Blades: Pintura - Branco Titânio; Rolling Shutter Rail: Pintura - Branco Titânio; Venetian Blinds Box: Metal - Aço Inoxidável; Venetian Blinds Segments: Pintura - Branco Titânio; Sliding Shutter Rail: Metal - Aço Inoxidável; Sill (gs_sill_mat): Pedra - Granito Cinza; Brick Sill Mortar: Estuque - Branco Áspera; Board (gs_board_mat): Madeira - Pinho Granulado Horizontal; Masonry Arch Brick: Tijolo - Aparelho ao Comprido; Masonry Arch Mortar: Estuque - Branco Áspera; Masonry Arch Keystone: Pedra - Arenito 01; Niche: Pintura - Óxido de Chumbo Amarelo; Corner Column Surface: Metal - Alumínio; Opening Direction: 0; Display as Transom: no; Wall End Line Pen: Geral - Geral; Wall End Line Line Type: 4; Head Depth on Symbol: no; Head Depth Symbol Line Type: 4; Head Depth Symbol Pen: Texto - Geral; Window belongs to the Zone into which it opens: no; Cost: 0; Total Glazed Area (gs_list_glassarea_tmp): 0; Override Glazed Area: yes; Total Glazed Area (gs_list_glassarea): 0; Total Glass Perimeter: 0; Free Air Performance (mm2/l/m): 0; Group Type (FM_Type): Default Objects; Group Type (iFMType): 1; Object Weight: 0; Object Weight Unit: kg; Window Orientation Definition: 0; IFC Operation (ifc_optypestr): Other; IFC Operation (ifc_optype): 10; Shutter Opening Angle: 180 deg; Opening Line Style: 2
FABRICAÇÃO - Data de Fabricação: DD/MM/YYYY; Site do Produto: www.graphisoft.com
INFORMAÇÕES DO PRODUTO - Data de Aquisição: DD/MM/YYYY
ABERTURAS - Tipo de Abertura: Basculante; Material: Alumínio; Vidro
ZONAS - Iluminação Mínima: 0; Ventilação Mínima: 0
RODAPÉ (Expressão) - Comprimento da Barra (m): 2.4; Custo da Barra: 0
REVESTIMENTO DE PAREDE POR ZONA (Expressão) - Número de Linhas: 10; DImensão 1: 0 mm; Dimensão 2: 0 mm; Largura do Rejunte: 10 mm; Altura do Revestimento: 100 mm
PISOS (Expressão) - Índice de Perda (%): 10
COBERTURA (Expressão) - Rendimento de Telha Genérica (m2): 0; Índice de Perda Telhas (%): 0; Rendimento Cumeeira (ml): 0
ILUMINAÇÃO E VENTILAÇÃO (Expressão) - Atende: Atende; Não Atende: Não Atende
AC_Equantity_Vertical_Multi-Sash_Window_27 - Width: 840 mm; Height: 1200 mm; Z Dimension: 1000 mm; Bottom Level: 1000 mm; Top Level: 0 mm; Sill Height to Current Story: 1000 mm; Reveal to Wall Core: 50 mm; New Wall Fill Width Right: 150 mm; New Wall Fill Width Left: 150 mm; Connecting Wall Thickness: 0 mm; Connected Wall Thickness 2: 150 mm; Connected Wall Thickness 1: 150 mm; Corner Column Width: 0 mm; Corner Column Thickness: 0 mm; Corner Column Projection: 0 mm; Maximal Tolerance: 100 mm; Tolerance: 0 mm; Tolerance Left: 0 mm; Tolerance Right: 0 mm; Tolerance Upper: 0 mm; Tolerance Lower: 0 mm; Wallhole Width: 840 mm; Wallhole Height: 1200 mm; Reveal Width: 840 mm; Reveal Height: 1200 mm; Unit Width: 840 mm; Unit Height: 1200 mm; Axis Distance: 1200 mm; Pane Height 1: 201.667 mm; Pane Height 2: 184.167 mm; Pane Height 3: 204.167 mm; Pane Height 4: 204.167 mm; Pane Height 5: 204.167 mm; Pane Height 6: 201.667 mm; Pane Height 7: 500 mm; Pane Height 8: 500 mm; Pane Height 9: 500 mm; Remaining Pane Height: 170 mm; Frame Thickness: 50 mm; Frame Width: 35 mm; Frame Width Side 2: 47 mm; Upper Frame Width: 47 mm; Bottom Frame Width: 47 mm; Rebate Depth: 20 mm; Rebate Width: 20 mm; Middle Transom Width: 70 mm; Transom Width 1: 100 mm; Transom Width 2: 100 mm; Transom Width 3: 100 mm; Transom Width 4: 100 mm; Transom Width 5: 100 mm; Transom Width 6: 100 mm; Transom Width 7: 100 mm; Transom Width 8: 100 mm; Transom Width 9: 100 mm; Horizontal Division Height Sash 1: 106.75 mm; Horizontal Division Height Sash 2: 106.75 mm; Horizontal Division Height Sash 3: 110 mm; Horizontal Division Height Sash 4: 110 mm; Horizontal Division Height Sash 5: 110 mm; Horizontal Division Height Sash 6: 106.75 mm; Horizontal Division Height Sash 7: 900 mm; Horizontal Division Height Sash 8: 900 mm; Horizontal Division Height Sash 9: 900 mm; Horizontal Division Height Sash 10: 900 mm; Sash Frame Thickness: 20 mm; Sash Frame Width: 10 mm; Grill Width: 20 mm; Grill Thickness: 25 mm; Glass Thickness: 20 mm; Louvers Thickness: 10 mm; Louvers Width: 50 mm; Left Opening Oversize: 0 mm; Right Opening Oversize: 0 mm; Upper Opening Oversize: 0 mm; Lower Opening Oversize: 0 mm; Architrave Capital Width: 20 mm; Width Side 1 (gs_tw_right_out): 100 mm; Width Side 2 (gs_tw_left_out): 100 mm; Width Top (gs_tw_top_out): 100 mm; Width Bottom (gs_tw_bottom_out): 100 mm; Thickness on Wall (gs_trim_thk_out): 25 mm; Thickness in Wallhole (gs_trim_width_out): 25 mm; Offset (gs_trim_offs_out): 0 mm; Nosing (gs_trim_jambext_nosing_out): 50 mm; Top Overhang (gs_trimov_top_left_out): 0 mm; Top Overhang (gs_trimov_top_right_out): 0 mm; Bottom Overhang (gs_trimov_bot_left_out): 0 mm; Bottom Overhang (gs_trimov_bot_right_out): 0 mm; Bottom Overhang (casingOverhangBottomSideOut): 50 mm; Width Side 1 (gs_tw_right_in): 100 mm; Width Side 2 (gs_tw_left_in): 100 mm; Width Top (gs_tw_top_in): 100 mm; Width Bottom (gs_tw_bottom_in): 100 mm; Thickness on Wall (gs_trim_thk_in): 25 mm; Thickness in Wallhole (gs_trim_width_in): 25 mm; Offset (gs_trim_offs_in): 0 mm; Nosing (gs_trim_jambext_nosing_in): 50 mm; Top Overhang (gs_trimov_top_left_in): 0 mm; Top Overhang (gs_trimov_top_right_in): 0 mm; Bottom Overhang (gs_trimov_bot_left_in): 0 mm; Bottom Overhang (gs_trimov_bot_right_in): 0 mm; Width of Sill: 105 mm; Sill Top Width: 10 mm; Sill Top Height: 10 mm; Sill Thickness: 30 mm; Sill Front Side Thickness: 15 mm; Sill Elevation: 5 mm; Sill Drip Overlap: 20 mm; Sill Drip Width: 30 mm; Sill Nosing: 20 mm; Sill Overhang Left: 0 mm; Sill Overhang Right: 0 mm; Sill Slip-in Depth: 35 mm; Sill Slip from Wall: 0 mm; Rear Hole Depth (gs_sill_holeDepthBehind): 0 mm; Brick Thickness (gs_brick_sill_br_thk): 65 mm; Mortar Thickness (gs_brick_sill_mort_thk): 15 mm; Board Width: 80 mm; Board Thickness: 25 mm; Board Nosing: 30 mm; Board Overhang Left: 0 mm; Board Overhang Right: 0 mm; Board Slip-in Depth: 0 mm; Profile Height: 65 mm; Profile Thickness: 110 mm; Panel Height: 1500 mm; Inner Offset: 20 mm; Closing Depth: 0 mm; Extra Frame Width: 40 mm; Extra Frame Thickness: 30 mm; Rail Width: 30 mm; Hanging Stick Length: 20 mm; Hanging Stick Radius: 5 mm; Panel Distance: 6 mm; Outside Overhang: 0 mm; Inner Panel Width: 120 mm; 3D Opening Length: 1500 mm; 3D Closed Length: 0 mm; 3D Opening Length 1 (gs_shutter_opLength_1): 560 mm; 3D Opening Length 1 (gs_shutter_opLength_2): 140 mm; 3D Opening Height: 1500 mm; 3D Closed Height: 0 mm; Panel Thickness: 50 mm; Panel Frame Width: 50 mm; Frame Width Bottom: 50 mm; Panel Width: 0 mm; Panel Fill Thickness: 10 mm; Louver Thickness: 10 mm; Louver Width: 40 mm; Horizontal Frame Divider Width: 50 mm; Vertical Frame Divider Width: 50 mm; Hole Radius: 10 mm; Vertical Board Width: 100 mm; Z Frame Width: 50 mm; Z Frame Thickness: 25 mm; Vertical Boards Thickness: 25 mm; Horizontal Boards Thickness: 25 mm; Vertical Boards Approximate Width: 80 mm; Horizontal Boards Approximate Width: 115 mm; Box Height (gs_shutRoll_boxHeight): 200 mm; Box Depth (gs_shutRoll_boxWidth): 150 mm; Box Left Offset: 0 mm; Box Right Offset: 0 mm; Depth of Rails: 72.5 mm; Distance from Wall (gs_shutRoll_distFromWall): 0 mm; Distance from Header (gs_shutRoll_distFromHead): 0 mm; Slat Width: 50 mm; Box Height (gs_shutLam_boxHeight): 200 mm; Box Depth (gs_shutLam_boxWidth): 150 mm; Cover Width: 0 mm; Distance from Wall (gs_shutLam_distFromWall): 0 mm; Distance from Header (gs_shutLam_distFromHead): 0 mm; Segment Width (gs_shutLam_segmentWidth): 60 mm; Box Height (gs_shutLam2_boxHeight): 60 mm; Box Width: 60 mm; Distance from Window: 60 mm; Distance from Header (gs_shutLam2_distFromHead): 60 mm; Box Axis Height from Header: 0 mm; Segment Width (gs_shutLam2_segmentWidth): 60 mm; Distance between Arch and Window: 0 mm; Masonry Arch Overhang Left: 0 mm; Masonry Arch Overhang Right: 0 mm; Masonry Arch Rise: 30 mm; Masonry Arch Projection: 0 mm; Masonry Arch Height: 250 mm; Masonry Arch Depth: 120 mm; Rear Hole Depth (gs_masonry_arch_rearHoleDepth): 0 mm; Brick Thickness (gs_masonry_arch_brick_thk): 65 mm; Mortar Thickness (gs_masonry_arch_mort_thk): 10 mm; Keystone Width: 100 mm; Keystone Oversize: 0 mm; Keystone Projection: 10 mm; Reveal Depth (gs_wido_sill): 50 mm; Reveal Depth (AC_wido_sill): 50 mm; Jamb Depth Side 2: 60 mm; Jamb Depth: 60 mm; Inner Jamb Depth Side 2 (gs_reveal_splayed_innerLeft): 60 mm; Inner Jamb Depth (gs_reveal_splayed_innerRight): 60 mm; Inner Jamb Depth Side 2 (gs_reveal_double_innerLeft): 60 mm; Inner Jamb Depth (gs_reveal_double_innerRight): 60 mm; Head Jamb Depth: 60 mm; Sill Jamb Depth: 60 mm; Inner Head Depth (gs_reveal_splayed_innerTop): 60 mm; Inner Sill Depth (gs_reveal_splayed_innerBottom): 60 mm; Inner Head Depth (gs_reveal_double_innerTop): 60 mm; Inner Sill Depth (gs_reveal_double_innerBottom): 0 mm; Outer Jamb Depth: 80 mm; Plaster Thickness Limit: 40 mm; Distance of Skin from Closer: 0 mm; Closer Width: 38 mm; Closer Thickness: 100 mm; Strip Thickness: 25 mm; Profile Width: 75 mm; Custom Thickness: 15 mm; Skin Overhang to Frame Depth: 0 mm; Depth of Inset: 50 mm; Parapet Width: 1000 mm; Overhang Side 1: 0 mm; Overhang Side 2: 0 mm; Parapet Height: 900 mm; Bottom Overhang (gs_parapet_botelev): 0 mm; Opening Distance 1 Sash 1: 0 mm; Opening Distance 2 Sash 1: 0 mm; Opening Distance 1 Sash 2: 0 mm; Opening Distance 2 Sash 2: 0 mm; Opening Distance 1 Sash 3: 0 mm; Opening Distance 2 Sash 3: 0 mm; Opening Distance 1 Sash 4: 0 mm; Opening Distance 2 Sash 4: 0 mm; Opening Distance 1 Sash 5: 0 mm; Opening Distance 2 Sash 5: 0 mm; Opening Distance 1 Sash 6: 0 mm; Opening Distance 2 Sash 6: 0 mm; Opening Distance 1 Sash 7: 0 mm; Opening Distance 2 Sash 7: 0 mm; Opening Distance 1 Sash 8: 0 mm; Opening Distance 2 Sash 8: 0 mm; Opening Distance 1 Sash 9: 0 mm; Opening Distance 2 Sash 9: 0 mm; Opening Distance 1 Sash 10: 0 mm; Opening Distance 2 Sash 10: 0 mm; Opening Length in 2D: 0 mm; AC Left Opening Oversize: 0 mm; AC Right Opening Oversize: 0 mm; AC Upper Opening Oversize: 0 mm; AC Lower Opening Oversize: 0 mm
DESCRIÇÃO DA ESCADA (Expressão) - Abreviação da Largura da Escada: L; Abreviação da Altura do Espelho: E; Abreviação da Profundidade do Piso: P
ESTRUTURA (Expressão) - Custo por Volume (m3): 0
EXPRESSÕES DE TEXTO (Expressão) - Localização do Produto no Projeto: Projeto: Casa Térrea IsoladaLocal: Piso: Terreo Cômodo: Sala / Cozinha; ID de Aberturas com Master ID: 01J02; ID Dinâmico por Classificação: Janela -J02
BaseQuantities - GrossArea: 1.008 m2; Height: 1200 mm; Width: 840 mm; Perimeter: 4080 mm; Area: 1.008 m2; Volume: 0.0147355 m3; Depth: 150 mm; NetVolume: 0.0147355 m3
Component Quantities - Component, Component Volume (Net): 0.0147355 m3; Component, Component Volume (Gross): 0.0147355 m3
ALVENARIAS (Expressão) - Espessura da Argamassa: 10 mm
ArchiCADQuantities - W/D Opening Opening Volume: 0.1512 m3; W/D Opening Nominal Volume: 0.1512 m3; W/D Opening Surface Area: 3.2701 m2; W/D Opening Nominal Surface Area: 1.008 m2; W/D Opening Width on the Reveal Side: 840 mm; W/D Opening Height on the Reveal Side: 1200 mm; W/D Opening Width on the Side Opposite to the Reveal Side: 840 mm; W/D Opening Height on the Side Opposite to the Reveal Side: 1200 mm; W/D Opening Surface Area on the Reveal Side: 1.008 m2; W/D Opening Surface Area on the Side Opposite to the Reveal Side: 1.008 m2; Nominal W/D Opening Width on the Reveal Side: 840 mm; Nominal W/D Opening Height on the Reveal Side: 1200 mm; Nominal W/D Opening Width on the Side Opposite to the Reveal Side: 840 mm; Nominal W/D Opening Height on the Side Opposite to the Reveal Side: 1200 mm; Nominal W/D Opening Surface Area on the Reveal Side: 1.008 m2; Nominal W/D Opening Surface Area on the Side Opposite to the Reveal Side: 1.008 m2; Sill/Header Value: 1000 mm; W/D Nominal Sill Height: 1000 mm; W/D Sill Height on the Reveal Side: 1000 mm; W/D Sill Height on the Side Opposite to the Reveal Side: 1000 mm; W/D Nominal Head Height: 2200 mm; W/D Head Height on the Reveal Side: 2200 mm; W/D Head Height on the Side Opposite to the Reveal Side: 2200 mm; Wall Thickness: 150 mm; Frame Thickness: 50 mm; Height: 1200 mm; Volume (Net): 0.0147355 m3; Width: 840 mm; Elevation to Project Zero: 1000 mm; Elevation to 1º Nível de Referência: 1000 mm; Elevation to 2º Nível de Referência: 1000 mm; Elevation to Sea Level: 729220 mm; Elevation to Linked/Home Story: 1000 mm; Home Offset: 1000 mm; Surface Area: 3.2701 m2; Top Elevation To First Reference Level: 2200 mm; Top Elevation To Home Story: 2200 mm; Top Elevation To Project Zero: 2200 mm; Top Elevation To Sea Level: 730420 mm; Top Elevation To Second Reference Level: 2200 mm; Bottom Elevation To First Reference Level: 1000 mm; Bottom Elevation To Home Story: 1000 mm; Bottom Elevation To Project Zero: 1000 mm; Bottom Elevation To Sea Level: 729220 mm; Bottom Elevation To Second Reference Level: 1000 mm; Bottom Surface Area (Net): 3.2701 m2
